VERSION 5.8 ;
BUSBITCHARS "[]" ;
DIVIDERCHAR "/" ;
UNITS
    DATABASE MICRONS 1000 ;
END UNITS

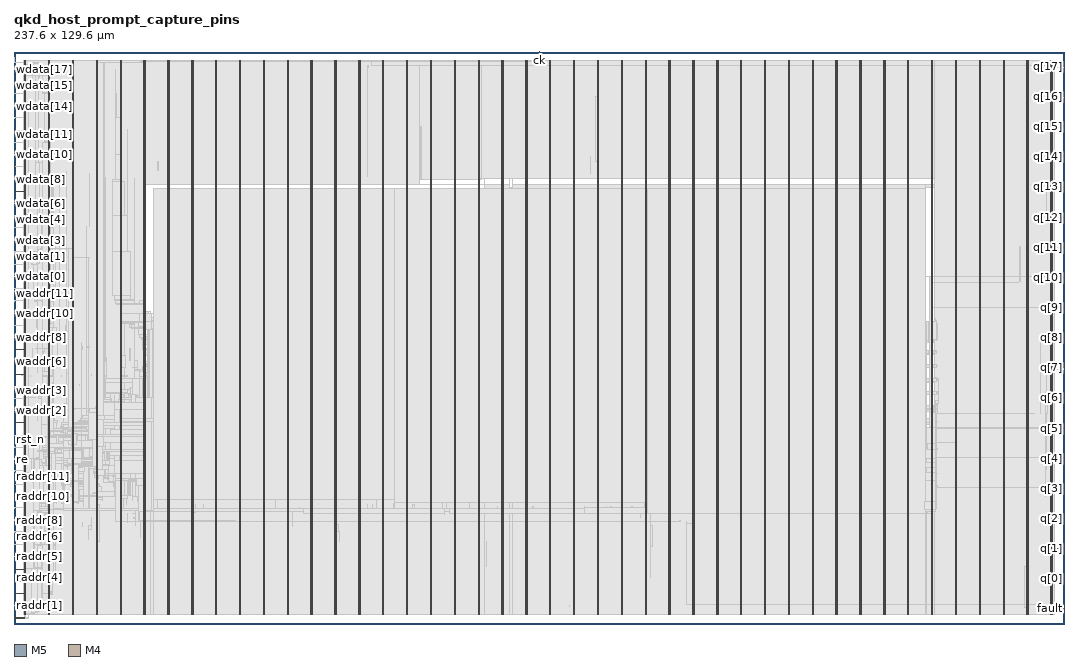
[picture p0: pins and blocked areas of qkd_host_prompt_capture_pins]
MACRO qkd_host_prompt_capture_pins
  FOREIGN qkd_host_prompt_capture_pins 0 0 ;
  CLASS BLOCK ;
  SIZE 237.6 BY 129.6 ;
  PIN ck
    DIRECTION INPUT ;
    USE SIGNAL ;
    PORT
      LAYER M5 ;
        RECT  118.8 129.516 118.824 129.6 ;
    END
    PORT
      LAYER M5 ;
        RECT  118.8 127.237 118.824 129.552 ;
    END
  END ck
  PIN fault
    DIRECTION OUTPUT ;
    USE SIGNAL ;
    PORT
      LAYER M4 ;
        RECT  237.516 3.408 237.6 3.432 ;
    END
    PORT
      LAYER M4 ;
        RECT  237.481 3.408 237.564 3.432 ;
    END
  END fault
  PIN q[0]
    DIRECTION OUTPUT ;
    USE SIGNAL ;
    PORT
      LAYER M4 ;
        RECT  237.516 10.224 237.6 10.248 ;
    END
    PORT
      LAYER M4 ;
        RECT  235.969 10.224 237.564 10.248 ;
    END
  END q[0]
  PIN q[10]
    DIRECTION OUTPUT ;
    USE SIGNAL ;
    PORT
      LAYER M4 ;
        RECT  237.516 78.432 237.6 78.456 ;
    END
    PORT
      LAYER M4 ;
        RECT  236.329 78.432 237.564 78.456 ;
    END
  END q[10]
  PIN q[11]
    DIRECTION OUTPUT ;
    USE SIGNAL ;
    PORT
      LAYER M4 ;
        RECT  237.516 85.248 237.6 85.272 ;
    END
    PORT
      LAYER M4 ;
        RECT  236.509 85.248 237.564 85.272 ;
    END
  END q[11]
  PIN q[12]
    DIRECTION OUTPUT ;
    USE SIGNAL ;
    PORT
      LAYER M4 ;
        RECT  237.516 92.064 237.6 92.088 ;
    END
    PORT
      LAYER M4 ;
        RECT  236.509 92.064 237.564 92.088 ;
    END
  END q[12]
  PIN q[13]
    DIRECTION OUTPUT ;
    USE SIGNAL ;
    PORT
      LAYER M4 ;
        RECT  237.516 98.88 237.6 98.904 ;
    END
    PORT
      LAYER M4 ;
        RECT  236.545 98.88 237.564 98.904 ;
    END
  END q[13]
  PIN q[14]
    DIRECTION OUTPUT ;
    USE SIGNAL ;
    PORT
      LAYER M4 ;
        RECT  237.516 105.696 237.6 105.72 ;
    END
    PORT
      LAYER M4 ;
        RECT  236.509 105.696 237.564 105.72 ;
    END
  END q[14]
  PIN q[15]
    DIRECTION OUTPUT ;
    USE SIGNAL ;
    PORT
      LAYER M4 ;
        RECT  237.516 112.512 237.6 112.536 ;
    END
    PORT
      LAYER M4 ;
        RECT  236.509 112.512 237.564 112.536 ;
    END
  END q[15]
  PIN q[16]
    DIRECTION OUTPUT ;
    USE SIGNAL ;
    PORT
      LAYER M4 ;
        RECT  237.516 119.376 237.6 119.4 ;
    END
    PORT
      LAYER M4 ;
        RECT  237.481 119.376 237.564 119.4 ;
    END
  END q[16]
  PIN q[17]
    DIRECTION OUTPUT ;
    USE SIGNAL ;
    PORT
      LAYER M4 ;
        RECT  237.516 126.192 237.6 126.216 ;
    END
    PORT
      LAYER M4 ;
        RECT  237.481 126.192 237.564 126.216 ;
    END
  END q[17]
  PIN q[1]
    DIRECTION OUTPUT ;
    USE SIGNAL ;
    PORT
      LAYER M4 ;
        RECT  237.516 17.04 237.6 17.064 ;
    END
    PORT
      LAYER M4 ;
        RECT  235.969 17.04 237.564 17.064 ;
    END
  END q[1]
  PIN q[2]
    DIRECTION OUTPUT ;
    USE SIGNAL ;
    PORT
      LAYER M4 ;
        RECT  237.516 23.856 237.6 23.88 ;
    END
    PORT
      LAYER M4 ;
        RECT  235.969 23.856 237.564 23.88 ;
    END
  END q[2]
  PIN q[3]
    DIRECTION OUTPUT ;
    USE SIGNAL ;
    PORT
      LAYER M4 ;
        RECT  237.516 30.672 237.6 30.696 ;
    END
    PORT
      LAYER M4 ;
        RECT  236.509 30.672 237.564 30.696 ;
    END
  END q[3]
  PIN q[4]
    DIRECTION OUTPUT ;
    USE SIGNAL ;
    PORT
      LAYER M4 ;
        RECT  237.516 37.488 237.6 37.512 ;
    END
    PORT
      LAYER M4 ;
        RECT  236.509 37.488 237.564 37.512 ;
    END
  END q[4]
  PIN q[5]
    DIRECTION OUTPUT ;
    USE SIGNAL ;
    PORT
      LAYER M4 ;
        RECT  237.516 44.304 237.6 44.328 ;
    END
    PORT
      LAYER M4 ;
        RECT  236.509 44.304 237.564 44.328 ;
    END
  END q[5]
  PIN q[6]
    DIRECTION OUTPUT ;
    USE SIGNAL ;
    PORT
      LAYER M4 ;
        RECT  237.516 51.168 237.6 51.192 ;
    END
    PORT
      LAYER M4 ;
        RECT  236.509 51.168 237.564 51.192 ;
    END
  END q[6]
  PIN q[7]
    DIRECTION OUTPUT ;
    USE SIGNAL ;
    PORT
      LAYER M4 ;
        RECT  237.516 57.984 237.6 58.008 ;
    END
    PORT
      LAYER M4 ;
        RECT  237.481 57.984 237.564 58.008 ;
    END
  END q[7]
  PIN q[8]
    DIRECTION OUTPUT ;
    USE SIGNAL ;
    PORT
      LAYER M4 ;
        RECT  237.516 64.8 237.6 64.824 ;
    END
    PORT
      LAYER M4 ;
        RECT  235.969 64.8 237.564 64.824 ;
    END
  END q[8]
  PIN q[9]
    DIRECTION OUTPUT ;
    USE SIGNAL ;
    PORT
      LAYER M4 ;
        RECT  237.516 71.616 237.6 71.64 ;
    END
    PORT
      LAYER M4 ;
        RECT  236.509 71.616 237.564 71.64 ;
    END
  END q[9]
  PIN raddr[0]
    DIRECTION INPUT ;
    USE SIGNAL ;
    PORT
      LAYER M4 ;
        RECT  0 1.344 0.084 1.368 ;
    END
    PORT
      LAYER M4 ;
        RECT  0.06 1.344 2.408 1.368 ;
    END
  END raddr[0]
  PIN raddr[10]
    DIRECTION INPUT ;
    USE SIGNAL ;
    PORT
      LAYER M4 ;
        RECT  0 28.944 0.084 28.968 ;
    END
    PORT
      LAYER M4 ;
        RECT  0.06 28.944 0.137 28.968 ;
    END
  END raddr[10]
  PIN raddr[11]
    DIRECTION INPUT ;
    USE SIGNAL ;
    PORT
      LAYER M4 ;
        RECT  0 31.68 0.084 31.704 ;
    END
    PORT
      LAYER M4 ;
        RECT  0.06 31.68 0.137 31.704 ;
    END
  END raddr[11]
  PIN raddr[12]
    DIRECTION INPUT ;
    USE SIGNAL ;
    PORT
      LAYER M4 ;
        RECT  0 34.464 0.084 34.488 ;
    END
    PORT
      LAYER M4 ;
        RECT  0.06 34.464 0.137 34.488 ;
    END
  END raddr[12]
  PIN raddr[1]
    DIRECTION INPUT ;
    USE SIGNAL ;
    PORT
      LAYER M4 ;
        RECT  0 4.128 0.084 4.152 ;
    END
    PORT
      LAYER M4 ;
        RECT  0.06 4.128 0.137 4.152 ;
    END
  END raddr[1]
  PIN raddr[2]
    DIRECTION INPUT ;
    USE SIGNAL ;
    PORT
      LAYER M4 ;
        RECT  0 6.864 0.084 6.888 ;
    END
    PORT
      LAYER M4 ;
        RECT  0.06 6.864 2.408 6.888 ;
    END
  END raddr[2]
  PIN raddr[3]
    DIRECTION INPUT ;
    USE SIGNAL ;
    PORT
      LAYER M4 ;
        RECT  0 9.648 0.084 9.672 ;
    END
    PORT
      LAYER M4 ;
        RECT  0.06 9.648 2.408 9.672 ;
    END
  END raddr[3]
  PIN raddr[4]
    DIRECTION INPUT ;
    USE SIGNAL ;
    PORT
      LAYER M4 ;
        RECT  0 12.384 0.084 12.408 ;
    END
    PORT
      LAYER M4 ;
        RECT  0.06 12.384 2.408 12.408 ;
    END
  END raddr[4]
  PIN raddr[5]
    DIRECTION INPUT ;
    USE SIGNAL ;
    PORT
      LAYER M4 ;
        RECT  0 15.168 0.084 15.192 ;
    END
    PORT
      LAYER M4 ;
        RECT  0.06 15.168 0.137 15.192 ;
    END
  END raddr[5]
  PIN raddr[6]
    DIRECTION INPUT ;
    USE SIGNAL ;
    PORT
      LAYER M4 ;
        RECT  0 17.904 0.084 17.928 ;
    END
    PORT
      LAYER M4 ;
        RECT  0.06 17.904 0.137 17.928 ;
    END
  END raddr[6]
  PIN raddr[7]
    DIRECTION INPUT ;
    USE SIGNAL ;
    PORT
      LAYER M4 ;
        RECT  0 20.688 0.084 20.712 ;
    END
    PORT
      LAYER M4 ;
        RECT  0.06 20.688 0.137 20.712 ;
    END
  END raddr[7]
  PIN raddr[8]
    DIRECTION INPUT ;
    USE SIGNAL ;
    PORT
      LAYER M4 ;
        RECT  0 23.424 0.084 23.448 ;
    END
    PORT
      LAYER M4 ;
        RECT  0.06 23.424 0.137 23.448 ;
    END
  END raddr[8]
  PIN raddr[9]
    DIRECTION INPUT ;
    USE SIGNAL ;
    PORT
      LAYER M4 ;
        RECT  0 26.208 0.084 26.232 ;
    END
    PORT
      LAYER M4 ;
        RECT  0.06 26.208 0.137 26.232 ;
    END
  END raddr[9]
  PIN re
    DIRECTION INPUT ;
    USE SIGNAL ;
    PORT
      LAYER M4 ;
        RECT  0 37.2 0.084 37.224 ;
    END
    PORT
      LAYER M4 ;
        RECT  0.06 37.2 0.137 37.224 ;
    END
  END re
  PIN rst_n
    DIRECTION INPUT ;
    USE SIGNAL ;
    PORT
      LAYER M4 ;
        RECT  0 39.984 0.084 40.008 ;
    END
    PORT
      LAYER M4 ;
        RECT  0.06 39.984 0.137 40.008 ;
    END
  END rst_n
  PIN waddr[0]
    DIRECTION INPUT ;
    USE SIGNAL ;
    PORT
      LAYER M4 ;
        RECT  0 42.72 0.084 42.744 ;
    END
    PORT
      LAYER M4 ;
        RECT  0.06 42.72 0.137 42.744 ;
    END
  END waddr[0]
  PIN waddr[10]
    DIRECTION INPUT ;
    USE SIGNAL ;
    PORT
      LAYER M4 ;
        RECT  0 70.32 0.084 70.344 ;
    END
    PORT
      LAYER M4 ;
        RECT  0.06 70.32 0.137 70.344 ;
    END
  END waddr[10]
  PIN waddr[11]
    DIRECTION INPUT ;
    USE SIGNAL ;
    PORT
      LAYER M4 ;
        RECT  0 73.056 0.084 73.08 ;
    END
    PORT
      LAYER M4 ;
        RECT  0.06 73.056 0.137 73.08 ;
    END
  END waddr[11]
  PIN waddr[12]
    DIRECTION INPUT ;
    USE SIGNAL ;
    PORT
      LAYER M4 ;
        RECT  0 75.84 0.084 75.864 ;
    END
    PORT
      LAYER M4 ;
        RECT  0.06 75.84 0.137 75.864 ;
    END
  END waddr[12]
  PIN waddr[1]
    DIRECTION INPUT ;
    USE SIGNAL ;
    PORT
      LAYER M4 ;
        RECT  0 45.504 0.084 45.528 ;
    END
    PORT
      LAYER M4 ;
        RECT  0.06 45.504 2.408 45.528 ;
    END
  END waddr[1]
  PIN waddr[2]
    DIRECTION INPUT ;
    USE SIGNAL ;
    PORT
      LAYER M4 ;
        RECT  0 48.24 0.084 48.264 ;
    END
    PORT
      LAYER M4 ;
        RECT  0.06 48.24 0.137 48.264 ;
    END
  END waddr[2]
  PIN waddr[3]
    DIRECTION INPUT ;
    USE SIGNAL ;
    PORT
      LAYER M4 ;
        RECT  0 51.024 0.084 51.048 ;
    END
    PORT
      LAYER M4 ;
        RECT  0.06 51.024 0.137 51.048 ;
    END
  END waddr[3]
  PIN waddr[4]
    DIRECTION INPUT ;
    USE SIGNAL ;
    PORT
      LAYER M4 ;
        RECT  0 53.76 0.084 53.784 ;
    END
    PORT
      LAYER M4 ;
        RECT  0.06 53.76 0.137 53.784 ;
    END
  END waddr[4]
  PIN waddr[5]
    DIRECTION INPUT ;
    USE SIGNAL ;
    PORT
      LAYER M4 ;
        RECT  0 56.496 0.084 56.52 ;
    END
    PORT
      LAYER M4 ;
        RECT  0.06 56.496 2.408 56.52 ;
    END
  END waddr[5]
  PIN waddr[6]
    DIRECTION INPUT ;
    USE SIGNAL ;
    PORT
      LAYER M4 ;
        RECT  0 59.28 0.084 59.304 ;
    END
    PORT
      LAYER M4 ;
        RECT  0.06 59.28 0.137 59.304 ;
    END
  END waddr[6]
  PIN waddr[7]
    DIRECTION INPUT ;
    USE SIGNAL ;
    PORT
      LAYER M4 ;
        RECT  0 62.016 0.084 62.04 ;
    END
    PORT
      LAYER M4 ;
        RECT  0.06 62.016 2.408 62.04 ;
    END
  END waddr[7]
  PIN waddr[8]
    DIRECTION INPUT ;
    USE SIGNAL ;
    PORT
      LAYER M4 ;
        RECT  0 64.8 0.084 64.824 ;
    END
    PORT
      LAYER M4 ;
        RECT  0.06 64.8 0.137 64.824 ;
    END
  END waddr[8]
  PIN waddr[9]
    DIRECTION INPUT ;
    USE SIGNAL ;
    PORT
      LAYER M4 ;
        RECT  0 67.536 0.084 67.56 ;
    END
    PORT
      LAYER M4 ;
        RECT  0.06 67.536 0.137 67.56 ;
    END
  END waddr[9]
  PIN wdata[0]
    DIRECTION INPUT ;
    USE SIGNAL ;
    PORT
      LAYER M4 ;
        RECT  0 78.576 0.084 78.6 ;
    END
    PORT
      LAYER M4 ;
        RECT  0.06 78.576 0.137 78.6 ;
    END
  END wdata[0]
  PIN wdata[10]
    DIRECTION INPUT ;
    USE SIGNAL ;
    PORT
      LAYER M4 ;
        RECT  0 106.128 0.084 106.152 ;
    END
    PORT
      LAYER M4 ;
        RECT  0.06 106.128 0.137 106.152 ;
    END
  END wdata[10]
  PIN wdata[11]
    DIRECTION INPUT ;
    USE SIGNAL ;
    PORT
      LAYER M4 ;
        RECT  0 108.912 0.084 108.936 ;
    END
    PORT
      LAYER M4 ;
        RECT  0.06 108.912 0.137 108.936 ;
    END
  END wdata[11]
  PIN wdata[12]
    DIRECTION INPUT ;
    USE SIGNAL ;
    PORT
      LAYER M4 ;
        RECT  0 111.648 0.084 111.672 ;
    END
    PORT
      LAYER M4 ;
        RECT  0.06 111.648 2.408 111.672 ;
    END
  END wdata[12]
  PIN wdata[13]
    DIRECTION INPUT ;
    USE SIGNAL ;
    PORT
      LAYER M4 ;
        RECT  0 114.432 0.084 114.456 ;
    END
    PORT
      LAYER M4 ;
        RECT  0.06 114.432 0.137 114.456 ;
    END
  END wdata[13]
  PIN wdata[14]
    DIRECTION INPUT ;
    USE SIGNAL ;
    PORT
      LAYER M4 ;
        RECT  0 117.168 0.084 117.192 ;
    END
    PORT
      LAYER M4 ;
        RECT  0.06 117.168 0.137 117.192 ;
    END
  END wdata[14]
  PIN wdata[15]
    DIRECTION INPUT ;
    USE SIGNAL ;
    PORT
      LAYER M4 ;
        RECT  0 119.952 0.084 119.976 ;
    END
    PORT
      LAYER M4 ;
        RECT  0.06 119.952 0.137 119.976 ;
    END
  END wdata[15]
  PIN wdata[16]
    DIRECTION INPUT ;
    USE SIGNAL ;
    PORT
      LAYER M4 ;
        RECT  0 122.688 0.084 122.712 ;
    END
    PORT
      LAYER M4 ;
        RECT  0.06 122.688 0.569 122.712 ;
    END
  END wdata[16]
  PIN wdata[17]
    DIRECTION INPUT ;
    USE SIGNAL ;
    PORT
      LAYER M4 ;
        RECT  0 125.472 0.084 125.496 ;
    END
    PORT
      LAYER M4 ;
        RECT  0.06 125.472 0.137 125.496 ;
    END
  END wdata[17]
  PIN wdata[1]
    DIRECTION INPUT ;
    USE SIGNAL ;
    PORT
      LAYER M4 ;
        RECT  0 81.312 0.084 81.336 ;
    END
    PORT
      LAYER M4 ;
        RECT  0.06 81.312 0.137 81.336 ;
    END
  END wdata[1]
  PIN wdata[2]
    DIRECTION INPUT ;
    USE SIGNAL ;
    PORT
      LAYER M4 ;
        RECT  0 84.096 0.084 84.12 ;
    END
    PORT
      LAYER M4 ;
        RECT  0.06 84.096 0.137 84.12 ;
    END
  END wdata[2]
  PIN wdata[3]
    DIRECTION INPUT ;
    USE SIGNAL ;
    PORT
      LAYER M4 ;
        RECT  0 86.832 0.084 86.856 ;
    END
    PORT
      LAYER M4 ;
        RECT  0.06 86.832 0.137 86.856 ;
    END
  END wdata[3]
  PIN wdata[4]
    DIRECTION INPUT ;
    USE SIGNAL ;
    PORT
      LAYER M4 ;
        RECT  0 89.616 0.084 89.64 ;
    END
    PORT
      LAYER M4 ;
        RECT  0.06 89.616 0.137 89.64 ;
    END
  END wdata[4]
  PIN wdata[5]
    DIRECTION INPUT ;
    USE SIGNAL ;
    PORT
      LAYER M4 ;
        RECT  0 92.352 0.084 92.376 ;
    END
    PORT
      LAYER M4 ;
        RECT  0.06 92.352 0.137 92.376 ;
    END
  END wdata[5]
  PIN wdata[6]
    DIRECTION INPUT ;
    USE SIGNAL ;
    PORT
      LAYER M4 ;
        RECT  0 95.136 0.084 95.16 ;
    END
    PORT
      LAYER M4 ;
        RECT  0.06 95.136 0.137 95.16 ;
    END
  END wdata[6]
  PIN wdata[7]
    DIRECTION INPUT ;
    USE SIGNAL ;
    PORT
      LAYER M4 ;
        RECT  0 97.872 0.084 97.896 ;
    END
    PORT
      LAYER M4 ;
        RECT  0.06 97.872 2.408 97.896 ;
    END
  END wdata[7]
  PIN wdata[8]
    DIRECTION INPUT ;
    USE SIGNAL ;
    PORT
      LAYER M4 ;
        RECT  0 100.656 0.084 100.68 ;
    END
    PORT
      LAYER M4 ;
        RECT  0.06 100.656 0.137 100.68 ;
    END
  END wdata[8]
  PIN wdata[9]
    DIRECTION INPUT ;
    USE SIGNAL ;
    PORT
      LAYER M4 ;
        RECT  0 103.392 0.084 103.416 ;
    END
    PORT
      LAYER M4 ;
        RECT  0.06 103.392 0.137 103.416 ;
    END
  END wdata[9]
  PIN we
    DIRECTION INPUT ;
    USE SIGNAL ;
    PORT
      LAYER M4 ;
        RECT  0 128.208 0.084 128.232 ;
    END
    PORT
      LAYER M4 ;
        RECT  0.06 128.208 0.137 128.232 ;
    END
  END we
  PIN VDD
    DIRECTION INOUT ;
    USE POWER ;
    PORT
      LAYER M5 ;
        RECT  234.792 2.151 234.912 127.449 ;
        RECT  229.392 2.151 229.512 127.449 ;
        RECT  223.992 2.151 224.112 127.449 ;
        RECT  218.592 2.151 218.712 127.449 ;
        RECT  213.192 2.151 213.312 127.449 ;
        RECT  207.792 2.151 207.912 127.449 ;
        RECT  202.392 2.151 202.512 127.449 ;
        RECT  196.992 2.151 197.112 127.449 ;
        RECT  191.592 2.151 191.712 127.449 ;
        RECT  186.192 2.151 186.312 127.449 ;
        RECT  180.792 2.151 180.912 127.449 ;
        RECT  175.392 2.151 175.512 127.449 ;
        RECT  169.992 2.151 170.112 127.449 ;
        RECT  164.592 2.151 164.712 127.449 ;
        RECT  159.192 2.151 159.312 127.449 ;
        RECT  153.792 2.151 153.912 127.449 ;
        RECT  148.392 2.151 148.512 127.449 ;
        RECT  142.992 2.151 143.112 127.449 ;
        RECT  137.592 2.151 137.712 127.449 ;
        RECT  132.192 2.151 132.312 127.449 ;
        RECT  126.792 2.151 126.912 127.449 ;
        RECT  121.392 2.151 121.512 127.449 ;
        RECT  115.992 2.151 116.112 127.449 ;
        RECT  110.592 2.151 110.712 127.449 ;
        RECT  105.192 2.151 105.312 127.449 ;
        RECT  99.792 2.151 99.912 127.449 ;
        RECT  94.392 2.151 94.512 127.449 ;
        RECT  88.992 2.151 89.112 127.449 ;
        RECT  83.592 2.151 83.712 127.449 ;
        RECT  78.192 2.151 78.312 127.449 ;
        RECT  72.792 2.151 72.912 127.449 ;
        RECT  67.392 2.151 67.512 127.449 ;
        RECT  61.992 2.151 62.112 127.449 ;
        RECT  56.592 2.151 56.712 127.449 ;
        RECT  51.192 2.151 51.312 127.449 ;
        RECT  45.792 2.151 45.912 127.449 ;
        RECT  40.392 2.151 40.512 127.449 ;
        RECT  34.992 2.151 35.112 127.449 ;
        RECT  29.592 2.151 29.712 127.449 ;
        RECT  24.192 2.151 24.312 127.449 ;
        RECT  18.792 2.151 18.912 127.449 ;
        RECT  13.392 2.151 13.512 127.449 ;
        RECT  7.992 2.151 8.112 127.449 ;
        RECT  2.592 2.151 2.712 127.449 ;
    END
  END VDD
  PIN VSS
    DIRECTION INOUT ;
    USE GROUND ;
    PORT
      LAYER M5 ;
        RECT  234.6 2.137 234.72 127.463 ;
        RECT  229.2 2.137 229.32 127.463 ;
        RECT  223.8 2.137 223.92 127.463 ;
        RECT  218.4 2.137 218.52 127.463 ;
        RECT  213 2.137 213.12 127.463 ;
        RECT  207.6 2.137 207.72 127.463 ;
        RECT  202.2 2.137 202.32 127.463 ;
        RECT  196.8 2.137 196.92 127.463 ;
        RECT  191.4 2.137 191.52 127.463 ;
        RECT  186 2.137 186.12 127.463 ;
        RECT  180.6 2.137 180.72 127.463 ;
        RECT  175.2 2.137 175.32 127.463 ;
        RECT  169.8 2.137 169.92 127.463 ;
        RECT  164.4 2.137 164.52 127.463 ;
        RECT  159 2.137 159.12 127.463 ;
        RECT  153.6 2.137 153.72 127.463 ;
        RECT  148.2 2.137 148.32 127.463 ;
        RECT  142.8 2.137 142.92 127.463 ;
        RECT  137.4 2.137 137.52 127.463 ;
        RECT  132 2.137 132.12 127.463 ;
        RECT  126.6 2.137 126.72 127.463 ;
        RECT  121.2 2.137 121.32 127.463 ;
        RECT  115.8 2.137 115.92 127.463 ;
        RECT  110.4 2.137 110.52 127.463 ;
        RECT  105 2.137 105.12 127.463 ;
        RECT  99.6 2.137 99.72 127.463 ;
        RECT  94.2 2.137 94.32 127.463 ;
        RECT  88.8 2.137 88.92 127.463 ;
        RECT  83.4 2.137 83.52 127.463 ;
        RECT  78 2.137 78.12 127.463 ;
        RECT  72.6 2.137 72.72 127.463 ;
        RECT  67.2 2.137 67.32 127.463 ;
        RECT  61.8 2.137 61.92 127.463 ;
        RECT  56.4 2.137 56.52 127.463 ;
        RECT  51 2.137 51.12 127.463 ;
        RECT  45.6 2.137 45.72 127.463 ;
        RECT  40.2 2.137 40.32 127.463 ;
        RECT  34.8 2.137 34.92 127.463 ;
        RECT  29.4 2.137 29.52 127.463 ;
        RECT  24 2.137 24.12 127.463 ;
        RECT  18.6 2.137 18.72 127.463 ;
        RECT  13.2 2.137 13.32 127.463 ;
        RECT  7.8 2.137 7.92 127.463 ;
        RECT  2.4 2.137 2.52 127.463 ;
    END
  END VSS
  # OT_OBS_CLOSED layer=M5 d_um=1.536 added=61
  OBS
    LAYER RVTN ;
     RECT  2.16 2.16 235.44 2.295 ;
     RECT  2.16 2.565 235.44 2.835 ;
     RECT  2.16 3.105 235.44 3.375 ;
     RECT  2.16 3.645 235.44 3.915 ;
     RECT  2.16 4.185 235.44 4.455 ;
     RECT  2.16 4.725 235.44 4.995 ;
     RECT  2.16 5.265 235.44 5.535 ;
     RECT  2.16 5.805 235.44 6.075 ;
     RECT  2.16 6.345 235.44 6.615 ;
     RECT  2.16 6.885 235.44 7.155 ;
     RECT  2.16 7.425 235.44 7.695 ;
     RECT  2.16 7.965 235.44 8.235 ;
     RECT  2.16 8.505 235.44 8.775 ;
     RECT  2.16 9.045 235.44 9.315 ;
     RECT  2.16 9.585 235.44 9.855 ;
     RECT  2.16 10.125 235.44 10.395 ;
     RECT  2.16 10.665 235.44 10.935 ;
     RECT  2.16 11.205 235.44 11.475 ;
     RECT  2.16 11.745 235.44 12.015 ;
     RECT  2.16 12.285 235.44 12.555 ;
     RECT  2.16 12.825 235.44 13.095 ;
     RECT  2.16 13.365 235.44 13.635 ;
     RECT  2.16 13.905 235.44 14.175 ;
     RECT  2.16 14.445 235.44 14.715 ;
     RECT  2.16 14.985 235.44 15.255 ;
     RECT  2.16 15.525 235.44 15.795 ;
     RECT  2.16 16.065 235.44 16.335 ;
     RECT  2.16 16.605 235.44 16.875 ;
     RECT  2.16 17.145 235.44 17.415 ;
     RECT  2.16 17.685 235.44 17.955 ;
     RECT  2.16 18.225 235.44 18.495 ;
     RECT  2.16 18.765 235.44 19.035 ;
     RECT  2.16 19.305 235.44 19.575 ;
     RECT  2.16 19.845 235.44 20.115 ;
     RECT  2.16 20.385 235.44 20.655 ;
     RECT  2.16 20.925 235.44 21.195 ;
     RECT  2.16 21.465 235.44 21.735 ;
     RECT  2.16 22.005 235.44 22.275 ;
     RECT  2.16 22.545 235.44 22.815 ;
     RECT  2.16 23.085 235.44 23.355 ;
     RECT  2.16 23.625 235.44 23.895 ;
     RECT  2.16 24.165 235.44 24.435 ;
     RECT  2.16 24.705 235.44 24.975 ;
     RECT  2.16 25.245 235.44 25.515 ;
     RECT  2.16 25.785 235.44 25.92 ;
     RECT  2.16 25.92 29.484 26.055 ;
     RECT  208.332 25.92 235.44 26.055 ;
     RECT  2.16 26.325 29.484 26.595 ;
     RECT  208.332 26.325 235.44 26.595 ;
     RECT  2.16 26.865 29.484 27.135 ;
     RECT  208.332 26.865 235.44 27.135 ;
     RECT  2.16 27.405 29.484 27.675 ;
     RECT  208.332 27.405 235.44 27.675 ;
     RECT  2.16 27.945 29.484 28.215 ;
     RECT  208.332 27.945 235.44 28.215 ;
     RECT  2.16 28.485 29.484 28.755 ;
     RECT  208.332 28.485 235.44 28.755 ;
     RECT  2.16 29.025 29.484 29.295 ;
     RECT  208.332 29.025 235.44 29.295 ;
     RECT  2.16 29.565 29.484 29.835 ;
     RECT  208.332 29.565 235.44 29.835 ;
     RECT  2.16 30.105 29.484 30.375 ;
     RECT  208.332 30.105 235.44 30.375 ;
     RECT  2.16 30.645 29.484 30.915 ;
     RECT  208.332 30.645 235.44 30.915 ;
     RECT  2.16 31.185 29.484 31.455 ;
     RECT  208.332 31.185 235.44 31.455 ;
     RECT  2.16 31.725 29.484 31.995 ;
     RECT  208.332 31.725 235.44 31.995 ;
     RECT  2.16 32.265 29.484 32.535 ;
     RECT  208.332 32.265 235.44 32.535 ;
     RECT  2.16 32.805 29.484 33.075 ;
     RECT  208.332 32.805 235.44 33.075 ;
     RECT  2.16 33.345 29.484 33.615 ;
     RECT  208.332 33.345 235.44 33.615 ;
     RECT  2.16 33.885 29.484 34.155 ;
     RECT  208.332 33.885 235.44 34.155 ;
     RECT  2.16 34.425 29.484 34.695 ;
     RECT  208.332 34.425 235.44 34.695 ;
     RECT  2.16 34.965 29.484 35.235 ;
     RECT  208.332 34.965 235.44 35.235 ;
     RECT  2.16 35.505 29.484 35.775 ;
     RECT  208.332 35.505 235.44 35.775 ;
     RECT  2.16 36.045 29.484 36.315 ;
     RECT  208.332 36.045 235.44 36.315 ;
     RECT  2.16 36.585 29.484 36.855 ;
     RECT  208.332 36.585 235.44 36.855 ;
     RECT  2.16 37.125 29.484 37.395 ;
     RECT  208.332 37.125 235.44 37.395 ;
     RECT  2.16 37.665 29.484 37.935 ;
     RECT  208.332 37.665 235.44 37.935 ;
     RECT  2.16 38.205 29.484 38.475 ;
     RECT  208.332 38.205 235.44 38.475 ;
     RECT  2.16 38.745 29.484 39.015 ;
     RECT  208.332 38.745 235.44 39.015 ;
     RECT  2.16 39.285 29.484 39.555 ;
     RECT  208.332 39.285 235.44 39.555 ;
     RECT  2.16 39.825 29.484 40.095 ;
     RECT  208.332 39.825 235.44 40.095 ;
     RECT  2.16 40.365 29.484 40.635 ;
     RECT  208.332 40.365 235.44 40.635 ;
     RECT  2.16 40.905 29.484 41.175 ;
     RECT  208.332 40.905 235.44 41.175 ;
     RECT  2.16 41.445 29.484 41.715 ;
     RECT  208.332 41.445 235.44 41.715 ;
     RECT  2.16 41.985 29.484 42.255 ;
     RECT  208.332 41.985 235.44 42.255 ;
     RECT  2.16 42.525 29.484 42.795 ;
     RECT  208.332 42.525 235.44 42.795 ;
     RECT  2.16 43.065 29.484 43.335 ;
     RECT  208.332 43.065 235.44 43.335 ;
     RECT  2.16 43.605 29.484 43.875 ;
     RECT  208.332 43.605 235.44 43.875 ;
     RECT  2.16 44.145 29.484 44.415 ;
     RECT  208.332 44.145 235.44 44.415 ;
     RECT  2.16 44.685 29.484 44.955 ;
     RECT  208.332 44.685 235.44 44.955 ;
     RECT  2.16 45.225 29.484 45.495 ;
     RECT  208.332 45.225 235.44 45.495 ;
     RECT  2.16 45.765 29.484 46.035 ;
     RECT  208.332 45.765 235.44 46.035 ;
     RECT  2.16 46.305 29.484 46.575 ;
     RECT  208.332 46.305 235.44 46.575 ;
     RECT  2.16 46.845 29.484 47.115 ;
     RECT  208.332 46.845 235.44 47.115 ;
     RECT  2.16 47.385 29.484 47.655 ;
     RECT  208.332 47.385 235.44 47.655 ;
     RECT  2.16 47.925 29.484 48.195 ;
     RECT  208.332 47.925 235.44 48.195 ;
     RECT  2.16 48.465 29.484 48.735 ;
     RECT  208.332 48.465 235.44 48.735 ;
     RECT  2.16 49.005 29.484 49.275 ;
     RECT  208.332 49.005 235.44 49.275 ;
     RECT  2.16 49.545 29.484 49.815 ;
     RECT  208.332 49.545 235.44 49.815 ;
     RECT  2.16 50.085 29.484 50.355 ;
     RECT  208.332 50.085 235.44 50.355 ;
     RECT  2.16 50.625 29.484 50.895 ;
     RECT  208.332 50.625 235.44 50.895 ;
     RECT  2.16 51.165 29.484 51.435 ;
     RECT  208.332 51.165 235.44 51.435 ;
     RECT  2.16 51.705 29.484 51.975 ;
     RECT  208.332 51.705 235.44 51.975 ;
     RECT  2.16 52.245 29.484 52.515 ;
     RECT  208.332 52.245 235.44 52.515 ;
     RECT  2.16 52.785 29.484 53.055 ;
     RECT  208.332 52.785 235.44 53.055 ;
     RECT  2.16 53.325 29.484 53.595 ;
     RECT  208.332 53.325 235.44 53.595 ;
     RECT  2.16 53.865 29.484 54.135 ;
     RECT  208.332 53.865 235.44 54.135 ;
     RECT  2.16 54.405 29.484 54.675 ;
     RECT  208.332 54.405 235.44 54.675 ;
     RECT  2.16 54.945 29.484 55.215 ;
     RECT  208.332 54.945 235.44 55.215 ;
     RECT  2.16 55.485 29.484 55.755 ;
     RECT  208.332 55.485 235.44 55.755 ;
     RECT  2.16 56.025 29.484 56.295 ;
     RECT  208.332 56.025 235.44 56.295 ;
     RECT  2.16 56.565 29.484 56.835 ;
     RECT  208.332 56.565 235.44 56.835 ;
     RECT  2.16 57.105 29.484 57.375 ;
     RECT  208.332 57.105 235.44 57.375 ;
     RECT  2.16 57.645 29.484 57.915 ;
     RECT  208.332 57.645 235.44 57.915 ;
     RECT  2.16 58.185 29.484 58.455 ;
     RECT  208.332 58.185 235.44 58.455 ;
     RECT  2.16 58.725 29.484 58.995 ;
     RECT  208.332 58.725 235.44 58.995 ;
     RECT  2.16 59.265 29.484 59.535 ;
     RECT  208.332 59.265 235.44 59.535 ;
     RECT  2.16 59.805 29.484 60.075 ;
     RECT  208.332 59.805 235.44 60.075 ;
     RECT  2.16 60.345 29.484 60.615 ;
     RECT  208.332 60.345 235.44 60.615 ;
     RECT  2.16 60.885 29.484 61.155 ;
     RECT  208.332 60.885 235.44 61.155 ;
     RECT  2.16 61.425 29.484 61.695 ;
     RECT  208.332 61.425 235.44 61.695 ;
     RECT  2.16 61.965 29.484 62.235 ;
     RECT  208.332 61.965 235.44 62.235 ;
     RECT  2.16 62.505 29.484 62.775 ;
     RECT  208.332 62.505 235.44 62.775 ;
     RECT  2.16 63.045 29.484 63.315 ;
     RECT  208.332 63.045 235.44 63.315 ;
     RECT  2.16 63.585 29.484 63.855 ;
     RECT  208.332 63.585 235.44 63.855 ;
     RECT  2.16 64.125 29.484 64.395 ;
     RECT  208.332 64.125 235.44 64.395 ;
     RECT  2.16 64.665 29.484 64.935 ;
     RECT  208.332 64.665 235.44 64.935 ;
     RECT  2.16 65.205 29.484 65.475 ;
     RECT  208.332 65.205 235.44 65.475 ;
     RECT  2.16 65.745 29.484 66.015 ;
     RECT  208.332 65.745 235.44 66.015 ;
     RECT  2.16 66.285 29.484 66.555 ;
     RECT  208.332 66.285 235.44 66.555 ;
     RECT  2.16 66.825 29.484 67.095 ;
     RECT  208.332 66.825 235.44 67.095 ;
     RECT  2.16 67.365 29.484 67.635 ;
     RECT  208.332 67.365 235.44 67.635 ;
     RECT  2.16 67.905 29.484 68.175 ;
     RECT  208.332 67.905 235.44 68.175 ;
     RECT  2.16 68.445 29.484 68.715 ;
     RECT  208.332 68.445 235.44 68.715 ;
     RECT  2.16 68.985 29.484 69.255 ;
     RECT  208.332 68.985 235.44 69.255 ;
     RECT  2.16 69.525 29.484 69.795 ;
     RECT  208.332 69.525 235.44 69.795 ;
     RECT  2.16 70.065 29.484 70.335 ;
     RECT  208.332 70.065 235.44 70.335 ;
     RECT  2.16 70.605 29.484 70.875 ;
     RECT  208.332 70.605 235.44 70.875 ;
     RECT  2.16 71.145 29.484 71.415 ;
     RECT  208.332 71.145 235.44 71.415 ;
     RECT  2.16 71.685 29.484 71.955 ;
     RECT  208.332 71.685 235.44 71.955 ;
     RECT  2.16 72.225 29.484 72.495 ;
     RECT  208.332 72.225 235.44 72.495 ;
     RECT  2.16 72.765 29.484 73.035 ;
     RECT  208.332 72.765 235.44 73.035 ;
     RECT  2.16 73.305 29.484 73.575 ;
     RECT  208.332 73.305 235.44 73.575 ;
     RECT  2.16 73.845 29.484 74.115 ;
     RECT  208.332 73.845 235.44 74.115 ;
     RECT  2.16 74.385 29.484 74.655 ;
     RECT  208.332 74.385 235.44 74.655 ;
     RECT  2.16 74.925 29.484 75.195 ;
     RECT  208.332 74.925 235.44 75.195 ;
     RECT  2.16 75.465 29.484 75.735 ;
     RECT  208.332 75.465 235.44 75.735 ;
     RECT  2.16 76.005 29.484 76.275 ;
     RECT  208.332 76.005 235.44 76.275 ;
     RECT  2.16 76.545 29.484 76.815 ;
     RECT  208.332 76.545 235.44 76.815 ;
     RECT  2.16 77.085 29.484 77.355 ;
     RECT  208.332 77.085 235.44 77.355 ;
     RECT  2.16 77.625 29.484 77.895 ;
     RECT  208.332 77.625 235.44 77.895 ;
     RECT  2.16 78.165 29.484 78.435 ;
     RECT  208.332 78.165 235.44 78.435 ;
     RECT  2.16 78.705 29.484 78.975 ;
     RECT  208.332 78.705 235.44 78.975 ;
     RECT  2.16 79.245 29.484 79.515 ;
     RECT  208.332 79.245 235.44 79.515 ;
     RECT  2.16 79.785 29.484 80.055 ;
     RECT  208.332 79.785 235.44 80.055 ;
     RECT  2.16 80.325 29.484 80.595 ;
     RECT  208.332 80.325 235.44 80.595 ;
     RECT  2.16 80.865 29.484 81.135 ;
     RECT  208.332 80.865 235.44 81.135 ;
     RECT  2.16 81.405 29.484 81.675 ;
     RECT  208.332 81.405 235.44 81.675 ;
     RECT  2.16 81.945 29.484 82.215 ;
     RECT  208.332 81.945 235.44 82.215 ;
     RECT  2.16 82.485 29.484 82.755 ;
     RECT  208.332 82.485 235.44 82.755 ;
     RECT  2.16 83.025 29.484 83.295 ;
     RECT  208.332 83.025 235.44 83.295 ;
     RECT  2.16 83.565 29.484 83.835 ;
     RECT  208.332 83.565 235.44 83.835 ;
     RECT  2.16 84.105 29.484 84.375 ;
     RECT  208.332 84.105 235.44 84.375 ;
     RECT  2.16 84.645 29.484 84.915 ;
     RECT  208.332 84.645 235.44 84.915 ;
     RECT  2.16 85.185 29.484 85.455 ;
     RECT  208.332 85.185 235.44 85.455 ;
     RECT  2.16 85.725 29.484 85.995 ;
     RECT  208.332 85.725 235.44 85.995 ;
     RECT  2.16 86.265 29.484 86.535 ;
     RECT  208.332 86.265 235.44 86.535 ;
     RECT  2.16 86.805 29.484 87.075 ;
     RECT  208.332 86.805 235.44 87.075 ;
     RECT  2.16 87.345 29.484 87.615 ;
     RECT  208.332 87.345 235.44 87.615 ;
     RECT  2.16 87.885 29.484 88.155 ;
     RECT  208.332 87.885 235.44 88.155 ;
     RECT  2.16 88.425 29.484 88.695 ;
     RECT  208.332 88.425 235.44 88.695 ;
     RECT  2.16 88.965 29.484 89.235 ;
     RECT  208.332 88.965 235.44 89.235 ;
     RECT  2.16 89.505 29.484 89.775 ;
     RECT  208.332 89.505 235.44 89.775 ;
     RECT  2.16 90.045 29.484 90.315 ;
     RECT  208.332 90.045 235.44 90.315 ;
     RECT  2.16 90.585 29.484 90.855 ;
     RECT  208.332 90.585 235.44 90.855 ;
     RECT  2.16 91.125 29.484 91.395 ;
     RECT  208.332 91.125 235.44 91.395 ;
     RECT  2.16 91.665 29.484 91.935 ;
     RECT  208.332 91.665 235.44 91.935 ;
     RECT  2.16 92.205 29.484 92.475 ;
     RECT  208.332 92.205 235.44 92.475 ;
     RECT  2.16 92.745 29.484 93.015 ;
     RECT  208.332 92.745 235.44 93.015 ;
     RECT  2.16 93.285 29.484 93.555 ;
     RECT  208.332 93.285 235.44 93.555 ;
     RECT  2.16 93.825 29.484 94.095 ;
     RECT  208.332 93.825 235.44 94.095 ;
     RECT  2.16 94.365 29.484 94.635 ;
     RECT  208.332 94.365 235.44 94.635 ;
     RECT  2.16 94.905 29.484 95.175 ;
     RECT  208.332 94.905 235.44 95.175 ;
     RECT  2.16 95.445 29.484 95.715 ;
     RECT  208.332 95.445 235.44 95.715 ;
     RECT  2.16 95.985 29.484 96.255 ;
     RECT  208.332 95.985 235.44 96.255 ;
     RECT  2.16 96.525 29.484 96.795 ;
     RECT  208.332 96.525 235.44 96.795 ;
     RECT  2.16 97.065 29.484 97.335 ;
     RECT  208.332 97.065 235.44 97.335 ;
     RECT  2.16 97.605 29.484 97.875 ;
     RECT  208.332 97.605 235.44 97.875 ;
     RECT  2.16 98.145 29.484 98.415 ;
     RECT  208.332 98.145 235.44 98.415 ;
     RECT  2.16 98.685 29.484 98.955 ;
     RECT  208.332 98.685 235.44 98.955 ;
     RECT  2.16 99.225 29.484 99.495 ;
     RECT  208.332 99.225 235.44 99.495 ;
     RECT  2.16 99.765 29.484 100.035 ;
     RECT  208.332 99.765 235.44 100.035 ;
     RECT  2.16 100.305 29.484 100.575 ;
     RECT  208.332 100.305 235.44 100.575 ;
     RECT  2.16 100.845 235.44 101.115 ;
     RECT  2.16 101.385 235.44 101.655 ;
     RECT  2.16 101.925 235.44 102.195 ;
     RECT  2.16 102.465 235.44 102.735 ;
     RECT  2.16 103.005 235.44 103.275 ;
     RECT  2.16 103.545 235.44 103.815 ;
     RECT  2.16 104.085 235.44 104.355 ;
     RECT  2.16 104.625 235.44 104.895 ;
     RECT  2.16 105.165 235.44 105.435 ;
     RECT  2.16 105.705 235.44 105.975 ;
     RECT  2.16 106.245 235.44 106.515 ;
     RECT  2.16 106.785 235.44 107.055 ;
     RECT  2.16 107.325 235.44 107.595 ;
     RECT  2.16 107.865 235.44 108.135 ;
     RECT  2.16 108.405 235.44 108.675 ;
     RECT  2.16 108.945 235.44 109.215 ;
     RECT  2.16 109.485 235.44 109.755 ;
     RECT  2.16 110.025 235.44 110.295 ;
     RECT  2.16 110.565 235.44 110.835 ;
     RECT  2.16 111.105 235.44 111.375 ;
     RECT  2.16 111.645 235.44 111.915 ;
     RECT  2.16 112.185 235.44 112.455 ;
     RECT  2.16 112.725 235.44 112.995 ;
     RECT  2.16 113.265 235.44 113.535 ;
     RECT  2.16 113.805 235.44 114.075 ;
     RECT  2.16 114.345 235.44 114.615 ;
     RECT  2.16 114.885 235.44 115.155 ;
     RECT  2.16 115.425 235.44 115.695 ;
     RECT  2.16 115.965 235.44 116.235 ;
     RECT  2.16 116.505 235.44 116.775 ;
     RECT  2.16 117.045 235.44 117.315 ;
     RECT  2.16 117.585 235.44 117.855 ;
     RECT  2.16 118.125 235.44 118.395 ;
     RECT  2.16 118.665 235.44 118.935 ;
     RECT  2.16 119.205 235.44 119.475 ;
     RECT  2.16 119.745 235.44 120.015 ;
     RECT  2.16 120.285 235.44 120.555 ;
     RECT  2.16 120.825 235.44 121.095 ;
     RECT  2.16 121.365 235.44 121.635 ;
     RECT  2.16 121.905 235.44 122.175 ;
     RECT  2.16 122.445 235.44 122.715 ;
     RECT  2.16 122.985 235.44 123.255 ;
     RECT  2.16 123.525 235.44 123.795 ;
     RECT  2.16 124.065 235.44 124.335 ;
     RECT  2.16 124.605 235.44 124.875 ;
     RECT  2.16 125.145 235.44 125.415 ;
     RECT  2.16 125.685 235.44 125.955 ;
     RECT  2.16 126.225 235.44 126.495 ;
     RECT  2.16 126.765 235.44 127.035 ;
     RECT  2.16 127.305 235.44 127.44 ;
    LAYER RVTP ;
     RECT  2.16 2.295 235.44 2.565 ;
     RECT  2.16 2.835 235.44 3.105 ;
     RECT  2.16 3.375 235.44 3.645 ;
     RECT  2.16 3.915 235.44 4.185 ;
     RECT  2.16 4.455 235.44 4.725 ;
     RECT  2.16 4.995 235.44 5.265 ;
     RECT  2.16 5.535 235.44 5.805 ;
     RECT  2.16 6.075 235.44 6.345 ;
     RECT  2.16 6.615 235.44 6.885 ;
     RECT  2.16 7.155 235.44 7.425 ;
     RECT  2.16 7.695 235.44 7.965 ;
     RECT  2.16 8.235 235.44 8.505 ;
     RECT  2.16 8.775 235.44 9.045 ;
     RECT  2.16 9.315 235.44 9.585 ;
     RECT  2.16 9.855 235.44 10.125 ;
     RECT  2.16 10.395 235.44 10.665 ;
     RECT  2.16 10.935 235.44 11.205 ;
     RECT  2.16 11.475 235.44 11.745 ;
     RECT  2.16 12.015 235.44 12.285 ;
     RECT  2.16 12.555 235.44 12.825 ;
     RECT  2.16 13.095 235.44 13.365 ;
     RECT  2.16 13.635 235.44 13.905 ;
     RECT  2.16 14.175 235.44 14.445 ;
     RECT  2.16 14.715 235.44 14.985 ;
     RECT  2.16 15.255 235.44 15.525 ;
     RECT  2.16 15.795 235.44 16.065 ;
     RECT  2.16 16.335 235.44 16.605 ;
     RECT  2.16 16.875 235.44 17.145 ;
     RECT  2.16 17.415 235.44 17.685 ;
     RECT  2.16 17.955 235.44 18.225 ;
     RECT  2.16 18.495 235.44 18.765 ;
     RECT  2.16 19.035 235.44 19.305 ;
     RECT  2.16 19.575 235.44 19.845 ;
     RECT  2.16 20.115 235.44 20.385 ;
     RECT  2.16 20.655 235.44 20.925 ;
     RECT  2.16 21.195 235.44 21.465 ;
     RECT  2.16 21.735 235.44 22.005 ;
     RECT  2.16 22.275 235.44 22.545 ;
     RECT  2.16 22.815 235.44 23.085 ;
     RECT  2.16 23.355 235.44 23.625 ;
     RECT  2.16 23.895 235.44 24.165 ;
     RECT  2.16 24.435 235.44 24.705 ;
     RECT  2.16 24.975 235.44 25.245 ;
     RECT  2.16 25.515 235.44 25.785 ;
     RECT  2.16 26.055 29.484 26.325 ;
     RECT  208.332 26.055 235.44 26.325 ;
     RECT  2.16 26.595 29.484 26.865 ;
     RECT  208.332 26.595 235.44 26.865 ;
     RECT  2.16 27.135 29.484 27.405 ;
     RECT  208.332 27.135 235.44 27.405 ;
     RECT  2.16 27.675 29.484 27.945 ;
     RECT  208.332 27.675 235.44 27.945 ;
     RECT  2.16 28.215 29.484 28.485 ;
     RECT  208.332 28.215 235.44 28.485 ;
     RECT  2.16 28.755 29.484 29.025 ;
     RECT  208.332 28.755 235.44 29.025 ;
     RECT  2.16 29.295 29.484 29.565 ;
     RECT  208.332 29.295 235.44 29.565 ;
     RECT  2.16 29.835 29.484 30.105 ;
     RECT  208.332 29.835 235.44 30.105 ;
     RECT  2.16 30.375 29.484 30.645 ;
     RECT  208.332 30.375 235.44 30.645 ;
     RECT  2.16 30.915 29.484 31.185 ;
     RECT  208.332 30.915 235.44 31.185 ;
     RECT  2.16 31.455 29.484 31.725 ;
     RECT  208.332 31.455 235.44 31.725 ;
     RECT  2.16 31.995 29.484 32.265 ;
     RECT  208.332 31.995 235.44 32.265 ;
     RECT  2.16 32.535 29.484 32.805 ;
     RECT  208.332 32.535 235.44 32.805 ;
     RECT  2.16 33.075 29.484 33.345 ;
     RECT  208.332 33.075 235.44 33.345 ;
     RECT  2.16 33.615 29.484 33.885 ;
     RECT  208.332 33.615 235.44 33.885 ;
     RECT  2.16 34.155 29.484 34.425 ;
     RECT  208.332 34.155 235.44 34.425 ;
     RECT  2.16 34.695 29.484 34.965 ;
     RECT  208.332 34.695 235.44 34.965 ;
     RECT  2.16 35.235 29.484 35.505 ;
     RECT  208.332 35.235 235.44 35.505 ;
     RECT  2.16 35.775 29.484 36.045 ;
     RECT  208.332 35.775 235.44 36.045 ;
     RECT  2.16 36.315 29.484 36.585 ;
     RECT  208.332 36.315 235.44 36.585 ;
     RECT  2.16 36.855 29.484 37.125 ;
     RECT  208.332 36.855 235.44 37.125 ;
     RECT  2.16 37.395 29.484 37.665 ;
     RECT  208.332 37.395 235.44 37.665 ;
     RECT  2.16 37.935 29.484 38.205 ;
     RECT  208.332 37.935 235.44 38.205 ;
     RECT  2.16 38.475 29.484 38.745 ;
     RECT  208.332 38.475 235.44 38.745 ;
     RECT  2.16 39.015 29.484 39.285 ;
     RECT  208.332 39.015 235.44 39.285 ;
     RECT  2.16 39.555 29.484 39.825 ;
     RECT  208.332 39.555 235.44 39.825 ;
     RECT  2.16 40.095 29.484 40.365 ;
     RECT  208.332 40.095 235.44 40.365 ;
     RECT  2.16 40.635 29.484 40.905 ;
     RECT  208.332 40.635 235.44 40.905 ;
     RECT  2.16 41.175 29.484 41.445 ;
     RECT  208.332 41.175 235.44 41.445 ;
     RECT  2.16 41.715 29.484 41.985 ;
     RECT  208.332 41.715 235.44 41.985 ;
     RECT  2.16 42.255 29.484 42.525 ;
     RECT  208.332 42.255 235.44 42.525 ;
     RECT  2.16 42.795 29.484 43.065 ;
     RECT  208.332 42.795 235.44 43.065 ;
     RECT  2.16 43.335 29.484 43.605 ;
     RECT  208.332 43.335 235.44 43.605 ;
     RECT  2.16 43.875 29.484 44.145 ;
     RECT  208.332 43.875 235.44 44.145 ;
     RECT  2.16 44.415 29.484 44.685 ;
     RECT  208.332 44.415 235.44 44.685 ;
     RECT  2.16 44.955 29.484 45.225 ;
     RECT  208.332 44.955 235.44 45.225 ;
     RECT  2.16 45.495 29.484 45.765 ;
     RECT  208.332 45.495 235.44 45.765 ;
     RECT  2.16 46.035 29.484 46.305 ;
     RECT  208.332 46.035 235.44 46.305 ;
     RECT  2.16 46.575 29.484 46.845 ;
     RECT  208.332 46.575 235.44 46.845 ;
     RECT  2.16 47.115 29.484 47.385 ;
     RECT  208.332 47.115 235.44 47.385 ;
     RECT  2.16 47.655 29.484 47.925 ;
     RECT  208.332 47.655 235.44 47.925 ;
     RECT  2.16 48.195 29.484 48.465 ;
     RECT  208.332 48.195 235.44 48.465 ;
     RECT  2.16 48.735 29.484 49.005 ;
     RECT  208.332 48.735 235.44 49.005 ;
     RECT  2.16 49.275 29.484 49.545 ;
     RECT  208.332 49.275 235.44 49.545 ;
     RECT  2.16 49.815 29.484 50.085 ;
     RECT  208.332 49.815 235.44 50.085 ;
     RECT  2.16 50.355 29.484 50.625 ;
     RECT  208.332 50.355 235.44 50.625 ;
     RECT  2.16 50.895 29.484 51.165 ;
     RECT  208.332 50.895 235.44 51.165 ;
     RECT  2.16 51.435 29.484 51.705 ;
     RECT  208.332 51.435 235.44 51.705 ;
     RECT  2.16 51.975 29.484 52.245 ;
     RECT  208.332 51.975 235.44 52.245 ;
     RECT  2.16 52.515 29.484 52.785 ;
     RECT  208.332 52.515 235.44 52.785 ;
     RECT  2.16 53.055 29.484 53.325 ;
     RECT  208.332 53.055 235.44 53.325 ;
     RECT  2.16 53.595 29.484 53.865 ;
     RECT  208.332 53.595 235.44 53.865 ;
     RECT  2.16 54.135 29.484 54.405 ;
     RECT  208.332 54.135 235.44 54.405 ;
     RECT  2.16 54.675 29.484 54.945 ;
     RECT  208.332 54.675 235.44 54.945 ;
     RECT  2.16 55.215 29.484 55.485 ;
     RECT  208.332 55.215 235.44 55.485 ;
     RECT  2.16 55.755 29.484 56.025 ;
     RECT  208.332 55.755 235.44 56.025 ;
     RECT  2.16 56.295 29.484 56.565 ;
     RECT  208.332 56.295 235.44 56.565 ;
     RECT  2.16 56.835 29.484 57.105 ;
     RECT  208.332 56.835 235.44 57.105 ;
     RECT  2.16 57.375 29.484 57.645 ;
     RECT  208.332 57.375 235.44 57.645 ;
     RECT  2.16 57.915 29.484 58.185 ;
     RECT  208.332 57.915 235.44 58.185 ;
     RECT  2.16 58.455 29.484 58.725 ;
     RECT  208.332 58.455 235.44 58.725 ;
     RECT  2.16 58.995 29.484 59.265 ;
     RECT  208.332 58.995 235.44 59.265 ;
     RECT  2.16 59.535 29.484 59.805 ;
     RECT  208.332 59.535 235.44 59.805 ;
     RECT  2.16 60.075 29.484 60.345 ;
     RECT  208.332 60.075 235.44 60.345 ;
     RECT  2.16 60.615 29.484 60.885 ;
     RECT  208.332 60.615 235.44 60.885 ;
     RECT  2.16 61.155 29.484 61.425 ;
     RECT  208.332 61.155 235.44 61.425 ;
     RECT  2.16 61.695 29.484 61.965 ;
     RECT  208.332 61.695 235.44 61.965 ;
     RECT  2.16 62.235 29.484 62.505 ;
     RECT  208.332 62.235 235.44 62.505 ;
     RECT  2.16 62.775 29.484 63.045 ;
     RECT  208.332 62.775 235.44 63.045 ;
     RECT  2.16 63.315 29.484 63.585 ;
     RECT  208.332 63.315 235.44 63.585 ;
     RECT  2.16 63.855 29.484 64.125 ;
     RECT  208.332 63.855 235.44 64.125 ;
     RECT  2.16 64.395 29.484 64.665 ;
     RECT  208.332 64.395 235.44 64.665 ;
     RECT  2.16 64.935 29.484 65.205 ;
     RECT  208.332 64.935 235.44 65.205 ;
     RECT  2.16 65.475 29.484 65.745 ;
     RECT  208.332 65.475 235.44 65.745 ;
     RECT  2.16 66.015 29.484 66.285 ;
     RECT  208.332 66.015 235.44 66.285 ;
     RECT  2.16 66.555 29.484 66.825 ;
     RECT  208.332 66.555 235.44 66.825 ;
     RECT  2.16 67.095 29.484 67.365 ;
     RECT  208.332 67.095 235.44 67.365 ;
     RECT  2.16 67.635 29.484 67.905 ;
     RECT  208.332 67.635 235.44 67.905 ;
     RECT  2.16 68.175 29.484 68.445 ;
     RECT  208.332 68.175 235.44 68.445 ;
     RECT  2.16 68.715 29.484 68.985 ;
     RECT  208.332 68.715 235.44 68.985 ;
     RECT  2.16 69.255 29.484 69.525 ;
     RECT  208.332 69.255 235.44 69.525 ;
     RECT  2.16 69.795 29.484 70.065 ;
     RECT  208.332 69.795 235.44 70.065 ;
     RECT  2.16 70.335 29.484 70.605 ;
     RECT  208.332 70.335 235.44 70.605 ;
     RECT  2.16 70.875 29.484 71.145 ;
     RECT  208.332 70.875 235.44 71.145 ;
     RECT  2.16 71.415 29.484 71.685 ;
     RECT  208.332 71.415 235.44 71.685 ;
     RECT  2.16 71.955 29.484 72.225 ;
     RECT  208.332 71.955 235.44 72.225 ;
     RECT  2.16 72.495 29.484 72.765 ;
     RECT  208.332 72.495 235.44 72.765 ;
     RECT  2.16 73.035 29.484 73.305 ;
     RECT  208.332 73.035 235.44 73.305 ;
     RECT  2.16 73.575 29.484 73.845 ;
     RECT  208.332 73.575 235.44 73.845 ;
     RECT  2.16 74.115 29.484 74.385 ;
     RECT  208.332 74.115 235.44 74.385 ;
     RECT  2.16 74.655 29.484 74.925 ;
     RECT  208.332 74.655 235.44 74.925 ;
     RECT  2.16 75.195 29.484 75.465 ;
     RECT  208.332 75.195 235.44 75.465 ;
     RECT  2.16 75.735 29.484 76.005 ;
     RECT  208.332 75.735 235.44 76.005 ;
     RECT  2.16 76.275 29.484 76.545 ;
     RECT  208.332 76.275 235.44 76.545 ;
     RECT  2.16 76.815 29.484 77.085 ;
     RECT  208.332 76.815 235.44 77.085 ;
     RECT  2.16 77.355 29.484 77.625 ;
     RECT  208.332 77.355 235.44 77.625 ;
     RECT  2.16 77.895 29.484 78.165 ;
     RECT  208.332 77.895 235.44 78.165 ;
     RECT  2.16 78.435 29.484 78.705 ;
     RECT  208.332 78.435 235.44 78.705 ;
     RECT  2.16 78.975 29.484 79.245 ;
     RECT  208.332 78.975 235.44 79.245 ;
     RECT  2.16 79.515 29.484 79.785 ;
     RECT  208.332 79.515 235.44 79.785 ;
     RECT  2.16 80.055 29.484 80.325 ;
     RECT  208.332 80.055 235.44 80.325 ;
     RECT  2.16 80.595 29.484 80.865 ;
     RECT  208.332 80.595 235.44 80.865 ;
     RECT  2.16 81.135 29.484 81.405 ;
     RECT  208.332 81.135 235.44 81.405 ;
     RECT  2.16 81.675 29.484 81.945 ;
     RECT  208.332 81.675 235.44 81.945 ;
     RECT  2.16 82.215 29.484 82.485 ;
     RECT  208.332 82.215 235.44 82.485 ;
     RECT  2.16 82.755 29.484 83.025 ;
     RECT  208.332 82.755 235.44 83.025 ;
     RECT  2.16 83.295 29.484 83.565 ;
     RECT  208.332 83.295 235.44 83.565 ;
     RECT  2.16 83.835 29.484 84.105 ;
     RECT  208.332 83.835 235.44 84.105 ;
     RECT  2.16 84.375 29.484 84.645 ;
     RECT  208.332 84.375 235.44 84.645 ;
     RECT  2.16 84.915 29.484 85.185 ;
     RECT  208.332 84.915 235.44 85.185 ;
     RECT  2.16 85.455 29.484 85.725 ;
     RECT  208.332 85.455 235.44 85.725 ;
     RECT  2.16 85.995 29.484 86.265 ;
     RECT  208.332 85.995 235.44 86.265 ;
     RECT  2.16 86.535 29.484 86.805 ;
     RECT  208.332 86.535 235.44 86.805 ;
     RECT  2.16 87.075 29.484 87.345 ;
     RECT  208.332 87.075 235.44 87.345 ;
     RECT  2.16 87.615 29.484 87.885 ;
     RECT  208.332 87.615 235.44 87.885 ;
     RECT  2.16 88.155 29.484 88.425 ;
     RECT  208.332 88.155 235.44 88.425 ;
     RECT  2.16 88.695 29.484 88.965 ;
     RECT  208.332 88.695 235.44 88.965 ;
     RECT  2.16 89.235 29.484 89.505 ;
     RECT  208.332 89.235 235.44 89.505 ;
     RECT  2.16 89.775 29.484 90.045 ;
     RECT  208.332 89.775 235.44 90.045 ;
     RECT  2.16 90.315 29.484 90.585 ;
     RECT  208.332 90.315 235.44 90.585 ;
     RECT  2.16 90.855 29.484 91.125 ;
     RECT  208.332 90.855 235.44 91.125 ;
     RECT  2.16 91.395 29.484 91.665 ;
     RECT  208.332 91.395 235.44 91.665 ;
     RECT  2.16 91.935 29.484 92.205 ;
     RECT  208.332 91.935 235.44 92.205 ;
     RECT  2.16 92.475 29.484 92.745 ;
     RECT  208.332 92.475 235.44 92.745 ;
     RECT  2.16 93.015 29.484 93.285 ;
     RECT  208.332 93.015 235.44 93.285 ;
     RECT  2.16 93.555 29.484 93.825 ;
     RECT  208.332 93.555 235.44 93.825 ;
     RECT  2.16 94.095 29.484 94.365 ;
     RECT  208.332 94.095 235.44 94.365 ;
     RECT  2.16 94.635 29.484 94.905 ;
     RECT  208.332 94.635 235.44 94.905 ;
     RECT  2.16 95.175 29.484 95.445 ;
     RECT  208.332 95.175 235.44 95.445 ;
     RECT  2.16 95.715 29.484 95.985 ;
     RECT  208.332 95.715 235.44 95.985 ;
     RECT  2.16 96.255 29.484 96.525 ;
     RECT  208.332 96.255 235.44 96.525 ;
     RECT  2.16 96.795 29.484 97.065 ;
     RECT  208.332 96.795 235.44 97.065 ;
     RECT  2.16 97.335 29.484 97.605 ;
     RECT  208.332 97.335 235.44 97.605 ;
     RECT  2.16 97.875 29.484 98.145 ;
     RECT  208.332 97.875 235.44 98.145 ;
     RECT  2.16 98.415 29.484 98.685 ;
     RECT  208.332 98.415 235.44 98.685 ;
     RECT  2.16 98.955 29.484 99.225 ;
     RECT  208.332 98.955 235.44 99.225 ;
     RECT  2.16 99.495 29.484 99.765 ;
     RECT  208.332 99.495 235.44 99.765 ;
     RECT  2.16 100.035 29.484 100.305 ;
     RECT  208.332 100.035 235.44 100.305 ;
     RECT  2.16 100.575 29.484 100.71 ;
     RECT  208.332 100.575 235.44 100.71 ;
     RECT  2.16 100.71 235.44 100.845 ;
     RECT  2.16 101.115 235.44 101.385 ;
     RECT  2.16 101.655 235.44 101.925 ;
     RECT  2.16 102.195 235.44 102.465 ;
     RECT  2.16 102.735 235.44 103.005 ;
     RECT  2.16 103.275 235.44 103.545 ;
     RECT  2.16 103.815 235.44 104.085 ;
     RECT  2.16 104.355 235.44 104.625 ;
     RECT  2.16 104.895 235.44 105.165 ;
     RECT  2.16 105.435 235.44 105.705 ;
     RECT  2.16 105.975 235.44 106.245 ;
     RECT  2.16 106.515 235.44 106.785 ;
     RECT  2.16 107.055 235.44 107.325 ;
     RECT  2.16 107.595 235.44 107.865 ;
     RECT  2.16 108.135 235.44 108.405 ;
     RECT  2.16 108.675 235.44 108.945 ;
     RECT  2.16 109.215 235.44 109.485 ;
     RECT  2.16 109.755 235.44 110.025 ;
     RECT  2.16 110.295 235.44 110.565 ;
     RECT  2.16 110.835 235.44 111.105 ;
     RECT  2.16 111.375 235.44 111.645 ;
     RECT  2.16 111.915 235.44 112.185 ;
     RECT  2.16 112.455 235.44 112.725 ;
     RECT  2.16 112.995 235.44 113.265 ;
     RECT  2.16 113.535 235.44 113.805 ;
     RECT  2.16 114.075 235.44 114.345 ;
     RECT  2.16 114.615 235.44 114.885 ;
     RECT  2.16 115.155 235.44 115.425 ;
     RECT  2.16 115.695 235.44 115.965 ;
     RECT  2.16 116.235 235.44 116.505 ;
     RECT  2.16 116.775 235.44 117.045 ;
     RECT  2.16 117.315 235.44 117.585 ;
     RECT  2.16 117.855 235.44 118.125 ;
     RECT  2.16 118.395 235.44 118.665 ;
     RECT  2.16 118.935 235.44 119.205 ;
     RECT  2.16 119.475 235.44 119.745 ;
     RECT  2.16 120.015 235.44 120.285 ;
     RECT  2.16 120.555 235.44 120.825 ;
     RECT  2.16 121.095 235.44 121.365 ;
     RECT  2.16 121.635 235.44 121.905 ;
     RECT  2.16 122.175 235.44 122.445 ;
     RECT  2.16 122.715 235.44 122.985 ;
     RECT  2.16 123.255 235.44 123.525 ;
     RECT  2.16 123.795 235.44 124.065 ;
     RECT  2.16 124.335 235.44 124.605 ;
     RECT  2.16 124.875 235.44 125.145 ;
     RECT  2.16 125.415 235.44 125.685 ;
     RECT  2.16 125.955 235.44 126.225 ;
     RECT  2.16 126.495 235.44 126.765 ;
     RECT  2.16 127.035 235.44 127.305 ;
    LAYER M1 ;
     RECT  2.16 2.151 235.44 25.929 ;
     RECT  31.536 28.08 206.28 98.55 ;
     RECT  2.16 25.929 29.484 100.701 ;
     RECT  208.332 25.929 235.44 100.701 ;
     RECT  2.16 100.701 235.44 127.449 ;
    LAYER M2 ;
     RECT  0.103 4.122 2.16 4.14 ;
     RECT  1.723 6.822 2.16 6.84 ;
     RECT  0.103 15.192 2.16 15.21 ;
     RECT  0.103 17.892 2.16 17.91 ;
     RECT  0.103 20.862 2.16 20.88 ;
     RECT  0.103 23.562 2.16 23.58 ;
     RECT  0.103 26.262 2.16 26.28 ;
     RECT  0.103 28.962 2.16 28.98 ;
     RECT  0.103 31.662 2.16 31.68 ;
     RECT  0.103 34.632 2.16 34.65 ;
     RECT  0.103 37.332 2.16 37.35 ;
     RECT  0.103 40.032 2.16 40.05 ;
     RECT  0.103 42.732 2.16 42.75 ;
     RECT  0.103 48.24 2.16 48.258 ;
     RECT  0.103 51.102 2.16 51.12 ;
     RECT  0.103 53.802 2.16 53.82 ;
     RECT  1.723 56.34 2.16 56.358 ;
     RECT  0.103 59.472 2.16 59.49 ;
     RECT  0.103 64.872 2.16 64.89 ;
     RECT  0.103 67.572 2.16 67.59 ;
     RECT  0.103 70.308 2.16 70.326 ;
     RECT  0.103 73.242 2.16 73.26 ;
     RECT  0.103 75.942 2.16 75.96 ;
     RECT  0.103 78.642 2.16 78.66 ;
     RECT  0.103 81.342 2.16 81.36 ;
     RECT  0.103 84.312 2.16 84.33 ;
     RECT  0.103 87.012 2.16 87.03 ;
     RECT  0.103 89.712 2.16 89.73 ;
     RECT  0.103 92.412 2.16 92.43 ;
     RECT  0.103 95.148 2.16 95.166 ;
     RECT  0.103 100.782 2.16 100.8 ;
     RECT  0.103 103.482 2.16 103.5 ;
     RECT  0.103 106.182 2.16 106.2 ;
     RECT  0.103 108.918 2.16 108.936 ;
     RECT  0.103 114.552 2.16 114.57 ;
     RECT  0.103 117.252 2.16 117.27 ;
     RECT  0.103 119.952 2.16 119.97 ;
     RECT  0.535 122.652 2.16 122.67 ;
     RECT  0.103 125.622 2.16 125.64 ;
     RECT  0.103 127.08 2.16 127.098 ;
     RECT  2.16 2.151 29.484 127.449 ;
     RECT  29.484 2.151 29.52 28.629 ;
     RECT  29.484 63.171 29.52 63.189 ;
     RECT  29.484 67.068 29.52 127.449 ;
     RECT  29.484 42.732 29.687 52.344 ;
     RECT  29.484 31.806 29.723 41.976 ;
     RECT  29.484 53.496 29.975 58.914 ;
     RECT  29.687 42.732 30.011 52.272 ;
     RECT  29.723 34.776 30.191 41.976 ;
     RECT  29.484 60.66 30.191 62.334 ;
     RECT  30.191 34.776 30.227 38.304 ;
     RECT  30.191 39.294 30.227 41.976 ;
     RECT  30.011 43.002 30.227 52.272 ;
     RECT  30.191 60.66 30.227 61.686 ;
     RECT  29.484 64.062 30.227 65.16 ;
     RECT  29.52 67.068 30.343 69.444 ;
     RECT  30.343 66.636 30.415 69.444 ;
     RECT  29.723 31.806 30.443 33.948 ;
     RECT  29.52 70.308 30.479 70.704 ;
     RECT  30.343 62.712 30.487 62.874 ;
     RECT  30.227 34.776 30.515 38.268 ;
     RECT  29.975 53.568 30.515 58.914 ;
     RECT  30.415 66.456 30.515 69.444 ;
     RECT  30.515 66.456 30.551 69.354 ;
     RECT  30.487 62.712 30.623 63.072 ;
     RECT  30.551 66.564 30.623 69.354 ;
     RECT  30.227 64.17 30.731 65.16 ;
     RECT  29.484 29.736 30.767 29.754 ;
     RECT  29.484 30.546 30.767 30.564 ;
     RECT  30.515 34.866 30.767 38.268 ;
     RECT  30.227 44.046 30.767 52.272 ;
     RECT  30.515 54.108 30.767 58.914 ;
     RECT  30.227 60.966 30.767 61.686 ;
     RECT  30.731 64.17 30.767 64.998 ;
     RECT  29.52 2.151 30.803 28.314 ;
     RECT  30.227 39.33 30.803 41.976 ;
     RECT  30.767 44.046 30.803 47.988 ;
     RECT  30.623 66.564 30.803 68.544 ;
     RECT  30.479 70.686 30.803 70.704 ;
     RECT  30.767 60.966 31.099 60.984 ;
     RECT  30.803 2.151 31.536 28.242 ;
     RECT  30.443 31.806 31.536 31.824 ;
     RECT  30.443 32.706 31.536 33.948 ;
     RECT  30.767 35.01 31.536 38.268 ;
     RECT  30.803 39.33 31.536 39.348 ;
     RECT  30.803 40.176 31.536 40.194 ;
     RECT  30.803 41.112 31.536 41.976 ;
     RECT  30.227 43.002 31.536 43.02 ;
     RECT  30.803 44.226 31.536 47.988 ;
     RECT  30.767 48.978 31.536 52.272 ;
     RECT  30.767 54.108 31.536 58.644 ;
     RECT  31.099 60.894 31.536 60.984 ;
     RECT  30.623 62.712 31.536 62.874 ;
     RECT  30.767 64.98 31.536 64.998 ;
     RECT  30.803 66.564 31.536 66.654 ;
     RECT  30.803 67.716 31.536 68.544 ;
     RECT  30.623 69.336 31.536 69.354 ;
     RECT  29.52 99.468 91.787 127.449 ;
     RECT  91.787 100.62 105.827 127.449 ;
     RECT  31.536 2.151 106.555 98.55 ;
     RECT  91.787 99.468 106.555 99.486 ;
     RECT  106.555 2.151 112.091 99.486 ;
     RECT  112.091 2.151 112.819 98.874 ;
     RECT  112.819 2.151 206.28 99.486 ;
     RECT  206.28 2.151 206.375 28.044 ;
     RECT  206.28 29.034 206.411 29.124 ;
     RECT  206.28 33.048 206.483 33.219 ;
     RECT  206.375 2.151 206.519 27.864 ;
     RECT  206.519 27.072 206.555 27.864 ;
     RECT  206.28 31.356 206.663 32.22 ;
     RECT  206.483 33.12 206.663 33.219 ;
     RECT  206.28 35.406 206.663 36 ;
     RECT  206.663 35.406 206.735 35.694 ;
     RECT  206.555 27.072 206.771 27.819 ;
     RECT  206.771 27.072 206.807 27.702 ;
     RECT  206.663 32.202 206.807 32.22 ;
     RECT  206.28 30.114 206.843 30.204 ;
     RECT  206.807 27.072 206.879 27.234 ;
     RECT  206.843 30.186 206.879 30.204 ;
     RECT  206.411 29.034 206.987 29.052 ;
     RECT  206.28 34.092 206.987 34.614 ;
     RECT  206.28 37.134 207.023 37.152 ;
     RECT  206.28 45.162 207.175 45.18 ;
     RECT  206.28 38.646 207.211 39.24 ;
     RECT  206.879 27.072 207.239 27.09 ;
     RECT  206.987 34.596 207.247 34.614 ;
     RECT  207.211 38.142 207.247 39.24 ;
     RECT  206.28 42.156 207.427 42.624 ;
     RECT  206.28 48.708 207.427 48.96 ;
     RECT  207.247 38.142 207.463 39.546 ;
     RECT  207.427 42.156 207.463 42.714 ;
     RECT  207.427 48.402 207.463 48.96 ;
     RECT  206.28 58.122 207.463 58.14 ;
     RECT  206.28 60.966 207.463 60.984 ;
     RECT  206.28 63.756 207.463 64.224 ;
     RECT  207.463 38.106 207.499 39.888 ;
     RECT  207.175 45.162 207.499 45.558 ;
     RECT  207.463 48.24 207.499 48.96 ;
     RECT  207.463 52.326 207.499 52.344 ;
     RECT  206.28 54.576 207.499 55.278 ;
     RECT  207.463 60.966 207.499 61.524 ;
     RECT  207.463 63.756 207.499 65.466 ;
     RECT  206.28 68.382 207.499 68.4 ;
     RECT  207.499 63.756 208.003 66.24 ;
     RECT  207.499 66.996 208.003 67.32 ;
     RECT  207.499 68.076 208.003 68.4 ;
     RECT  207.499 48.24 208.039 49.5 ;
     RECT  207.499 54.576 208.327 55.44 ;
     RECT  206.519 2.151 208.332 26.244 ;
     RECT  207.067 28.764 208.332 28.782 ;
     RECT  208.039 29.88 208.332 29.898 ;
     RECT  206.663 31.356 208.332 31.374 ;
     RECT  207.247 34.596 208.332 35.064 ;
     RECT  207.499 36.522 208.332 36.54 ;
     RECT  207.499 37.296 208.332 37.314 ;
     RECT  207.499 38.106 208.332 40.32 ;
     RECT  207.427 41.076 208.332 41.094 ;
     RECT  207.463 42.066 208.332 43.326 ;
     RECT  207.499 45.162 208.332 45.72 ;
     RECT  208.039 47.736 208.332 49.5 ;
     RECT  208.291 50.526 208.332 50.544 ;
     RECT  207.499 52.02 208.332 52.434 ;
     RECT  208.327 54.576 208.332 55.584 ;
     RECT  207.463 57.996 208.332 58.716 ;
     RECT  207.499 60.966 208.332 61.92 ;
     RECT  208.003 63.756 208.332 68.4 ;
     RECT  206.28 98.856 208.332 99.486 ;
     RECT  105.827 100.701 208.332 127.449 ;
     RECT  208.332 2.151 235.44 127.449 ;
     RECT  235.44 10.206 236.003 10.224 ;
     RECT  235.44 16.956 236.003 16.974 ;
     RECT  235.44 23.706 236.003 23.724 ;
     RECT  235.44 64.746 236.003 64.764 ;
     RECT  235.44 78.516 236.363 78.534 ;
     RECT  235.44 30.69 236.543 30.708 ;
     RECT  235.44 37.476 236.543 37.494 ;
     RECT  235.44 44.226 236.543 44.244 ;
     RECT  235.44 51.174 236.543 51.192 ;
     RECT  235.44 71.496 236.543 71.514 ;
     RECT  235.44 85.266 236.543 85.284 ;
     RECT  235.44 92.016 236.543 92.034 ;
     RECT  235.44 105.714 236.543 105.732 ;
     RECT  235.44 112.5 236.543 112.518 ;
     RECT  235.44 98.586 236.579 98.604 ;
     RECT  235.44 3.384 237.515 3.402 ;
     RECT  235.44 57.546 237.515 57.564 ;
     RECT  235.44 119.106 237.515 119.124 ;
     RECT  235.44 125.928 237.515 125.946 ;
    LAYER M3 ;
     RECT  3.276 1.339 3.294 2.255 ;
     RECT  4.68 2.263 4.698 2.371 ;
     RECT  2.415 2.143 2.505 2.413 ;
     RECT  7.815 2.143 7.905 2.413 ;
     RECT  13.215 2.143 13.305 2.413 ;
     RECT  18.615 2.143 18.705 2.413 ;
     RECT  24.015 2.143 24.105 2.413 ;
     RECT  29.415 2.143 29.505 2.413 ;
     RECT  34.815 2.143 34.905 2.413 ;
     RECT  40.215 2.143 40.305 2.413 ;
     RECT  45.615 2.143 45.705 2.413 ;
     RECT  51.015 2.143 51.105 2.413 ;
     RECT  56.415 2.143 56.505 2.413 ;
     RECT  61.815 2.143 61.905 2.413 ;
     RECT  67.215 2.143 67.305 2.413 ;
     RECT  72.615 2.143 72.705 2.413 ;
     RECT  78.015 2.143 78.105 2.413 ;
     RECT  83.415 2.143 83.505 2.413 ;
     RECT  88.815 2.143 88.905 2.413 ;
     RECT  94.215 2.143 94.305 2.413 ;
     RECT  99.615 2.143 99.705 2.413 ;
     RECT  105.015 2.143 105.105 2.413 ;
     RECT  110.415 2.143 110.505 2.413 ;
     RECT  115.815 2.143 115.905 2.413 ;
     RECT  121.215 2.143 121.305 2.413 ;
     RECT  126.615 2.143 126.705 2.413 ;
     RECT  132.015 2.143 132.105 2.413 ;
     RECT  137.415 2.143 137.505 2.413 ;
     RECT  142.815 2.143 142.905 2.413 ;
     RECT  148.215 2.143 148.305 2.413 ;
     RECT  153.615 2.143 153.705 2.413 ;
     RECT  159.015 2.143 159.105 2.413 ;
     RECT  164.415 2.143 164.505 2.413 ;
     RECT  169.815 2.143 169.905 2.413 ;
     RECT  175.215 2.143 175.305 2.413 ;
     RECT  180.615 2.143 180.705 2.413 ;
     RECT  186.015 2.143 186.105 2.413 ;
     RECT  191.415 2.143 191.505 2.413 ;
     RECT  196.815 2.143 196.905 2.413 ;
     RECT  202.215 2.143 202.305 2.413 ;
     RECT  207.615 2.143 207.705 2.413 ;
     RECT  213.015 2.143 213.105 2.413 ;
     RECT  218.415 2.143 218.505 2.413 ;
     RECT  223.815 2.143 223.905 2.413 ;
     RECT  229.215 2.143 229.305 2.413 ;
     RECT  234.615 2.143 234.705 2.413 ;
     RECT  4.14 2.371 4.698 2.461 ;
     RECT  3.996 2.461 4.698 2.525 ;
     RECT  4.932 2.533 4.95 2.641 ;
     RECT  4.932 2.641 5.274 2.731 ;
     RECT  4.932 2.731 5.814 2.759 ;
     RECT  234.615 2.413 234.897 3.271 ;
     RECT  234.615 3.271 235.098 3.371 ;
     RECT  234.615 3.371 234.897 3.415 ;
     RECT  237.492 3.379 237.51 3.437 ;
     RECT  234.288 3.415 234.897 3.569 ;
     RECT  232.38 3.685 232.398 3.721 ;
     RECT  233.28 3.685 233.298 3.721 ;
     RECT  229.215 2.413 229.497 3.811 ;
     RECT  233.28 3.721 233.694 3.839 ;
     RECT  232.38 3.721 232.506 3.955 ;
     RECT  233.28 3.839 233.298 3.955 ;
     RECT  232.38 3.955 233.298 3.983 ;
     RECT  125.604 3.919 125.622 4.109 ;
     RECT  7.815 2.413 8.097 4.117 ;
     RECT  0.108 4.117 0.126 4.157 ;
     RECT  5.256 2.759 5.814 4.189 ;
     RECT  4.824 4.189 5.814 4.261 ;
     RECT  7.38 4.117 8.097 4.351 ;
     RECT  232.38 3.983 232.578 4.411 ;
     RECT  4.824 4.261 6.138 4.415 ;
     RECT  231.984 4.411 232.578 4.451 ;
     RECT  4.824 4.415 5.274 4.541 ;
     RECT  232.38 4.451 232.578 4.649 ;
     RECT  232.38 4.649 232.398 4.685 ;
     RECT  7.344 4.351 8.097 6.781 ;
     RECT  6.12 4.415 6.138 6.808 ;
     RECT  2.415 2.413 2.697 6.817 ;
     RECT  7.344 6.781 8.622 6.817 ;
     RECT  6.12 6.808 6.426 6.845 ;
     RECT  1.728 6.817 2.697 6.893 ;
     RECT  7.272 6.817 8.622 7.115 ;
     RECT  7.344 7.115 8.622 7.421 ;
     RECT  2.415 6.893 2.697 9.643 ;
     RECT  2.304 9.643 2.697 9.815 ;
     RECT  5.256 4.541 5.274 9.859 ;
     RECT  6.12 6.845 6.138 9.859 ;
     RECT  7.416 7.421 8.622 9.895 ;
     RECT  7.416 9.895 8.874 9.931 ;
     RECT  235.98 10.201 235.998 10.253 ;
     RECT  233.856 10.165 233.874 10.589 ;
     RECT  2.415 9.815 2.697 12.379 ;
     RECT  5.256 9.859 6.138 12.451 ;
     RECT  4.536 12.451 6.138 12.517 ;
     RECT  4.5 12.517 6.138 12.557 ;
     RECT  4.536 12.557 6.138 12.749 ;
     RECT  2.304 12.379 2.697 12.785 ;
     RECT  228.6 3.811 229.497 13.019 ;
     RECT  5.256 12.749 6.138 15.211 ;
     RECT  0.108 15.163 0.126 15.215 ;
     RECT  4.824 15.211 6.138 15.251 ;
     RECT  5.256 15.251 6.138 15.331 ;
     RECT  7.416 9.931 9.306 15.719 ;
     RECT  5.256 15.331 6.174 15.871 ;
     RECT  234.615 3.569 234.897 16.681 ;
     RECT  234.432 16.681 234.954 16.835 ;
     RECT  234.432 16.835 234.897 16.915 ;
     RECT  235.98 16.951 235.998 17.069 ;
     RECT  143.928 10.561 143.946 17.581 ;
     RECT  234.288 16.915 234.897 17.609 ;
     RECT  5.256 15.871 6.894 17.761 ;
     RECT  7.815 15.719 9.306 17.761 ;
     RECT  0.108 17.887 0.126 17.933 ;
     RECT  5.256 17.761 9.306 18.059 ;
     RECT  106.884 12.991 106.902 18.689 ;
     RECT  6.948 18.059 9.306 18.725 ;
     RECT  18.615 2.413 18.897 18.769 ;
     RECT  5.256 18.059 6.174 18.995 ;
     RECT  5.256 18.995 6.138 19.535 ;
     RECT  6.948 18.725 8.622 20.731 ;
     RECT  73.62 18.697 73.638 20.849 ;
     RECT  0.108 20.683 0.126 20.885 ;
     RECT  6.948 20.731 8.766 20.885 ;
     RECT  72.615 2.413 72.897 20.965 ;
     RECT  6.948 20.885 8.622 21.155 ;
     RECT  16.92 19.111 16.938 21.271 ;
     RECT  16.92 21.271 17.586 22.199 ;
     RECT  143.928 17.581 144.486 22.199 ;
     RECT  10.836 21.001 10.854 22.235 ;
     RECT  7.815 21.155 8.622 22.513 ;
     RECT  72.615 20.965 73.386 22.541 ;
     RECT  15.408 22.171 15.426 23.045 ;
     RECT  152.244 22.795 152.262 23.279 ;
     RECT  49.716 23.251 50.022 23.309 ;
     RECT  150.696 23.251 150.714 23.309 ;
     RECT  49.716 23.309 49.734 23.357 ;
     RECT  0.108 23.419 0.126 23.585 ;
     RECT  5.256 19.535 5.274 23.665 ;
     RECT  234.615 17.609 234.897 23.665 ;
     RECT  2.415 12.785 2.697 23.701 ;
     RECT  2.415 23.701 3.006 23.819 ;
     RECT  234.615 23.665 235.062 23.819 ;
     RECT  235.98 23.701 235.998 23.885 ;
     RECT  4.644 23.665 5.274 23.899 ;
     RECT  6.12 19.535 6.138 23.899 ;
     RECT  4.644 23.899 6.138 23.935 ;
     RECT  234.615 23.819 234.897 23.935 ;
     RECT  3.924 23.935 6.138 23.963 ;
     RECT  27.396 22.207 27.414 23.971 ;
     RECT  3.924 23.963 3.942 23.981 ;
     RECT  17.568 22.199 17.586 23.999 ;
     RECT  27.036 23.971 27.414 24.089 ;
     RECT  234.216 23.935 234.897 24.089 ;
     RECT  28.584 19.471 28.602 24.241 ;
     RECT  29.415 2.413 29.697 24.241 ;
     RECT  5.184 23.963 6.138 24.665 ;
     RECT  5.256 24.665 6.138 24.781 ;
     RECT  6.948 21.155 6.966 24.781 ;
     RECT  7.815 22.513 8.658 24.781 ;
     RECT  25.668 22.981 25.686 24.899 ;
     RECT  143.928 22.199 143.946 24.899 ;
     RECT  27.396 24.089 27.414 24.907 ;
     RECT  94.215 2.413 94.497 24.907 ;
     RECT  97.344 24.871 97.362 24.941 ;
     RECT  26.856 24.907 27.414 24.943 ;
     RECT  98.46 24.907 98.55 24.944 ;
     RECT  22.824 24.907 22.842 25.007 ;
     RECT  94.215 24.907 94.662 25.007 ;
     RECT  6.948 24.781 8.658 25.051 ;
     RECT  98.532 24.944 98.55 25.051 ;
     RECT  207.615 2.413 207.897 25.051 ;
     RECT  26.784 24.943 27.414 25.079 ;
     RECT  126.615 2.413 126.897 25.141 ;
     RECT  110.415 2.413 110.697 25.147 ;
     RECT  126.18 25.141 127.314 25.181 ;
     RECT  5.256 24.781 6.21 25.321 ;
     RECT  6.948 25.051 8.874 25.321 ;
     RECT  40.215 2.413 40.497 25.321 ;
     RECT  105.015 2.413 105.297 25.321 ;
     RECT  95.508 25.321 95.526 25.411 ;
     RECT  102.6 25.321 102.618 25.411 ;
     RECT  105.015 25.321 105.642 25.411 ;
     RECT  95.364 25.411 95.526 25.439 ;
     RECT  92.772 25.411 92.79 25.447 ;
     RECT  87.876 25.435 87.894 25.475 ;
     RECT  95.364 25.439 95.382 25.517 ;
     RECT  83.415 2.413 83.697 25.519 ;
     RECT  31.068 25.483 31.086 25.531 ;
     RECT  102.6 25.411 102.762 25.547 ;
     RECT  28.584 24.241 29.697 25.555 ;
     RECT  132.015 2.413 132.297 25.555 ;
     RECT  92.52 25.447 92.79 25.565 ;
     RECT  105.015 25.411 105.678 25.579 ;
     RECT  104.328 25.579 105.678 25.583 ;
     RECT  5.256 25.321 8.874 25.591 ;
     RECT  61.815 2.413 62.097 25.591 ;
     RECT  102.672 25.547 102.762 25.619 ;
     RECT  104.328 25.583 105.57 25.619 ;
     RECT  34.815 2.413 35.097 25.667 ;
     RECT  40.215 25.321 41.058 25.667 ;
     RECT  45.615 2.413 45.897 25.667 ;
     RECT  51.015 2.413 51.297 25.667 ;
     RECT  67.215 2.413 67.497 25.667 ;
     RECT  72.615 22.541 72.897 25.667 ;
     RECT  83.232 25.519 83.697 25.667 ;
     RECT  88.815 2.413 89.097 25.667 ;
     RECT  99.615 2.413 99.897 25.667 ;
     RECT  115.815 2.413 116.097 25.667 ;
     RECT  121.215 2.413 121.497 25.667 ;
     RECT  126.54 25.181 126.897 25.667 ;
     RECT  137.415 2.413 137.697 25.667 ;
     RECT  153.615 2.413 153.897 25.667 ;
     RECT  159.015 2.413 159.297 25.667 ;
     RECT  164.415 2.413 164.697 25.667 ;
     RECT  169.815 2.413 170.097 25.667 ;
     RECT  175.215 2.413 175.497 25.667 ;
     RECT  180.615 2.413 180.897 25.667 ;
     RECT  186.015 2.413 186.297 25.667 ;
     RECT  191.415 2.413 191.697 25.667 ;
     RECT  196.815 2.413 197.097 25.667 ;
     RECT  202.215 2.413 202.497 25.667 ;
     RECT  207.18 25.051 207.897 25.667 ;
     RECT  78.015 2.413 78.297 25.681 ;
     RECT  79.02 25.015 79.038 25.681 ;
     RECT  88.815 25.667 89.082 25.681 ;
     RECT  173.196 25.591 173.214 25.681 ;
     RECT  178.704 25.015 178.722 25.681 ;
     RECT  186.015 25.667 186.105 25.681 ;
     RECT  61.668 25.591 62.097 25.709 ;
     RECT  62.928 22.171 62.946 25.709 ;
     RECT  65.52 25.672 65.538 25.709 ;
     RECT  78.015 25.681 79.038 25.709 ;
     RECT  83.232 25.667 83.505 25.709 ;
     RECT  110.415 25.147 110.79 25.709 ;
     RECT  141.66 24.061 141.678 25.709 ;
     RECT  60.048 25.681 60.066 25.717 ;
     RECT  61.815 25.709 62.097 25.717 ;
     RECT  79.956 25.681 79.974 25.717 ;
     RECT  90.504 25.681 90.522 25.717 ;
     RECT  94.215 25.007 94.626 25.717 ;
     RECT  98.532 25.051 98.586 25.717 ;
     RECT  132.015 25.555 132.354 25.717 ;
     RECT  145.368 25.447 145.386 25.717 ;
     RECT  27.396 25.079 27.414 25.745 ;
     RECT  173.196 25.681 173.466 25.745 ;
     RECT  178.704 25.681 178.974 25.745 ;
     RECT  74.664 25.681 74.682 25.753 ;
     RECT  97.884 25.717 98.586 25.753 ;
     RECT  129.312 25.681 129.33 25.753 ;
     RECT  182.412 25.681 182.43 25.753 ;
     RECT  185.832 25.681 186.105 25.753 ;
     RECT  87.12 25.717 87.138 25.757 ;
     RECT  88.236 25.681 89.082 25.757 ;
     RECT  148.215 2.413 148.497 25.771 ;
     RECT  156.204 25.519 156.222 25.771 ;
     RECT  157.104 25.681 157.122 25.771 ;
     RECT  129.24 25.753 129.33 25.781 ;
     RECT  31.068 25.531 31.446 25.789 ;
     RECT  58.68 25.681 58.698 25.789 ;
     RECT  82.404 25.717 82.422 25.816 ;
     RECT  60.048 25.717 60.57 25.817 ;
     RECT  79.956 25.717 80.046 25.817 ;
     RECT  82.404 25.816 82.458 25.825 ;
     RECT  93.816 25.717 94.626 25.825 ;
     RECT  97.092 25.717 97.11 25.825 ;
     RECT  97.884 25.753 98.694 25.825 ;
     RECT  129.24 25.781 129.294 25.825 ;
     RECT  135 25.717 135.018 25.825 ;
     RECT  142.815 2.413 143.097 25.825 ;
     RECT  148.215 25.771 148.986 25.825 ;
     RECT  185.796 25.753 186.105 25.825 ;
     RECT  207.18 25.667 207.705 25.825 ;
     RECT  150.372 25.717 150.39 25.852 ;
     RECT  156.204 25.771 157.122 25.852 ;
     RECT  43.848 25.681 43.866 25.853 ;
     RECT  74.664 25.753 74.754 25.853 ;
     RECT  92.088 25.717 92.106 25.853 ;
     RECT  92.88 25.681 92.898 25.853 ;
     RECT  145.368 25.717 146.574 25.853 ;
     RECT  148.215 25.825 149.31 25.853 ;
     RECT  154.476 25.681 154.566 25.853 ;
     RECT  182.412 25.753 182.466 25.853 ;
     RECT  28.584 25.555 29.934 25.861 ;
     RECT  101.124 25.717 101.142 25.861 ;
     RECT  130.608 25.825 130.626 25.861 ;
     RECT  132.015 25.717 132.426 25.861 ;
     RECT  133.992 25.825 134.01 25.861 ;
     RECT  134.928 25.825 135.27 25.861 ;
     RECT  138.564 25.825 138.582 25.861 ;
     RECT  139.716 25.825 139.734 25.861 ;
     RECT  150.372 25.852 150.426 25.861 ;
     RECT  97.02 25.825 98.694 25.889 ;
     RECT  156.204 25.852 157.158 25.889 ;
     RECT  182.412 25.853 182.43 25.889 ;
     RECT  40.215 25.667 40.305 25.937 ;
     RECT  51.015 25.667 51.105 25.937 ;
     RECT  61.815 25.717 62.73 25.937 ;
     RECT  72.615 25.667 72.705 25.937 ;
     RECT  83.415 25.709 83.505 25.937 ;
     RECT  93.816 25.825 94.662 25.937 ;
     RECT  115.815 25.667 115.905 25.937 ;
     RECT  126.54 25.667 126.705 25.937 ;
     RECT  137.415 25.667 137.505 25.937 ;
     RECT  148.215 25.853 148.305 25.937 ;
     RECT  153.615 25.667 153.705 25.937 ;
     RECT  159.015 25.667 159.105 25.937 ;
     RECT  164.415 25.667 164.505 25.937 ;
     RECT  169.815 25.667 169.905 25.937 ;
     RECT  175.215 25.667 175.305 25.937 ;
     RECT  180.615 25.667 180.705 25.937 ;
     RECT  185.472 25.825 186.105 25.937 ;
     RECT  191.415 25.667 191.505 25.937 ;
     RECT  196.815 25.667 196.905 25.937 ;
     RECT  202.215 25.667 202.305 25.937 ;
     RECT  207.072 25.825 207.705 25.937 ;
     RECT  13.215 2.413 13.497 25.951 ;
     RECT  24.015 2.413 24.297 25.951 ;
     RECT  28.584 25.861 30.294 25.951 ;
     RECT  31.068 25.789 31.518 25.951 ;
     RECT  34.815 25.667 35.082 25.951 ;
     RECT  45.615 25.667 45.882 25.951 ;
     RECT  56.415 2.413 56.697 25.951 ;
     RECT  67.215 25.667 67.482 25.951 ;
     RECT  78.015 25.709 78.678 25.951 ;
     RECT  85.896 25.717 86.166 25.951 ;
     RECT  132.015 25.861 132.534 25.951 ;
     RECT  207.072 25.937 207.27 25.951 ;
     RECT  99.615 25.667 99.882 25.963 ;
     RECT  110.415 25.709 110.61 25.963 ;
     RECT  121.215 25.667 121.41 25.963 ;
     RECT  28.584 25.951 31.518 25.979 ;
     RECT  128.916 25.825 129.294 25.979 ;
     RECT  131.904 25.951 132.534 25.979 ;
     RECT  54.792 25.951 54.81 25.987 ;
     RECT  56.304 25.951 56.697 25.987 ;
     RECT  205.776 25.483 205.794 25.987 ;
     RECT  206.604 25.951 207.27 25.987 ;
     RECT  13.104 25.951 13.497 25.997 ;
     RECT  23.904 25.951 24.297 25.997 ;
     RECT  34.704 25.951 35.082 25.997 ;
     RECT  45.504 25.951 45.882 25.997 ;
     RECT  56.304 25.987 56.754 25.997 ;
     RECT  67.104 25.951 67.482 25.997 ;
     RECT  77.904 25.951 78.678 25.997 ;
     RECT  88.704 25.757 89.082 25.997 ;
     RECT  93.816 25.937 93.834 25.997 ;
     RECT  94.608 25.937 94.662 25.997 ;
     RECT  131.904 25.979 132.21 25.997 ;
     RECT  62.604 25.937 62.73 26.015 ;
     RECT  78.156 25.997 78.678 26.015 ;
     RECT  82.08 25.825 82.458 26.015 ;
     RECT  94.644 25.997 94.662 26.015 ;
     RECT  97.02 25.889 98.622 26.015 ;
     RECT  99.504 25.963 99.882 26.015 ;
     RECT  104.616 25.619 105.426 26.015 ;
     RECT  110.304 25.963 110.61 26.015 ;
     RECT  121.104 25.963 121.41 26.015 ;
     RECT  133.992 25.861 135.306 26.015 ;
     RECT  24.015 25.997 24.297 26.023 ;
     RECT  100.728 25.861 101.466 26.045 ;
     RECT  43.056 25.717 43.074 26.051 ;
     RECT  54.72 25.987 54.81 26.051 ;
     RECT  56.664 25.997 56.754 26.051 ;
     RECT  62.712 26.015 62.73 26.051 ;
     RECT  67.464 25.997 67.482 26.051 ;
     RECT  74.664 25.853 74.682 26.051 ;
     RECT  78.156 26.015 78.282 26.051 ;
     RECT  85.896 25.951 86.67 26.051 ;
     RECT  89.064 25.997 89.082 26.051 ;
     RECT  126.54 25.937 126.558 26.051 ;
     RECT  129.168 25.979 129.294 26.051 ;
     RECT  130.536 25.861 130.626 26.051 ;
     RECT  138.528 25.861 138.582 26.051 ;
     RECT  145.368 25.853 146.502 26.051 ;
     RECT  60.552 25.817 60.57 26.087 ;
     RECT  97.02 26.015 97.83 26.087 ;
     RECT  104.616 26.015 104.634 26.093 ;
     RECT  105.408 26.015 105.426 26.093 ;
     RECT  145.836 26.051 146.502 26.123 ;
     RECT  150.3 25.861 150.426 26.123 ;
     RECT  156.204 25.889 156.222 26.123 ;
     RECT  185.472 25.937 185.742 26.123 ;
     RECT  32.472 26.095 32.49 26.131 ;
     RECT  35.064 25.997 35.082 26.159 ;
     RECT  54.72 26.051 54.738 26.159 ;
     RECT  56.736 26.051 56.754 26.159 ;
     RECT  98.604 26.015 98.622 26.159 ;
     RECT  99.864 26.015 99.882 26.159 ;
     RECT  130.536 26.051 130.554 26.159 ;
     RECT  134.928 26.015 135.306 26.159 ;
     RECT  204.624 26.023 204.642 26.159 ;
     RECT  5.112 25.591 8.874 26.203 ;
     RECT  45.864 25.997 45.882 26.204 ;
     RECT  138.528 26.051 138.546 26.204 ;
     RECT  145.836 26.123 146.466 26.204 ;
     RECT  154.476 25.853 154.494 26.204 ;
     RECT  157.032 25.889 157.158 26.204 ;
     RECT  208.656 26.131 208.674 26.221 ;
     RECT  4.86 26.203 8.874 26.249 ;
     RECT  58.68 25.789 59.166 26.249 ;
     RECT  142.74 25.825 143.406 26.249 ;
     RECT  205.776 25.987 207.27 26.249 ;
     RECT  0.108 26.203 0.126 26.285 ;
     RECT  64.656 25.717 64.674 26.429 ;
     RECT  129.168 26.051 129.186 26.477 ;
     RECT  5.256 26.249 8.874 26.519 ;
     RECT  149.22 25.853 149.31 26.519 ;
     RECT  139.716 25.861 139.986 26.555 ;
     RECT  149.22 26.519 149.238 26.573 ;
     RECT  134.928 26.159 135.198 26.591 ;
     RECT  133.992 26.015 134.01 26.627 ;
     RECT  109.476 25.861 109.494 26.663 ;
     RECT  117.432 25.861 117.45 26.699 ;
     RECT  202.428 26.599 202.446 26.789 ;
     RECT  41.04 25.667 41.058 26.969 ;
     RECT  142.74 26.249 143.334 27.053 ;
     RECT  18.615 18.769 19.314 27.059 ;
     RECT  42.768 26.176 42.786 27.059 ;
     RECT  79.956 25.817 79.974 27.095 ;
     RECT  81.072 25.825 81.09 27.095 ;
     RECT  90.252 25.717 90.522 27.131 ;
     RECT  145.836 26.204 146.106 27.167 ;
     RECT  97.02 26.087 97.038 27.203 ;
     RECT  85.896 26.051 86.166 27.239 ;
     RECT  150.3 26.123 150.318 27.239 ;
     RECT  78.156 26.051 78.174 27.284 ;
     RECT  5.256 26.519 6.282 27.373 ;
     RECT  7.056 26.519 8.874 27.373 ;
     RECT  10.656 27.211 10.674 27.373 ;
     RECT  14.652 27.337 14.67 27.373 ;
     RECT  5.256 27.373 8.874 27.401 ;
     RECT  6.12 27.401 8.874 27.481 ;
     RECT  9.648 27.301 9.666 27.481 ;
     RECT  13.215 25.997 13.497 27.481 ;
     RECT  14.364 27.373 14.67 27.481 ;
     RECT  28.692 25.979 31.482 27.635 ;
     RECT  6.12 27.481 9.666 27.751 ;
     RECT  10.656 27.373 11.394 27.751 ;
     RECT  13.215 27.481 14.67 27.751 ;
     RECT  15.66 26.671 15.678 27.751 ;
     RECT  6.12 27.751 12.078 27.905 ;
     RECT  13.215 27.751 15.678 27.905 ;
     RECT  6.12 27.905 9.594 27.941 ;
     RECT  28.944 27.635 31.482 28.08 ;
     RECT  32.472 26.131 32.526 28.08 ;
     RECT  59.148 26.249 59.166 28.08 ;
     RECT  82.08 26.015 82.098 28.08 ;
     RECT  86.148 27.239 86.166 28.08 ;
     RECT  97.812 26.087 97.83 28.08 ;
     RECT  103.14 25.861 103.158 28.08 ;
     RECT  142.74 27.053 142.758 28.08 ;
     RECT  157.032 26.204 157.05 28.08 ;
     RECT  173.448 25.745 173.466 28.08 ;
     RECT  178.956 25.745 178.974 28.08 ;
     RECT  185.724 26.123 185.742 28.08 ;
     RECT  202.356 27.796 202.374 28.08 ;
     RECT  206.244 26.249 207.27 28.08 ;
     RECT  5.256 27.401 5.274 28.175 ;
     RECT  28.944 28.08 207.27 28.175 ;
     RECT  18.615 27.059 18.897 28.219 ;
     RECT  19.944 27.913 19.962 28.219 ;
     RECT  10.8 27.905 11.502 28.319 ;
     RECT  25.524 26.941 25.542 28.381 ;
     RECT  14.724 27.905 15.678 28.481 ;
     RECT  18.615 28.219 19.962 28.715 ;
     RECT  25.524 28.381 25.722 28.795 ;
     RECT  26.856 28.021 26.874 28.795 ;
     RECT  24.015 26.023 24.786 28.831 ;
     RECT  25.524 28.795 25.794 28.831 ;
     RECT  13.215 27.905 13.497 28.921 ;
     RECT  26.784 28.795 26.874 28.921 ;
     RECT  26.784 28.921 27.126 28.973 ;
     RECT  0.108 28.939 0.126 28.985 ;
     RECT  26.784 28.973 26.802 29.069 ;
     RECT  6.12 27.941 9.378 29.255 ;
     RECT  12.78 28.921 13.497 29.255 ;
     RECT  24.015 28.831 25.794 29.255 ;
     RECT  25.524 29.255 25.794 29.327 ;
     RECT  11.304 28.319 11.502 29.371 ;
     RECT  27.972 27.679 27.99 29.461 ;
     RECT  29.088 28.175 207.27 29.461 ;
     RECT  25.524 29.327 25.686 29.489 ;
     RECT  17.856 29.191 17.874 29.497 ;
     RECT  18.615 28.715 19.638 29.497 ;
     RECT  17.856 29.497 19.638 29.525 ;
     RECT  25.524 29.489 25.65 29.525 ;
     RECT  22.824 28.939 22.842 29.597 ;
     RECT  27.972 29.461 207.27 29.645 ;
     RECT  18.036 29.525 19.638 29.669 ;
     RECT  208.548 26.221 208.674 29.875 ;
     RECT  18.615 29.669 19.638 29.899 ;
     RECT  13.215 29.255 13.497 29.911 ;
     RECT  24.015 29.255 24.786 29.995 ;
     RECT  13.215 29.911 13.59 30.001 ;
     RECT  13.215 30.001 13.986 30.451 ;
     RECT  14.796 28.481 15.678 30.451 ;
     RECT  27.972 29.645 28.53 30.475 ;
     RECT  208.044 29.875 208.674 30.509 ;
     RECT  27.936 30.475 28.53 30.667 ;
     RECT  208.512 30.509 208.674 30.667 ;
     RECT  27.324 30.667 28.53 30.685 ;
     RECT  29.268 29.645 207.27 30.685 ;
     RECT  234.615 24.089 234.897 30.685 ;
     RECT  236.52 30.667 236.538 30.713 ;
     RECT  218.415 2.413 218.697 30.811 ;
     RECT  229.215 13.019 229.497 30.811 ;
     RECT  233.316 28.759 233.334 30.811 ;
     RECT  234.288 30.685 234.897 30.811 ;
     RECT  233.316 30.811 234.897 30.839 ;
     RECT  218.304 30.811 218.697 30.848 ;
     RECT  229.104 30.811 229.497 30.848 ;
     RECT  233.316 30.839 233.586 30.848 ;
     RECT  13.215 30.451 15.678 31.081 ;
     RECT  18.615 29.899 19.854 31.109 ;
     RECT  208.512 30.667 208.782 31.145 ;
     RECT  22.752 30.379 22.77 31.147 ;
     RECT  27.324 30.685 207.27 31.253 ;
     RECT  10.872 29.371 11.502 31.261 ;
     RECT  208.548 31.145 208.782 31.261 ;
     RECT  208.548 31.261 208.89 31.325 ;
     RECT  10.872 31.261 11.61 31.351 ;
     RECT  10.836 31.351 11.61 31.495 ;
     RECT  12.744 31.081 15.678 31.495 ;
     RECT  18.615 31.109 19.242 31.649 ;
     RECT  0.108 31.657 0.126 31.709 ;
     RECT  10.836 31.495 15.678 31.765 ;
     RECT  26.532 31.051 26.55 31.765 ;
     RECT  18.615 31.649 19.062 31.793 ;
     RECT  22.536 31.147 22.77 31.801 ;
     RECT  26.388 31.765 26.55 31.801 ;
     RECT  27.324 31.253 27.99 31.801 ;
     RECT  25.632 29.525 25.65 31.867 ;
     RECT  26.388 31.801 27.99 31.867 ;
     RECT  10.728 31.765 15.678 31.919 ;
     RECT  10.836 31.919 15.678 32.237 ;
     RECT  6.84 29.255 9.378 32.341 ;
     RECT  25.632 31.867 27.99 32.341 ;
     RECT  28.728 31.253 207.27 32.341 ;
     RECT  6.444 32.341 9.378 32.459 ;
     RECT  6.768 32.459 9.378 32.467 ;
     RECT  24.015 29.995 24.894 32.467 ;
     RECT  25.632 32.341 207.27 32.467 ;
     RECT  6.768 32.467 9.702 32.477 ;
     RECT  11.376 32.237 15.678 32.495 ;
     RECT  21.456 32.203 21.474 32.809 ;
     RECT  21.204 32.809 21.474 32.845 ;
     RECT  18.615 31.793 18.897 32.881 ;
     RECT  21.204 32.845 21.51 32.881 ;
     RECT  12.06 32.495 15.678 32.999 ;
     RECT  21.204 32.881 21.582 32.999 ;
     RECT  24.015 32.467 207.27 32.999 ;
     RECT  20.16 32.011 20.178 33.007 ;
     RECT  21.204 32.999 21.474 33.007 ;
     RECT  18.615 32.881 19.134 33.043 ;
     RECT  208.548 31.325 208.674 33.043 ;
     RECT  20.16 33.007 21.474 33.053 ;
     RECT  6.912 32.477 9.702 33.241 ;
     RECT  4.284 32.035 4.302 33.385 ;
     RECT  22.536 31.801 23.274 33.421 ;
     RECT  3.996 33.385 4.302 33.511 ;
     RECT  3.996 33.511 4.59 33.541 ;
     RECT  18.18 33.043 19.134 33.547 ;
     RECT  20.16 33.053 20.286 33.547 ;
     RECT  3.744 33.541 4.59 33.581 ;
     RECT  6.912 33.241 9.81 33.583 ;
     RECT  22.212 33.421 23.274 33.619 ;
     RECT  24.015 32.999 26.01 33.619 ;
     RECT  6.336 33.583 9.81 33.629 ;
     RECT  3.744 33.581 4.446 33.691 ;
     RECT  208.476 33.043 208.674 33.739 ;
     RECT  22.212 33.619 26.01 33.925 ;
     RECT  26.748 32.999 207.27 33.925 ;
     RECT  18.18 33.547 20.286 33.961 ;
     RECT  208.476 33.739 208.746 34.027 ;
     RECT  21.204 33.053 21.474 34.051 ;
     RECT  22.212 33.925 207.27 34.051 ;
     RECT  6.336 33.629 7.074 34.079 ;
     RECT  208.476 34.027 208.89 34.079 ;
     RECT  18.072 33.961 20.286 34.087 ;
     RECT  12.168 32.999 15.678 34.115 ;
     RECT  13.032 34.115 15.678 34.159 ;
     RECT  18.072 34.087 20.358 34.171 ;
     RECT  21.204 34.051 207.27 34.171 ;
     RECT  5.688 34.159 5.706 34.349 ;
     RECT  3.42 33.691 4.446 34.355 ;
     RECT  4.356 34.355 4.446 34.357 ;
     RECT  12.168 34.115 12.186 34.385 ;
     RECT  4.356 34.357 4.626 34.393 ;
     RECT  13.032 34.159 15.714 34.429 ;
     RECT  2.415 23.819 2.697 34.501 ;
     RECT  18.072 34.171 207.27 34.501 ;
     RECT  2.415 34.501 3.294 34.619 ;
     RECT  7.815 33.629 9.81 34.619 ;
     RECT  0.108 34.459 0.126 34.655 ;
     RECT  17.964 34.501 207.27 35.041 ;
     RECT  233.316 30.848 233.334 35.041 ;
     RECT  17.892 35.041 207.27 35.069 ;
     RECT  17.892 35.069 207.234 35.195 ;
     RECT  17.892 35.195 28.314 35.267 ;
     RECT  16.956 26.401 16.974 35.275 ;
     RECT  10.728 33.511 10.746 35.473 ;
     RECT  12.06 34.861 12.078 35.545 ;
     RECT  13.032 34.429 16.038 35.545 ;
     RECT  16.776 35.275 16.974 35.545 ;
     RECT  17.892 35.267 28.062 35.545 ;
     RECT  9.288 34.619 9.81 35.581 ;
     RECT  10.728 35.473 10.854 35.581 ;
     RECT  13.032 35.545 28.062 35.581 ;
     RECT  10.548 35.581 10.89 35.735 ;
     RECT  10.692 35.735 10.89 35.803 ;
     RECT  11.664 35.545 12.222 35.803 ;
     RECT  7.815 34.619 8.334 35.851 ;
     RECT  9.252 35.581 9.81 35.851 ;
     RECT  29.124 35.195 207.234 35.941 ;
     RECT  10.692 35.803 12.222 35.977 ;
     RECT  12.96 35.581 28.062 35.977 ;
     RECT  7.815 35.851 9.81 36.005 ;
     RECT  10.692 35.977 28.062 36.029 ;
     RECT  5.76 35.899 5.778 36.239 ;
     RECT  12.852 36.029 28.062 36.239 ;
     RECT  9.288 36.005 9.81 36.275 ;
     RECT  6.516 34.079 7.074 36.391 ;
     RECT  7.815 36.005 8.478 36.391 ;
     RECT  6.516 36.391 8.478 36.461 ;
     RECT  13.104 36.239 28.062 36.475 ;
     RECT  28.944 35.941 207.234 36.475 ;
     RECT  6.516 36.461 7.074 36.509 ;
     RECT  13.104 36.475 207.234 36.517 ;
     RECT  9.432 36.275 9.81 36.523 ;
     RECT  10.692 36.029 12.078 36.523 ;
     RECT  208.476 34.079 208.674 36.661 ;
     RECT  13.104 36.517 207.522 36.689 ;
     RECT  9.432 36.523 12.078 36.923 ;
     RECT  6.3 36.625 6.318 37.165 ;
     RECT  208.476 36.661 208.746 37.195 ;
     RECT  4.356 34.393 4.734 37.201 ;
     RECT  5.688 37.165 6.318 37.201 ;
     RECT  4.356 37.201 6.318 37.319 ;
     RECT  13.14 36.689 207.522 37.319 ;
     RECT  208.476 37.195 208.782 37.319 ;
     RECT  0.108 37.195 0.126 37.355 ;
     RECT  7.056 36.509 7.074 37.435 ;
     RECT  7.815 36.461 8.478 37.435 ;
     RECT  234.615 30.839 234.897 37.435 ;
     RECT  4.356 37.319 5.814 37.469 ;
     RECT  13.14 37.319 207.234 37.471 ;
     RECT  9.792 36.923 12.078 37.483 ;
     RECT  236.52 37.471 236.538 37.517 ;
     RECT  9.792 37.483 12.186 37.531 ;
     RECT  12.924 37.471 207.234 37.531 ;
     RECT  7.056 37.435 8.478 37.561 ;
     RECT  233.316 35.041 233.55 37.579 ;
     RECT  234.288 37.435 234.897 37.579 ;
     RECT  5.148 37.469 5.814 37.589 ;
     RECT  233.316 37.579 234.897 37.589 ;
     RECT  9.792 37.531 207.234 37.625 ;
     RECT  233.316 37.589 233.586 37.625 ;
     RECT  208.476 37.319 208.746 37.697 ;
     RECT  6.732 37.561 8.478 37.819 ;
     RECT  6.732 37.819 8.586 38.011 ;
     RECT  9.792 37.625 9.99 38.011 ;
     RECT  10.764 37.625 207.234 38.101 ;
     RECT  10.764 38.101 207.486 38.141 ;
     RECT  10.764 38.141 207.234 38.165 ;
     RECT  10.764 38.165 207.198 38.189 ;
     RECT  6.732 38.011 9.99 38.371 ;
     RECT  10.764 38.189 28.386 38.371 ;
     RECT  6.732 38.371 28.386 38.705 ;
     RECT  208.476 37.697 208.674 38.705 ;
     RECT  6.732 38.705 28.062 38.749 ;
     RECT  6.696 38.749 28.062 38.813 ;
     RECT  6.696 38.813 9.126 38.939 ;
     RECT  6.696 38.939 9.054 39.019 ;
     RECT  29.124 38.189 207.198 39.019 ;
     RECT  6.228 39.019 9.054 39.055 ;
     RECT  6.12 39.055 9.054 39.091 ;
     RECT  5.292 39.091 9.054 39.149 ;
     RECT  29.124 39.019 207.27 39.181 ;
     RECT  5.436 39.149 9.054 39.209 ;
     RECT  208.656 38.705 208.674 39.355 ;
     RECT  28.944 39.181 207.27 39.487 ;
     RECT  28.872 39.487 207.27 39.499 ;
     RECT  6.12 39.209 9.054 39.515 ;
     RECT  208.656 39.355 208.746 39.523 ;
     RECT  208.656 39.523 208.89 39.589 ;
     RECT  9.864 38.813 28.062 39.631 ;
     RECT  208.62 39.589 208.89 39.749 ;
     RECT  28.872 39.499 207.45 39.821 ;
     RECT  6.444 39.515 9.054 39.829 ;
     RECT  9.828 39.631 28.062 39.829 ;
     RECT  6.444 39.829 28.062 39.865 ;
     RECT  28.872 39.821 206.37 39.865 ;
     RECT  207.18 39.821 207.45 39.865 ;
     RECT  208.62 39.749 208.746 40.019 ;
     RECT  0.108 39.979 0.126 40.055 ;
     RECT  208.656 40.019 208.746 40.163 ;
     RECT  4.356 37.469 4.374 40.199 ;
     RECT  207.18 39.865 207.486 40.267 ;
     RECT  207.18 40.267 207.522 40.325 ;
     RECT  208.656 40.163 208.71 40.325 ;
     RECT  207.18 40.325 207.45 41.099 ;
     RECT  213.015 2.413 213.297 41.107 ;
     RECT  213.012 41.107 213.297 41.165 ;
     RECT  207.18 41.099 207.198 42.061 ;
     RECT  208.656 40.325 208.674 42.061 ;
     RECT  6.444 39.865 206.37 42.151 ;
     RECT  207.18 42.061 207.486 42.151 ;
     RECT  208.656 42.061 208.746 42.179 ;
     RECT  6.444 42.151 207.486 42.457 ;
     RECT  6.192 42.457 207.486 42.509 ;
     RECT  6.336 42.509 207.486 42.719 ;
     RECT  0.108 42.715 0.126 42.755 ;
     RECT  6.516 42.719 207.486 42.755 ;
     RECT  8.928 42.755 207.486 42.791 ;
     RECT  9.036 42.791 207.486 42.989 ;
     RECT  207.18 42.989 207.486 42.997 ;
     RECT  208.656 42.179 208.71 43.147 ;
     RECT  208.512 43.147 208.71 43.231 ;
     RECT  207.18 42.997 207.522 43.277 ;
     RECT  208.512 43.231 208.782 43.331 ;
     RECT  207.18 43.277 207.486 43.373 ;
     RECT  208.512 43.331 208.71 43.565 ;
     RECT  6.516 42.755 8.154 43.609 ;
     RECT  9.036 42.989 206.37 43.609 ;
     RECT  6.516 43.609 206.37 43.835 ;
     RECT  234.615 37.589 234.897 44.185 ;
     RECT  236.52 44.221 236.538 44.333 ;
     RECT  9.036 43.835 206.37 44.339 ;
     RECT  233.316 37.625 233.55 44.347 ;
     RECT  10.548 44.339 206.37 44.411 ;
     RECT  233.316 44.347 233.586 44.491 ;
     RECT  234.615 44.185 235.098 44.491 ;
     RECT  27.396 44.411 206.37 44.609 ;
     RECT  233.316 44.491 235.098 44.609 ;
     RECT  233.316 44.609 234.897 44.645 ;
     RECT  10.548 44.411 26.658 44.789 ;
     RECT  10.764 44.789 26.658 45.149 ;
     RECT  27.54 44.609 206.37 45.157 ;
     RECT  207.18 43.373 207.198 45.157 ;
     RECT  10.836 45.149 26.658 45.221 ;
     RECT  13.14 45.221 26.658 45.293 ;
     RECT  208.656 43.565 208.71 45.301 ;
     RECT  208.584 45.301 208.71 45.451 ;
     RECT  2.415 34.619 2.697 45.499 ;
     RECT  13.215 45.293 26.658 45.527 ;
     RECT  208.548 45.451 208.71 45.535 ;
     RECT  9.036 44.339 9.558 45.571 ;
     RECT  14.616 45.527 26.658 45.571 ;
     RECT  27.54 45.157 207.198 45.571 ;
     RECT  10.836 45.221 12.222 45.599 ;
     RECT  13.215 45.527 13.626 45.599 ;
     RECT  208.548 45.535 208.818 45.643 ;
     RECT  9.036 45.571 9.918 45.697 ;
     RECT  14.616 45.571 207.198 45.697 ;
     RECT  208.044 45.643 208.818 45.697 ;
     RECT  2.34 45.499 2.697 45.725 ;
     RECT  14.616 45.697 208.818 45.773 ;
     RECT  208.044 45.773 208.818 45.832 ;
     RECT  208.044 45.832 208.854 45.869 ;
     RECT  8.892 45.697 9.918 45.959 ;
     RECT  14.616 45.773 206.946 45.965 ;
     RECT  8.892 45.959 9.738 45.995 ;
     RECT  14.616 45.965 206.37 45.995 ;
     RECT  9.036 45.995 9.738 46.139 ;
     RECT  15.156 45.995 206.37 46.409 ;
     RECT  6.516 43.835 8.097 46.679 ;
     RECT  11.124 45.599 12.222 47.011 ;
     RECT  13.215 45.599 13.497 47.011 ;
     RECT  9.036 46.139 9.054 47.039 ;
     RECT  15.408 46.409 206.37 47.111 ;
     RECT  16.128 47.111 206.37 47.183 ;
     RECT  16.416 47.183 206.37 47.213 ;
     RECT  21.096 47.213 206.37 47.405 ;
     RECT  218.415 30.848 218.697 47.551 ;
     RECT  218.304 47.551 218.697 47.597 ;
     RECT  21.168 47.405 206.37 47.651 ;
     RECT  226.296 47.563 226.314 47.693 ;
     RECT  230.868 47.659 230.886 47.696 ;
     RECT  233.316 44.645 233.55 47.731 ;
     RECT  208.044 45.869 208.818 47.759 ;
     RECT  6.516 46.679 7.074 47.893 ;
     RECT  5.4 45.967 5.418 48.119 ;
     RECT  16.416 47.213 20.142 48.119 ;
     RECT  208.548 47.759 208.818 48.127 ;
     RECT  16.416 48.119 17.154 48.155 ;
     RECT  208.548 48.127 208.926 48.191 ;
     RECT  18.252 48.119 20.142 48.199 ;
     RECT  4.284 48.199 4.302 48.235 ;
     RECT  2.415 45.725 2.697 48.271 ;
     RECT  0.108 48.235 0.126 48.272 ;
     RECT  11.124 47.011 13.497 48.299 ;
     RECT  2.415 48.271 3.366 48.317 ;
     RECT  4.176 48.235 4.302 48.389 ;
     RECT  14.832 48.271 14.85 48.389 ;
     RECT  207.468 48.235 207.486 48.397 ;
     RECT  18.252 48.199 20.466 48.541 ;
     RECT  21.312 47.651 206.37 48.541 ;
     RECT  11.124 48.299 12.222 48.569 ;
     RECT  13.215 48.299 13.497 48.631 ;
     RECT  208.62 48.191 208.926 48.631 ;
     RECT  3.924 48.541 3.942 48.659 ;
     RECT  6.264 47.893 7.074 48.659 ;
     RECT  13.215 48.631 13.662 48.701 ;
     RECT  18.252 48.541 206.37 48.703 ;
     RECT  16.416 48.155 16.47 48.731 ;
     RECT  208.62 48.631 208.962 48.739 ;
     RECT  207.432 48.397 207.486 48.775 ;
     RECT  18.252 48.703 206.514 48.839 ;
     RECT  15.192 48.805 15.21 48.845 ;
     RECT  18.504 48.839 206.514 48.929 ;
     RECT  28.548 48.929 206.514 48.937 ;
     RECT  207.396 48.775 207.486 48.937 ;
     RECT  28.548 48.937 207.486 49.229 ;
     RECT  18.504 48.929 27.81 49.235 ;
     RECT  207.504 49.477 207.522 49.517 ;
     RECT  208.62 48.739 209.034 49.579 ;
     RECT  18.615 49.235 27.81 49.855 ;
     RECT  28.548 49.229 206.514 49.855 ;
     RECT  208.584 49.579 209.034 49.855 ;
     RECT  6.264 48.659 6.534 49.891 ;
     RECT  18.615 49.855 206.514 49.901 ;
     RECT  11.484 48.569 12.222 49.919 ;
     RECT  6.264 49.891 7.074 50.009 ;
     RECT  18.615 49.901 27.81 50.009 ;
     RECT  28.548 49.901 206.514 50.093 ;
     RECT  21.564 50.009 22.014 50.153 ;
     RECT  22.824 50.009 27.45 50.153 ;
     RECT  28.548 50.093 206.37 50.333 ;
     RECT  22.824 50.153 27.342 50.381 ;
     RECT  208.584 49.855 209.214 50.521 ;
     RECT  23.724 50.381 27.342 50.585 ;
     RECT  25.92 50.585 27.342 50.729 ;
     RECT  23.724 50.585 25.074 50.855 ;
     RECT  23.796 50.855 25.074 50.891 ;
     RECT  6.264 50.009 6.534 50.971 ;
     RECT  18.615 50.009 20.61 50.971 ;
     RECT  21.996 50.153 22.014 50.971 ;
     RECT  21.456 50.971 22.014 50.999 ;
     RECT  21.456 50.999 21.834 51.089 ;
     RECT  5.796 50.971 6.966 51.097 ;
     RECT  0.108 51.019 0.126 51.125 ;
     RECT  236.52 51.16 236.538 51.197 ;
     RECT  29.088 50.333 206.37 51.205 ;
     RECT  233.316 47.731 233.802 51.205 ;
     RECT  234.615 44.645 234.897 51.205 ;
     RECT  22.824 50.381 22.842 51.233 ;
     RECT  4.824 51.169 4.842 51.293 ;
     RECT  28.512 51.205 206.37 51.307 ;
     RECT  28.404 51.307 206.37 51.331 ;
     RECT  21.816 51.089 21.834 51.359 ;
     RECT  233.316 51.205 234.897 51.359 ;
     RECT  5.58 51.097 6.966 51.395 ;
     RECT  27.972 51.331 206.37 51.601 ;
     RECT  22.752 51.367 22.77 51.629 ;
     RECT  23.868 50.891 25.074 51.781 ;
     RECT  25.92 50.729 27.162 51.821 ;
     RECT  27.936 51.601 206.37 51.821 ;
     RECT  27.072 51.821 27.162 51.883 ;
     RECT  27.936 51.821 206.28 51.883 ;
     RECT  27.072 51.883 206.28 51.899 ;
     RECT  6.12 51.395 6.966 51.935 ;
     RECT  23.868 51.781 25.11 51.935 ;
     RECT  27.36 51.899 206.28 51.935 ;
     RECT  6.516 51.935 6.966 52.051 ;
     RECT  7.815 46.679 8.097 52.051 ;
     RECT  24.015 51.935 25.11 52.051 ;
     RECT  25.92 51.821 26.298 52.051 ;
     RECT  27.504 51.935 206.28 52.109 ;
     RECT  18.615 50.971 20.682 52.301 ;
     RECT  18.615 52.301 20.61 52.313 ;
     RECT  207.504 51.979 207.522 52.321 ;
     RECT  18.615 52.313 19.602 52.349 ;
     RECT  6.516 52.051 8.097 52.411 ;
     RECT  8.82 50.125 8.838 52.411 ;
     RECT  28.296 52.109 206.28 52.439 ;
     RECT  207.468 52.321 207.522 52.439 ;
     RECT  6.516 52.411 8.838 52.475 ;
     RECT  207.468 52.439 207.486 52.589 ;
     RECT  28.44 52.439 206.28 52.651 ;
     RECT  233.316 51.359 233.334 52.709 ;
     RECT  28.44 52.651 206.37 52.781 ;
     RECT  27.504 52.109 27.522 52.861 ;
     RECT  24.015 52.051 26.298 52.951 ;
     RECT  27.072 52.861 27.522 52.951 ;
     RECT  24.015 52.951 27.522 52.973 ;
     RECT  26.136 52.973 27.522 52.979 ;
     RECT  20.592 52.313 20.61 53.221 ;
     RECT  27.504 52.979 27.522 53.221 ;
     RECT  28.44 52.781 28.494 53.221 ;
     RECT  7.815 52.475 8.838 53.249 ;
     RECT  26.172 52.979 26.766 53.393 ;
     RECT  26.28 53.393 26.766 53.453 ;
     RECT  6.516 52.475 6.966 53.563 ;
     RECT  27.504 53.221 28.494 53.645 ;
     RECT  26.748 53.453 26.766 53.741 ;
     RECT  11.844 49.919 12.222 53.761 ;
     RECT  13.215 48.701 13.497 53.761 ;
     RECT  6.408 53.563 6.966 53.797 ;
     RECT  7.815 53.249 8.097 53.797 ;
     RECT  0.108 53.755 0.126 53.825 ;
     RECT  6.408 53.797 8.097 53.825 ;
     RECT  28.44 53.645 28.494 54.031 ;
     RECT  29.268 52.781 206.37 54.031 ;
     RECT  17.712 53.941 17.73 54.059 ;
     RECT  27.324 53.941 27.414 54.059 ;
     RECT  11.844 53.761 13.497 54.095 ;
     RECT  20.124 53.221 20.61 54.095 ;
     RECT  14.832 54.031 14.85 54.131 ;
     RECT  6.516 53.825 8.097 54.365 ;
     RECT  28.44 54.031 206.37 54.571 ;
     RECT  8.82 53.249 8.838 54.715 ;
     RECT  8.82 54.715 8.91 54.743 ;
     RECT  20.304 54.095 20.61 54.955 ;
     RECT  28.44 54.571 206.946 55.373 ;
     RECT  19.908 54.955 20.61 55.435 ;
     RECT  207.504 55.417 207.522 55.469 ;
     RECT  208.296 50.521 209.214 55.613 ;
     RECT  208.296 55.613 208.854 55.679 ;
     RECT  28.44 55.373 206.37 55.949 ;
     RECT  6.552 54.365 8.097 56.065 ;
     RECT  24.015 52.973 24.966 56.065 ;
     RECT  6.552 56.065 8.154 56.101 ;
     RECT  8.892 54.743 8.91 56.101 ;
     RECT  18.615 52.349 18.897 56.101 ;
     RECT  19.908 55.435 20.934 56.101 ;
     RECT  10.8 55.993 10.818 56.129 ;
     RECT  3.78 56.065 3.798 56.219 ;
     RECT  18.615 56.101 20.934 56.219 ;
     RECT  29.268 55.949 206.37 56.219 ;
     RECT  24.015 56.065 25.686 56.255 ;
     RECT  6.552 56.101 8.91 56.327 ;
     RECT  18.615 56.219 19.566 56.327 ;
     RECT  2.415 48.317 2.697 56.335 ;
     RECT  17.46 56.335 17.478 56.489 ;
     RECT  1.728 56.335 2.697 56.525 ;
     RECT  8.82 56.327 8.91 56.561 ;
     RECT  11.844 54.095 12.222 56.669 ;
     RECT  4.14 56.641 4.158 56.759 ;
     RECT  29.592 56.219 206.37 56.759 ;
     RECT  6.552 56.327 8.097 57.029 ;
     RECT  18.615 56.327 18.897 57.145 ;
     RECT  27.324 54.059 27.342 57.379 ;
     RECT  28.44 55.949 28.494 57.379 ;
     RECT  27.324 57.379 28.494 57.451 ;
     RECT  29.268 57.019 29.286 57.451 ;
     RECT  27.324 57.451 29.286 57.677 ;
     RECT  234.615 51.359 234.897 57.685 ;
     RECT  30.24 56.759 206.37 57.811 ;
     RECT  208.296 55.679 208.35 57.955 ;
     RECT  27.324 57.677 27.918 57.991 ;
     RECT  237.492 57.541 237.51 58.013 ;
     RECT  30.204 57.811 206.37 58.061 ;
     RECT  26.784 57.991 27.918 58.109 ;
     RECT  233.64 52.861 233.658 58.109 ;
     RECT  234.615 57.685 235.062 58.109 ;
     RECT  24.015 56.255 24.966 58.117 ;
     RECT  29.124 57.677 29.286 58.117 ;
     RECT  30.24 58.061 206.37 58.117 ;
     RECT  207.468 57.991 207.486 58.117 ;
     RECT  29.124 58.117 29.358 58.157 ;
     RECT  30.24 58.117 207.486 58.157 ;
     RECT  29.34 58.157 29.358 58.253 ;
     RECT  208.296 57.955 208.71 58.315 ;
     RECT  6.552 57.029 6.822 58.379 ;
     RECT  5.256 56.911 5.274 58.495 ;
     RECT  208.296 58.315 208.782 58.495 ;
     RECT  208.296 58.495 208.926 58.541 ;
     RECT  18.615 57.145 18.954 58.649 ;
     RECT  208.296 58.541 208.746 58.685 ;
     RECT  7.815 57.029 8.097 58.693 ;
     RECT  8.82 56.561 8.838 58.693 ;
     RECT  207.468 58.157 207.486 58.733 ;
     RECT  208.296 58.685 208.35 58.829 ;
     RECT  29.415 58.843 29.505 58.877 ;
     RECT  5.256 58.495 5.814 59.189 ;
     RECT  5.256 59.189 5.274 59.233 ;
     RECT  2.415 56.525 2.697 59.275 ;
     RECT  5.112 59.233 5.274 59.459 ;
     RECT  20.448 56.219 20.934 59.459 ;
     RECT  7.815 58.693 8.838 59.467 ;
     RECT  30.24 58.157 206.37 59.467 ;
     RECT  0.108 59.275 0.126 59.495 ;
     RECT  2.415 59.275 3.222 59.531 ;
     RECT  3.96 59.233 3.978 59.539 ;
     RECT  3.96 59.539 4.194 59.603 ;
     RECT  27.324 58.109 27.918 59.729 ;
     RECT  30.204 59.467 206.37 59.837 ;
     RECT  20.592 59.459 20.934 60.269 ;
     RECT  7.815 59.467 9.162 60.277 ;
     RECT  7.815 60.277 9.846 60.539 ;
     RECT  7.815 60.539 8.097 60.655 ;
     RECT  30.24 59.837 206.37 60.655 ;
     RECT  24.015 58.117 25.254 60.809 ;
     RECT  18.615 58.649 18.897 60.961 ;
     RECT  30.204 60.655 206.37 60.961 ;
     RECT  30.204 60.961 206.946 61.099 ;
     RECT  30.168 61.099 206.946 61.133 ;
     RECT  208.332 58.829 208.35 61.189 ;
     RECT  20.592 60.269 20.682 61.349 ;
     RECT  207.468 61.195 207.522 61.613 ;
     RECT  7.704 60.655 8.097 61.619 ;
     RECT  6.552 58.379 6.57 61.735 ;
     RECT  30.168 61.133 206.28 61.867 ;
     RECT  208.332 61.189 208.746 61.901 ;
     RECT  207.504 61.613 207.522 61.925 ;
     RECT  208.728 61.901 208.746 61.925 ;
     RECT  2.415 59.531 2.697 62.011 ;
     RECT  29.34 59.371 29.358 62.059 ;
     RECT  29.016 62.059 29.358 62.159 ;
     RECT  2.304 62.011 2.697 62.195 ;
     RECT  5.256 59.459 5.274 62.239 ;
     RECT  4.176 59.603 4.194 62.267 ;
     RECT  5.256 62.239 5.418 62.275 ;
     RECT  5.256 62.275 5.634 62.311 ;
     RECT  4.86 62.311 5.634 62.381 ;
     RECT  5.256 62.381 5.634 62.429 ;
     RECT  26.244 59.701 26.262 62.429 ;
     RECT  6.552 61.735 6.822 62.473 ;
     RECT  30.168 61.867 206.37 62.477 ;
     RECT  5.256 62.429 5.418 62.501 ;
     RECT  15.372 62.155 15.39 62.545 ;
     RECT  16.416 48.731 16.434 62.671 ;
     RECT  15.336 62.545 15.39 62.699 ;
     RECT  16.416 62.671 16.974 62.717 ;
     RECT  30.276 62.477 206.37 62.861 ;
     RECT  29.016 62.159 29.034 63.163 ;
     RECT  29.016 63.163 29.505 63.197 ;
     RECT  30.348 62.861 206.37 63.751 ;
     RECT  15.336 62.699 15.354 63.779 ;
     RECT  13.215 54.095 13.497 63.823 ;
     RECT  30.348 63.751 206.946 64.057 ;
     RECT  30.204 64.057 206.946 64.201 ;
     RECT  11.844 56.669 11.862 64.291 ;
     RECT  12.6 63.823 13.497 64.291 ;
     RECT  29.016 63.197 29.142 64.291 ;
     RECT  30.204 64.201 206.982 64.291 ;
     RECT  18.615 60.961 19.062 64.319 ;
     RECT  28.944 64.291 29.142 64.327 ;
     RECT  30.204 64.291 207.486 64.363 ;
     RECT  208.764 64.201 208.782 64.363 ;
     RECT  30.168 64.363 207.486 64.4 ;
     RECT  28.944 64.327 29.25 64.493 ;
     RECT  30.204 64.4 207.486 64.493 ;
     RECT  207.468 64.493 207.486 64.588 ;
     RECT  234.615 58.109 234.897 64.705 ;
     RECT  30.204 64.493 206.28 64.781 ;
     RECT  235.98 64.741 235.998 64.829 ;
     RECT  28.944 64.493 29.034 64.831 ;
     RECT  208.764 64.363 208.854 64.831 ;
     RECT  28.332 64.831 29.034 64.859 ;
     RECT  232.272 47.731 232.29 64.859 ;
     RECT  0.108 64.795 0.126 64.895 ;
     RECT  208.764 64.831 208.89 64.939 ;
     RECT  6.552 62.473 6.966 64.975 ;
     RECT  7.815 61.619 8.097 64.975 ;
     RECT  234.324 64.705 234.897 65.011 ;
     RECT  6.408 64.975 8.097 65.021 ;
     RECT  6.552 65.021 8.097 65.129 ;
     RECT  8.82 60.539 9.846 65.129 ;
     RECT  234 65.011 234.897 65.165 ;
     RECT  208.728 64.939 208.89 65.227 ;
     RECT  208.728 65.227 208.962 65.407 ;
     RECT  28.332 64.859 28.35 65.515 ;
     RECT  28.224 65.515 28.35 65.549 ;
     RECT  207.468 64.588 207.522 65.645 ;
     RECT  208.62 65.407 208.962 65.899 ;
     RECT  207.504 65.645 207.522 66.055 ;
     RECT  208.62 65.899 208.998 66.055 ;
     RECT  11.844 64.291 13.497 66.209 ;
     RECT  11.844 66.209 11.862 66.325 ;
     RECT  30.348 64.781 206.28 66.379 ;
     RECT  207.504 66.055 208.998 66.509 ;
     RECT  207.504 66.509 208.89 66.701 ;
     RECT  208.692 66.701 208.89 66.797 ;
     RECT  26.496 66.859 26.514 66.955 ;
     RECT  26.496 66.955 26.55 67.003 ;
     RECT  8.82 65.129 9.522 67.019 ;
     RECT  5.256 62.501 5.274 67.135 ;
     RECT  7.815 65.129 8.097 67.171 ;
     RECT  8.82 67.019 8.91 67.171 ;
     RECT  208.728 66.797 208.89 67.243 ;
     RECT  28.224 65.549 28.242 67.297 ;
     RECT  208.728 67.243 208.962 67.325 ;
     RECT  30.312 66.379 206.28 67.339 ;
     RECT  28.224 67.297 28.962 67.369 ;
     RECT  30.204 67.339 206.28 67.369 ;
     RECT  28.224 67.369 206.28 67.397 ;
     RECT  29.415 67.397 206.28 67.517 ;
     RECT  11.7 66.325 11.862 67.559 ;
     RECT  0.108 67.531 0.126 67.595 ;
     RECT  208.728 67.325 208.89 67.627 ;
     RECT  207.504 66.701 207.522 67.675 ;
     RECT  208.62 67.627 208.89 67.675 ;
     RECT  26.172 67.003 26.55 67.711 ;
     RECT  27.324 59.729 27.342 67.711 ;
     RECT  207.504 67.675 208.89 67.757 ;
     RECT  7.815 67.171 8.91 67.901 ;
     RECT  24.015 60.809 24.966 67.909 ;
     RECT  26.172 67.711 27.342 67.909 ;
     RECT  29.88 67.517 206.28 68.009 ;
     RECT  208.548 67.757 208.89 68.099 ;
     RECT  207.504 67.757 207.522 68.141 ;
     RECT  24.015 67.909 27.342 68.215 ;
     RECT  28.224 67.397 28.242 68.215 ;
     RECT  24.015 68.215 28.782 68.369 ;
     RECT  30.312 68.009 206.28 68.377 ;
     RECT  208.548 68.099 208.746 68.405 ;
     RECT  30.312 68.377 206.946 68.429 ;
     RECT  30.312 68.429 206.28 68.477 ;
     RECT  30.384 68.477 206.28 68.639 ;
     RECT  208.548 68.405 208.638 68.639 ;
     RECT  7.815 67.901 8.874 69.179 ;
     RECT  208.548 68.639 208.566 69.179 ;
     RECT  30.456 68.639 206.28 69.359 ;
     RECT  6.552 65.129 6.966 70.133 ;
     RECT  5.112 67.135 5.274 70.259 ;
     RECT  24.015 68.369 28.494 70.267 ;
     RECT  29.415 69.103 29.505 70.267 ;
     RECT  30.456 69.359 30.798 70.331 ;
     RECT  0.108 70.303 0.126 70.349 ;
     RECT  4.14 70.105 4.158 70.375 ;
     RECT  4.14 70.375 4.194 70.376 ;
     RECT  2.415 62.195 2.697 70.405 ;
     RECT  2.415 70.405 3.258 70.445 ;
     RECT  4.176 70.376 4.194 70.529 ;
     RECT  30.78 70.331 30.798 70.709 ;
     RECT  234.615 65.165 234.897 71.455 ;
     RECT  234.615 71.455 235.098 71.608 ;
     RECT  234 71.608 235.098 71.645 ;
     RECT  236.52 71.491 236.538 71.645 ;
     RECT  7.815 69.179 8.838 71.725 ;
     RECT  234.432 71.645 235.098 71.879 ;
     RECT  234.432 71.879 234.897 71.915 ;
     RECT  24.015 70.267 29.505 72.301 ;
     RECT  23.94 72.301 29.505 72.391 ;
     RECT  23.22 72.391 29.505 72.419 ;
     RECT  23.22 72.419 27.342 72.427 ;
     RECT  28.116 72.419 29.505 72.563 ;
     RECT  5.256 70.259 5.274 72.931 ;
     RECT  7.668 71.725 8.838 72.959 ;
     RECT  6.552 70.133 6.858 73.039 ;
     RECT  6.336 73.039 6.858 73.075 ;
     RECT  4.536 72.931 5.274 73.099 ;
     RECT  4.536 73.099 5.418 73.139 ;
     RECT  28.368 72.563 29.505 73.139 ;
     RECT  6.264 73.075 6.858 73.201 ;
     RECT  7.668 72.959 8.097 73.201 ;
     RECT  4.536 73.139 5.274 73.229 ;
     RECT  6.264 73.201 8.097 73.229 ;
     RECT  22.932 72.427 27.342 73.237 ;
     RECT  0.108 73.051 0.126 73.265 ;
     RECT  28.368 73.139 28.386 73.265 ;
     RECT  22.824 73.237 27.342 73.409 ;
     RECT  22.824 73.409 26.334 74.353 ;
     RECT  22.392 74.353 26.334 74.425 ;
     RECT  8.82 72.959 8.838 74.659 ;
     RECT  8.82 74.659 8.91 74.687 ;
     RECT  8.892 74.687 8.91 74.929 ;
     RECT  6.552 73.229 8.097 75.937 ;
     RECT  0.108 75.835 0.126 75.965 ;
     RECT  6.408 75.937 8.097 76.013 ;
     RECT  6.552 76.013 8.097 76.235 ;
     RECT  227.304 77.275 227.322 77.315 ;
     RECT  234.615 71.915 234.897 78.475 ;
     RECT  6.552 76.235 6.966 78.539 ;
     RECT  236.34 78.427 236.358 78.539 ;
     RECT  234.036 78.475 234.897 78.619 ;
     RECT  233.568 78.619 234.897 78.629 ;
     RECT  8.892 74.929 9.414 78.637 ;
     RECT  0.108 78.571 0.126 78.665 ;
     RECT  233.568 78.629 233.586 78.665 ;
     RECT  7.815 76.235 8.097 78.673 ;
     RECT  8.82 78.637 9.414 78.673 ;
     RECT  6.552 78.539 6.858 78.899 ;
     RECT  7.815 78.673 9.414 78.899 ;
     RECT  8.82 78.899 9.414 78.935 ;
     RECT  6.552 78.899 6.57 79.511 ;
     RECT  4.5 75.505 4.518 79.591 ;
     RECT  5.256 73.229 5.274 79.591 ;
     RECT  4.5 79.591 5.274 81.329 ;
     RECT  0.108 81.307 0.126 81.365 ;
     RECT  2.415 70.445 2.697 81.409 ;
     RECT  5.076 81.329 5.274 81.481 ;
     RECT  2.415 81.409 3.222 81.485 ;
     RECT  3.96 81.337 4.194 81.509 ;
     RECT  5.076 81.481 5.814 81.509 ;
     RECT  3.96 81.509 3.978 81.635 ;
     RECT  8.892 78.935 9.414 82.561 ;
     RECT  7.815 78.899 8.097 82.921 ;
     RECT  8.82 82.561 9.414 82.921 ;
     RECT  10.224 82.651 10.242 82.949 ;
     RECT  7.815 82.921 9.414 82.973 ;
     RECT  5.256 81.509 5.814 83.497 ;
     RECT  22.32 74.425 26.334 84.209 ;
     RECT  5.256 83.497 6.174 84.271 ;
     RECT  5.256 84.271 6.318 84.331 ;
     RECT  0.108 84.091 0.126 84.335 ;
     RECT  4.824 84.331 6.318 84.371 ;
     RECT  5.256 84.371 6.318 84.649 ;
     RECT  5.256 84.649 6.498 84.839 ;
     RECT  234.615 78.629 234.897 85.225 ;
     RECT  236.52 85.243 236.538 85.289 ;
     RECT  234.615 85.225 235.062 85.351 ;
     RECT  227.628 77.431 227.646 85.379 ;
     RECT  234.108 85.351 235.062 85.379 ;
     RECT  234.108 85.379 234.897 85.451 ;
     RECT  7.815 82.973 8.097 86.701 ;
     RECT  5.256 84.839 6.174 86.729 ;
     RECT  8.82 82.973 9.414 86.729 ;
     RECT  8.892 86.729 9.414 86.999 ;
     RECT  0.108 86.827 0.126 87.035 ;
     RECT  6.156 86.729 6.174 87.109 ;
     RECT  7.344 86.701 8.097 87.115 ;
     RECT  6.156 87.109 6.426 87.149 ;
     RECT  7.236 87.115 8.097 87.269 ;
     RECT  0.108 89.611 0.126 89.735 ;
     RECT  7.344 87.269 8.097 89.779 ;
     RECT  8.892 86.999 8.91 89.779 ;
     RECT  7.344 89.779 8.91 89.941 ;
     RECT  16.416 62.717 16.434 89.969 ;
     RECT  7.092 89.941 8.91 90.041 ;
     RECT  7.092 90.041 8.838 90.779 ;
     RECT  234.615 85.451 234.897 91.975 ;
     RECT  236.52 92.011 236.538 92.093 ;
     RECT  234.288 91.975 234.897 92.129 ;
     RECT  2.415 81.485 2.697 92.347 ;
     RECT  22.32 84.209 25.758 92.399 ;
     RECT  0.108 92.347 0.126 92.435 ;
     RECT  4.176 92.479 4.194 92.515 ;
     RECT  2.415 92.347 3.258 92.621 ;
     RECT  6.156 87.149 6.174 92.641 ;
     RECT  7.092 90.779 8.097 92.641 ;
     RECT  4.068 92.515 4.194 92.669 ;
     RECT  6.156 92.641 8.097 92.669 ;
     RECT  3.852 94.405 3.87 94.441 ;
     RECT  3.852 94.441 4.194 94.531 ;
     RECT  3.852 94.531 4.338 94.651 ;
     RECT  3.744 94.651 4.338 94.801 ;
     RECT  5.256 86.729 5.274 94.801 ;
     RECT  3.744 94.801 5.274 95.083 ;
     RECT  6.156 92.669 6.858 95.099 ;
     RECT  3.528 95.083 5.274 95.135 ;
     RECT  0.108 95.131 0.126 95.171 ;
     RECT  4.824 95.135 5.274 95.171 ;
     RECT  5.256 95.171 5.274 95.179 ;
     RECT  3.852 95.135 4.014 95.369 ;
     RECT  5.256 95.179 5.814 95.369 ;
     RECT  3.852 95.369 3.87 95.405 ;
     RECT  2.415 92.621 2.697 97.867 ;
     RECT  6.84 95.099 6.858 97.951 ;
     RECT  7.815 92.669 8.097 97.951 ;
     RECT  6.84 97.951 8.097 98.059 ;
     RECT  2.34 97.867 2.697 98.105 ;
     RECT  6.408 98.059 8.097 98.105 ;
     RECT  6.84 98.105 6.966 98.141 ;
     RECT  31.536 69.359 206.28 98.55 ;
     RECT  234.615 92.129 234.897 98.725 ;
     RECT  236.556 98.581 236.574 98.909 ;
     RECT  233.568 92.281 233.586 99.031 ;
     RECT  234.615 98.725 235.098 99.031 ;
     RECT  233.568 99.031 235.098 99.149 ;
     RECT  233.568 99.149 234.897 99.185 ;
     RECT  8.82 90.779 8.838 99.491 ;
     RECT  233.568 99.185 233.586 99.491 ;
     RECT  22.32 92.399 24.966 100.031 ;
     RECT  5.256 95.369 5.274 100.201 ;
     RECT  5.256 100.201 5.814 100.219 ;
     RECT  5.256 100.219 5.922 100.301 ;
     RECT  27.324 73.409 27.342 100.579 ;
     RECT  5.256 100.301 5.526 100.643 ;
     RECT  7.815 98.105 8.097 100.651 ;
     RECT  22.32 100.031 24.297 100.679 ;
     RECT  29.415 73.139 29.505 100.693 ;
     RECT  105.804 100.615 105.822 100.693 ;
     RECT  7.815 100.651 9.306 100.769 ;
     RECT  27.252 100.579 27.342 100.769 ;
     RECT  91.764 100.003 91.782 100.769 ;
     RECT  105.207 100.693 105.822 100.769 ;
     RECT  106.56 98.55 106.578 100.769 ;
     RECT  112.068 99.463 112.086 100.769 ;
     RECT  112.824 99.463 112.842 100.769 ;
     RECT  0.108 100.651 0.126 100.805 ;
     RECT  7.815 100.769 8.838 100.841 ;
     RECT  6.948 98.141 6.966 100.849 ;
     RECT  6.84 100.849 6.966 100.877 ;
     RECT  35.007 100.693 35.097 100.963 ;
     RECT  40.407 100.693 40.497 100.963 ;
     RECT  45.807 100.693 45.897 100.963 ;
     RECT  51.207 100.693 51.297 100.963 ;
     RECT  56.607 100.693 56.697 100.963 ;
     RECT  62.007 100.693 62.097 100.963 ;
     RECT  67.407 100.693 67.497 100.963 ;
     RECT  72.807 100.693 72.897 100.963 ;
     RECT  78.207 100.693 78.297 100.963 ;
     RECT  83.607 100.693 83.697 100.963 ;
     RECT  89.007 100.693 89.097 100.963 ;
     RECT  94.407 100.693 94.497 100.963 ;
     RECT  99.807 100.693 99.897 100.963 ;
     RECT  105.207 100.769 105.297 100.963 ;
     RECT  110.607 100.693 110.697 100.963 ;
     RECT  116.007 100.693 116.097 100.963 ;
     RECT  121.407 100.693 121.497 100.963 ;
     RECT  126.807 100.693 126.897 100.963 ;
     RECT  132.207 100.693 132.297 100.963 ;
     RECT  137.607 100.693 137.697 100.963 ;
     RECT  143.007 100.693 143.097 100.963 ;
     RECT  148.407 100.693 148.497 100.963 ;
     RECT  153.807 100.693 153.897 100.963 ;
     RECT  159.207 100.693 159.297 100.963 ;
     RECT  164.607 100.693 164.697 100.963 ;
     RECT  170.007 100.693 170.097 100.963 ;
     RECT  175.407 100.693 175.497 100.963 ;
     RECT  180.807 100.693 180.897 100.963 ;
     RECT  186.207 100.693 186.297 100.963 ;
     RECT  191.607 100.693 191.697 100.963 ;
     RECT  197.007 100.693 197.097 100.963 ;
     RECT  202.407 100.693 202.497 100.963 ;
     RECT  207.807 100.693 207.897 100.963 ;
     RECT  20.592 61.349 20.61 101.039 ;
     RECT  8.82 100.841 8.838 101.075 ;
     RECT  79.992 101.191 80.01 101.453 ;
     RECT  17.136 90.013 17.154 101.849 ;
     RECT  11.844 67.559 11.862 102.389 ;
     RECT  4.5 103.351 4.518 103.469 ;
     RECT  0.108 103.387 0.126 103.505 ;
     RECT  2.415 98.105 2.697 103.549 ;
     RECT  2.415 103.549 3.222 103.613 ;
     RECT  3.96 103.477 4.194 103.775 ;
     RECT  4.392 104.299 4.41 104.549 ;
     RECT  32.58 102.541 32.598 104.549 ;
     RECT  132.015 100.963 132.297 104.701 ;
     RECT  4.752 104.701 4.77 104.765 ;
     RECT  236.52 105.691 236.538 105.737 ;
     RECT  234.615 99.185 234.897 105.745 ;
     RECT  234.615 105.745 235.098 105.871 ;
     RECT  130.536 102.001 130.554 105.899 ;
     RECT  234.216 105.871 235.098 105.899 ;
     RECT  234.216 105.899 234.897 105.971 ;
     RECT  5.508 100.643 5.526 106.051 ;
     RECT  6.84 100.877 6.858 106.051 ;
     RECT  6.84 106.051 6.966 106.079 ;
     RECT  5.508 106.051 5.814 106.123 ;
     RECT  4.86 106.123 5.814 106.169 ;
     RECT  22.896 100.679 24.297 106.169 ;
     RECT  0.108 106.123 0.126 106.205 ;
     RECT  5.508 106.169 5.814 106.241 ;
     RECT  6.948 106.079 6.966 108.859 ;
     RECT  6.408 108.859 6.966 108.877 ;
     RECT  7.815 100.841 8.097 108.877 ;
     RECT  6.408 108.877 8.097 108.905 ;
     RECT  0.108 108.904 0.126 108.941 ;
     RECT  6.948 108.905 8.097 109.175 ;
     RECT  2.415 103.613 2.697 111.643 ;
     RECT  25.74 92.399 25.758 111.839 ;
     RECT  2.415 111.643 2.754 111.875 ;
     RECT  7.815 109.175 8.097 111.919 ;
     RECT  8.82 111.685 8.838 111.919 ;
     RECT  7.815 111.919 8.838 111.983 ;
     RECT  7.815 111.983 8.586 112.109 ;
     RECT  234.615 105.971 234.897 112.351 ;
     RECT  234.576 112.351 234.897 112.451 ;
     RECT  236.52 112.495 236.538 112.541 ;
     RECT  92.088 100.921 92.106 112.649 ;
     RECT  233.856 112.495 233.874 112.649 ;
     RECT  22.932 106.169 24.297 114.539 ;
     RECT  0.108 114.427 0.126 114.575 ;
     RECT  4.176 114.619 4.194 114.655 ;
     RECT  2.415 111.875 2.697 114.691 ;
     RECT  2.415 114.691 3.258 114.749 ;
     RECT  3.996 114.655 4.194 114.809 ;
     RECT  5.508 106.241 5.526 116.875 ;
     RECT  4.824 116.875 5.526 117.121 ;
     RECT  22.932 114.539 23.13 117.239 ;
     RECT  0.108 117.163 0.126 117.275 ;
     RECT  4.824 117.121 5.814 117.311 ;
     RECT  5.508 117.311 5.814 117.347 ;
     RECT  5.508 117.347 5.598 117.509 ;
     RECT  234.615 112.451 234.897 119.101 ;
     RECT  234.615 119.101 235.098 119.201 ;
     RECT  234.615 119.201 234.897 119.281 ;
     RECT  234.432 119.281 234.897 119.371 ;
     RECT  131.508 104.701 132.297 119.399 ;
     RECT  237.492 119.101 237.51 119.405 ;
     RECT  234.108 119.371 234.897 119.471 ;
     RECT  23.004 117.239 23.13 119.939 ;
     RECT  0.108 119.947 0.126 119.984 ;
     RECT  6.948 109.175 6.966 120.055 ;
     RECT  7.815 112.109 8.097 120.055 ;
     RECT  6.408 120.055 8.097 120.209 ;
     RECT  6.408 120.209 6.966 120.269 ;
     RECT  23.004 119.939 23.058 122.639 ;
     RECT  0.54 122.647 0.558 122.717 ;
     RECT  6.948 120.269 6.966 122.719 ;
     RECT  7.815 120.209 8.097 122.719 ;
     RECT  6.948 122.719 8.586 122.747 ;
     RECT  7.38 122.747 8.586 122.755 ;
     RECT  7.38 122.755 8.838 122.909 ;
     RECT  5.508 117.509 5.526 123.565 ;
     RECT  5.508 123.565 5.598 123.601 ;
     RECT  5.508 123.601 5.67 124.105 ;
     RECT  5.364 124.105 5.67 124.141 ;
     RECT  5.364 124.141 5.814 124.205 ;
     RECT  5.364 124.205 5.67 124.259 ;
     RECT  5.436 124.259 5.67 124.304 ;
     RECT  5.472 124.304 5.67 124.367 ;
     RECT  5.472 124.367 5.598 124.529 ;
     RECT  5.472 124.529 5.526 124.565 ;
     RECT  4.176 122.719 4.194 125.383 ;
     RECT  3.96 125.383 4.194 125.491 ;
     RECT  23.04 122.639 23.058 125.519 ;
     RECT  0.108 125.467 0.126 125.645 ;
     RECT  3.96 125.491 4.518 125.645 ;
     RECT  2.415 114.749 2.697 125.689 ;
     RECT  2.415 125.689 3.222 125.741 ;
     RECT  4.176 125.645 4.518 125.789 ;
     RECT  234.615 119.471 234.897 125.851 ;
     RECT  234.615 125.851 235.098 125.951 ;
     RECT  234.615 125.951 234.897 125.995 ;
     RECT  234.288 125.995 234.897 126.149 ;
     RECT  237.492 125.923 237.51 126.221 ;
     RECT  80.1 125.995 80.118 126.419 ;
     RECT  80.928 126.391 80.946 126.461 ;
     RECT  233.568 126.301 233.586 126.461 ;
     RECT  4.5 125.789 4.518 126.571 ;
     RECT  4.176 126.571 4.518 126.841 ;
     RECT  5.508 124.565 5.526 126.841 ;
     RECT  4.176 126.841 5.598 126.995 ;
     RECT  4.176 126.995 5.166 127.031 ;
     RECT  4.5 127.031 5.166 127.067 ;
     RECT  29.415 100.693 29.697 127.099 ;
     RECT  5.148 127.067 5.166 127.103 ;
     RECT  2.415 125.741 2.697 127.187 ;
     RECT  7.815 122.909 8.097 127.187 ;
     RECT  13.215 66.209 13.497 127.187 ;
     RECT  18.615 64.319 18.897 127.187 ;
     RECT  24.015 114.539 24.297 127.187 ;
     RECT  28.944 127.099 29.697 127.187 ;
     RECT  34.815 100.963 35.097 127.187 ;
     RECT  40.215 100.963 40.497 127.187 ;
     RECT  45.615 100.963 45.897 127.187 ;
     RECT  51.015 100.963 51.297 127.187 ;
     RECT  56.415 100.963 56.697 127.187 ;
     RECT  61.815 100.963 62.097 127.187 ;
     RECT  67.215 100.963 67.497 127.187 ;
     RECT  72.615 100.963 72.897 127.187 ;
     RECT  78.015 100.963 78.297 127.187 ;
     RECT  83.415 100.963 83.697 127.187 ;
     RECT  88.815 100.963 89.097 127.187 ;
     RECT  94.215 100.963 94.497 127.187 ;
     RECT  99.615 100.963 99.897 127.187 ;
     RECT  105.015 100.963 105.297 127.187 ;
     RECT  110.415 100.963 110.697 127.187 ;
     RECT  115.815 100.963 116.097 127.187 ;
     RECT  121.215 100.963 121.497 127.187 ;
     RECT  126.615 100.963 126.897 127.187 ;
     RECT  132.015 119.399 132.297 127.187 ;
     RECT  137.415 100.963 137.697 127.187 ;
     RECT  142.815 100.963 143.097 127.187 ;
     RECT  148.215 100.963 148.497 127.187 ;
     RECT  153.615 100.963 153.897 127.187 ;
     RECT  159.015 100.963 159.297 127.187 ;
     RECT  164.415 100.963 164.697 127.187 ;
     RECT  169.815 100.963 170.097 127.187 ;
     RECT  175.215 100.963 175.497 127.187 ;
     RECT  180.615 100.963 180.897 127.187 ;
     RECT  186.015 100.963 186.297 127.187 ;
     RECT  191.415 100.963 191.697 127.187 ;
     RECT  196.815 100.963 197.097 127.187 ;
     RECT  202.215 100.963 202.497 127.187 ;
     RECT  207.615 100.963 207.897 127.187 ;
     RECT  213.015 41.165 213.297 127.187 ;
     RECT  218.415 47.597 218.697 127.187 ;
     RECT  223.815 2.413 224.097 127.187 ;
     RECT  229.215 30.848 229.497 127.187 ;
     RECT  234.615 126.149 234.897 127.187 ;
     RECT  28.944 127.187 29.505 127.201 ;
     RECT  28.656 127.201 29.505 127.229 ;
     RECT  28.656 127.229 28.674 127.277 ;
     RECT  2.415 127.187 2.505 127.457 ;
     RECT  7.815 127.187 7.905 127.457 ;
     RECT  13.215 127.187 13.305 127.457 ;
     RECT  18.615 127.187 18.705 127.457 ;
     RECT  24.015 127.187 24.105 127.457 ;
     RECT  29.415 127.229 29.505 127.457 ;
     RECT  34.815 127.187 34.905 127.457 ;
     RECT  40.215 127.187 40.305 127.457 ;
     RECT  45.615 127.187 45.705 127.457 ;
     RECT  51.015 127.187 51.105 127.457 ;
     RECT  56.415 127.187 56.505 127.457 ;
     RECT  61.815 127.187 61.905 127.457 ;
     RECT  67.215 127.187 67.305 127.457 ;
     RECT  72.615 127.187 72.705 127.457 ;
     RECT  78.015 127.187 78.105 127.457 ;
     RECT  83.415 127.187 83.505 127.457 ;
     RECT  88.815 127.187 88.905 127.457 ;
     RECT  94.215 127.187 94.305 127.457 ;
     RECT  99.615 127.187 99.705 127.457 ;
     RECT  105.015 127.187 105.105 127.457 ;
     RECT  110.415 127.187 110.505 127.457 ;
     RECT  115.815 127.187 115.905 127.457 ;
     RECT  121.215 127.187 121.305 127.457 ;
     RECT  126.615 127.187 126.705 127.457 ;
     RECT  132.015 127.187 132.105 127.457 ;
     RECT  137.415 127.187 137.505 127.457 ;
     RECT  142.815 127.187 142.905 127.457 ;
     RECT  148.215 127.187 148.305 127.457 ;
     RECT  153.615 127.187 153.705 127.457 ;
     RECT  159.015 127.187 159.105 127.457 ;
     RECT  164.415 127.187 164.505 127.457 ;
     RECT  169.815 127.187 169.905 127.457 ;
     RECT  175.215 127.187 175.305 127.457 ;
     RECT  180.615 127.187 180.705 127.457 ;
     RECT  186.015 127.187 186.105 127.457 ;
     RECT  191.415 127.187 191.505 127.457 ;
     RECT  196.815 127.187 196.905 127.457 ;
     RECT  202.215 127.187 202.305 127.457 ;
     RECT  207.615 127.187 207.705 127.457 ;
     RECT  213.015 127.187 213.105 127.457 ;
     RECT  218.415 127.187 218.505 127.457 ;
     RECT  223.815 127.187 223.905 127.457 ;
     RECT  229.215 127.187 229.305 127.457 ;
     RECT  234.615 127.187 234.705 127.457 ;
     RECT  0.108 127.075 0.126 128.237 ;
    LAYER M4 ;
     RECT  2.408 1.344 2.512 127.452 ;
     RECT  2.512 2.418 2.704 127.182 ;
     RECT  2.704 111.648 2.765 111.672 ;
     RECT  2.704 81.456 3.251 81.48 ;
     RECT  2.704 92.352 3.269 92.616 ;
     RECT  2.704 59.28 3.277 59.304 ;
     RECT  2.704 70.416 3.292 70.44 ;
     RECT  3.269 92.592 3.299 92.616 ;
     RECT  2.704 103.584 3.299 103.608 ;
     RECT  2.704 114.72 3.299 114.744 ;
     RECT  2.512 1.344 3.305 1.368 ;
     RECT  2.704 48.288 3.388 48.312 ;
     RECT  2.704 94.8 3.733 95.112 ;
     RECT  3.733 33.552 3.769 33.672 ;
     RECT  3.733 94.656 3.841 95.112 ;
     RECT  3.841 94.416 3.877 95.112 ;
     RECT  3.877 94.416 3.925 95.16 ;
     RECT  3.925 94.416 3.971 95.208 ;
     RECT  3.971 94.656 4.025 95.208 ;
     RECT  3.98 2.496 4.067 2.52 ;
     RECT  2.704 125.712 4.165 125.736 ;
     RECT  4.025 94.656 4.169 95.16 ;
     RECT  4.165 125.712 4.211 126.6 ;
     RECT  4.211 126.576 4.249 126.6 ;
     RECT  4.169 94.704 4.349 95.16 ;
     RECT  3.769 33.552 4.451 34.344 ;
     RECT  4.021 12.528 4.547 12.552 ;
     RECT  3.913 23.952 4.547 23.976 ;
     RECT  4.451 33.552 4.601 34.2 ;
     RECT  4.381 104.304 4.7 104.328 ;
     RECT  4.165 124.176 4.741 124.2 ;
     RECT  4.349 95.136 4.787 95.16 ;
     RECT  4.7 104.304 4.787 104.76 ;
     RECT  2.704 37.44 4.853 37.464 ;
     RECT  2.704 51.264 4.853 51.288 ;
     RECT  2.704 84.336 4.853 84.36 ;
     RECT  2.704 116.88 4.853 116.904 ;
     RECT  4.849 26.208 5.353 26.232 ;
     RECT  4.741 124.176 5.465 124.296 ;
     RECT  5.353 25.44 5.747 26.232 ;
     RECT  5.281 39.12 5.747 39.144 ;
     RECT  4.787 104.304 5.843 104.328 ;
     RECT  5.317 84.384 5.893 84.408 ;
     RECT  5.747 25.44 6.185 26.136 ;
     RECT  5.701 42.48 6.227 42.504 ;
     RECT  5.893 84.384 6.277 84.984 ;
     RECT  6.277 84.288 6.323 84.984 ;
     RECT  6.323 84.288 6.364 84.888 ;
     RECT  4.813 4.512 6.371 4.536 ;
     RECT  6.181 53.568 6.437 53.592 ;
     RECT  4.813 15.216 6.467 15.24 ;
     RECT  6.037 17.952 6.467 17.976 ;
     RECT  4.849 62.352 6.467 62.376 ;
     RECT  6.38 64.992 6.467 65.016 ;
     RECT  5.389 73.104 6.467 73.128 ;
     RECT  6.38 75.984 6.467 76.008 ;
     RECT  6.364 84.768 6.467 84.888 ;
     RECT  6.38 87.12 6.467 87.144 ;
     RECT  6.38 98.064 6.467 98.088 ;
     RECT  4.849 106.128 6.467 106.152 ;
     RECT  6.397 108.864 6.481 108.888 ;
     RECT  6.325 6.816 6.501 6.84 ;
     RECT  6.397 120.24 6.563 120.264 ;
     RECT  5.465 124.176 6.563 124.2 ;
     RECT  6.397 28.992 6.757 29.016 ;
     RECT  6.716 32.448 6.803 32.472 ;
     RECT  5.749 35.904 6.803 35.928 ;
     RECT  7.153 37.632 7.189 37.656 ;
     RECT  4.601 34.176 7.297 34.2 ;
     RECT  7.189 37.536 7.297 37.656 ;
     RECT  7.297 37.536 7.333 37.704 ;
     RECT  7.117 39.072 7.369 39.096 ;
     RECT  6.185 26.112 7.573 26.136 ;
     RECT  6.829 32.304 7.621 32.328 ;
     RECT  7.369 39.072 7.657 39.24 ;
     RECT  7.541 45.024 7.669 45.048 ;
     RECT  5.797 90.528 7.693 90.552 ;
     RECT  7.693 90.528 7.765 90.648 ;
     RECT  7.573 25.824 7.808 26.136 ;
     RECT  6.757 28.848 7.808 29.016 ;
     RECT  7.621 31.968 7.808 32.328 ;
     RECT  7.297 33.6 7.808 34.2 ;
     RECT  7.292 36.432 7.808 36.456 ;
     RECT  7.333 37.536 7.808 37.752 ;
     RECT  7.657 39.072 7.808 39.288 ;
     RECT  6.937 40.32 7.808 40.344 ;
     RECT  7.657 41.952 7.808 41.976 ;
     RECT  7.669 45.024 7.808 45.72 ;
     RECT  7.669 55.968 7.808 55.992 ;
     RECT  6.467 84.864 7.808 84.888 ;
     RECT  7.765 90.048 7.808 90.648 ;
     RECT  5.756 100.224 7.808 100.248 ;
     RECT  6.517 122.784 7.808 122.808 ;
     RECT  7.808 2.148 7.912 127.452 ;
     RECT  7.912 2.418 8.104 127.182 ;
     RECT  8.104 89.808 8.237 90.648 ;
     RECT  8.104 21.072 8.243 21.096 ;
     RECT  8.104 28.992 8.243 29.016 ;
     RECT  8.104 67.68 8.243 67.704 ;
     RECT  8.104 78.624 8.243 78.648 ;
     RECT  8.104 111.744 8.243 111.768 ;
     RECT  8.104 35.904 8.245 35.928 ;
     RECT  8.237 89.808 8.417 90.6 ;
     RECT  8.104 100.224 8.435 100.824 ;
     RECT  8.417 90 8.461 90.6 ;
     RECT  8.104 33.6 8.553 33.864 ;
     RECT  8.104 37.824 8.597 39.912 ;
     RECT  8.461 90 8.633 90.024 ;
     RECT  8.104 10.224 8.963 10.248 ;
     RECT  8.104 27.792 9.004 27.816 ;
     RECT  8.104 31.872 9.021 32.472 ;
     RECT  8.597 38.64 9.155 39.912 ;
     RECT  8.553 33.84 9.491 33.864 ;
     RECT  9.155 38.64 9.491 39.624 ;
     RECT  8.104 40.944 9.673 42.12 ;
     RECT  9.673 40.896 9.709 42.12 ;
     RECT  9.404 36.864 9.889 36.888 ;
     RECT  9.889 36.864 10.105 37.08 ;
     RECT  9.709 40.896 10.145 42.552 ;
     RECT  10.105 36.528 10.213 37.08 ;
     RECT  8.104 82.944 10.213 82.968 ;
     RECT  8.435 100.224 10.259 100.248 ;
     RECT  10.213 82.656 10.297 82.968 ;
     RECT  10.213 36.432 10.321 37.08 ;
     RECT  9.491 39.6 10.393 39.624 ;
     RECT  10.145 42.384 10.433 42.552 ;
     RECT  10.321 36.432 10.748 37.56 ;
     RECT  10.748 36.384 10.789 37.56 ;
     RECT  10.393 39.6 10.796 39.816 ;
     RECT  9.021 32.448 10.825 32.472 ;
     RECT  10.825 32.208 10.837 32.472 ;
     RECT  10.789 36.384 10.837 37.656 ;
     RECT  10.145 40.896 10.865 41.4 ;
     RECT  10.796 38.688 10.883 39.816 ;
     RECT  10.837 35.808 10.901 37.656 ;
     RECT  10.501 43.344 10.933 43.368 ;
     RECT  10.901 37.536 10.937 37.656 ;
     RECT  10.865 41.184 10.937 41.4 ;
     RECT  10.901 35.808 10.973 36.552 ;
     RECT  10.933 43.344 11.077 43.944 ;
     RECT  11.077 43.344 11.113 44.472 ;
     RECT  10.973 36.528 11.117 36.552 ;
     RECT  10.883 39.792 11.117 39.816 ;
     RECT  8.104 25.968 11.125 26.04 ;
     RECT  11.113 43.344 11.197 45.048 ;
     RECT  11.125 25.728 11.221 26.04 ;
     RECT  11.197 43.344 11.267 44.472 ;
     RECT  10.837 31.776 11.441 32.472 ;
     RECT  11.267 43.344 11.581 43.944 ;
     RECT  11.581 43.104 12.053 43.944 ;
     RECT  10.937 37.536 12.157 37.56 ;
     RECT  11.329 41.472 12.229 41.496 ;
     RECT  10.883 38.736 12.337 38.76 ;
     RECT  12.053 43.92 12.373 43.944 ;
     RECT  12.337 38.544 12.517 38.76 ;
     RECT  12.013 36.336 12.553 36.36 ;
     RECT  12.517 38.544 12.661 39.24 ;
     RECT  12.157 37.488 12.949 37.56 ;
     RECT  12.661 38.544 12.949 39.624 ;
     RECT  12.373 43.92 12.985 44.472 ;
     RECT  11.441 32.448 13.093 32.472 ;
     RECT  11.221 25.728 13.208 26.088 ;
     RECT  11.293 28.944 13.208 28.968 ;
     RECT  13.093 32.304 13.208 32.472 ;
     RECT  12.553 36 13.208 36.36 ;
     RECT  12.949 37.488 13.208 39.624 ;
     RECT  12.229 40.608 13.208 41.496 ;
     RECT  12.985 43.92 13.208 44.952 ;
     RECT  10.213 64.32 13.208 64.344 ;
     RECT  10.297 82.944 13.208 82.968 ;
     RECT  8.104 84.864 13.208 84.888 ;
     RECT  13.208 2.148 13.312 127.452 ;
     RECT  13.312 2.418 13.504 127.182 ;
     RECT  13.504 32.304 13.619 32.328 ;
     RECT  13.504 36.336 13.645 36.456 ;
     RECT  13.504 44.352 14.069 44.472 ;
     RECT  13.504 40.608 14.105 43.032 ;
     RECT  14.069 44.352 14.141 44.424 ;
     RECT  14.105 41.472 14.393 43.032 ;
     RECT  13.504 27.792 14.531 27.816 ;
     RECT  13.504 37.584 14.677 39.624 ;
     RECT  13.504 48.672 15.164 48.696 ;
     RECT  14.141 44.352 15.212 44.376 ;
     RECT  14.605 45.6 15.212 45.624 ;
     RECT  13.645 36.336 15.251 36.36 ;
     RECT  15.164 48.672 15.251 48.84 ;
     RECT  14.677 37.584 15.253 39.816 ;
     RECT  15.212 44.352 15.299 45.624 ;
     RECT  15.205 62.16 15.401 62.184 ;
     RECT  15.253 37.584 15.473 39.912 ;
     RECT  14.485 35.328 15.545 35.352 ;
     RECT  15.473 37.584 15.617 39.816 ;
     RECT  15.299 45.6 16.157 45.624 ;
     RECT  14.393 41.472 16.261 42.744 ;
     RECT  15.299 44.352 16.333 44.376 ;
     RECT  16.333 44.352 16.513 44.76 ;
     RECT  16.261 41.424 16.553 42.744 ;
     RECT  16.585 35.568 16.765 35.592 ;
     RECT  13.504 82.944 16.979 82.968 ;
     RECT  16.901 62.688 16.985 62.712 ;
     RECT  15.251 48.672 17.053 48.696 ;
     RECT  16.553 41.424 17.057 42.312 ;
     RECT  16.909 45.84 17.089 46.104 ;
     RECT  15.617 37.584 17.165 39.624 ;
     RECT  16.513 44.064 17.269 44.76 ;
     RECT  17.269 44.064 17.845 44.808 ;
     RECT  17.089 45.84 17.845 46.632 ;
     RECT  17.165 37.92 17.989 39.624 ;
     RECT  17.845 43.92 18.229 44.808 ;
     RECT  17.057 41.472 18.421 42.312 ;
     RECT  18.229 43.776 18.421 44.808 ;
     RECT  16.765 35.28 18.469 35.592 ;
     RECT  18.421 41.472 18.469 44.808 ;
     RECT  17.845 45.84 18.469 46.776 ;
     RECT  18.469 35.28 18.565 36.36 ;
     RECT  13.504 25.728 18.608 26.088 ;
     RECT  13.504 28.944 18.608 28.968 ;
     RECT  18.565 34.752 18.608 36.36 ;
     RECT  17.989 37.92 18.608 40.344 ;
     RECT  18.469 41.472 18.608 46.776 ;
     RECT  17.053 47.76 18.608 48.696 ;
     RECT  18.608 2.148 18.712 127.452 ;
     RECT  18.712 2.418 18.904 127.182 ;
     RECT  18.904 36.336 19.001 44.76 ;
     RECT  18.904 47.856 19.829 48.696 ;
     RECT  19.001 39.504 20.041 44.76 ;
     RECT  20.041 39.504 20.185 45.72 ;
     RECT  19.829 48.384 20.185 48.696 ;
     RECT  20.185 48.384 20.225 49.608 ;
     RECT  19.897 54.96 20.293 54.984 ;
     RECT  20.225 48.672 20.341 49.608 ;
     RECT  20.341 48.672 20.483 49.704 ;
     RECT  19.001 36.336 20.545 38.52 ;
     RECT  20.185 39.504 20.545 46.2 ;
     RECT  18.904 33.552 20.581 35.304 ;
     RECT  20.293 54.672 20.653 54.984 ;
     RECT  20.581 33.024 20.675 35.304 ;
     RECT  20.545 36.336 20.941 46.2 ;
     RECT  20.341 47.184 20.941 47.208 ;
     RECT  20.941 36.336 21.085 47.208 ;
     RECT  20.509 50.736 21.107 50.76 ;
     RECT  20.675 33.552 21.301 35.304 ;
     RECT  21.085 36.336 21.301 47.4 ;
     RECT  20.149 32.016 21.445 32.04 ;
     RECT  20.483 48.672 21.449 49.224 ;
     RECT  20.653 52.272 21.805 52.296 ;
     RECT  21.788 49.968 21.875 49.992 ;
     RECT  21.805 51.312 21.889 52.296 ;
     RECT  21.445 32.016 22.525 32.232 ;
     RECT  21.301 33.552 22.529 47.4 ;
     RECT  18.904 28.944 22.741 29.928 ;
     RECT  22.525 31.152 22.741 32.232 ;
     RECT  22.741 28.944 22.853 32.232 ;
     RECT  22.741 50.256 23.353 50.28 ;
     RECT  23.353 50.256 23.641 50.376 ;
     RECT  23.641 50.112 23.653 50.376 ;
     RECT  22.529 33.552 23.756 47.064 ;
     RECT  21.449 48.672 23.756 48.936 ;
     RECT  23.653 50.112 23.965 50.76 ;
     RECT  23.029 23.28 24.008 23.304 ;
     RECT  18.904 25.728 24.008 26.088 ;
     RECT  22.853 29.04 24.008 32.232 ;
     RECT  23.756 33.552 24.008 48.936 ;
     RECT  23.965 50.112 24.008 50.952 ;
     RECT  21.889 52.272 24.008 52.296 ;
     RECT  20.653 54.672 24.008 55.56 ;
     RECT  23.749 73.248 24.008 73.272 ;
     RECT  20.341 127.104 24.008 127.128 ;
     RECT  24.008 2.148 24.112 127.452 ;
     RECT  24.112 2.418 24.304 127.182 ;
     RECT  24.304 73.248 24.581 73.272 ;
     RECT  24.304 29.04 25.049 52.296 ;
     RECT  25.049 52.272 25.657 52.296 ;
     RECT  25.049 29.04 25.669 50.664 ;
     RECT  25.669 28.416 25.756 50.664 ;
     RECT  25.756 29.04 26.053 50.664 ;
     RECT  25.657 52.272 26.269 52.968 ;
     RECT  26.269 52.272 26.3 53.448 ;
     RECT  26.053 29.04 26.309 50.76 ;
     RECT  26.309 29.04 26.381 48.84 ;
     RECT  26.381 29.04 26.417 39.096 ;
     RECT  26.161 67.008 26.485 67.032 ;
     RECT  26.309 50.16 26.633 50.76 ;
     RECT  26.3 51.792 26.737 53.448 ;
     RECT  24.304 54.672 26.737 55.56 ;
     RECT  26.417 29.04 26.773 32.232 ;
     RECT  26.633 50.16 27.349 50.568 ;
     RECT  26.417 33.552 27.404 39.096 ;
     RECT  26.381 40.128 27.404 48.84 ;
     RECT  27.349 50.064 27.404 50.568 ;
     RECT  27.404 40.128 27.491 50.568 ;
     RECT  26.773 28.8 27.5 32.232 ;
     RECT  27.404 33.552 27.5 39.144 ;
     RECT  27.5 28.8 27.587 39.144 ;
     RECT  27.587 33.456 27.637 39.144 ;
     RECT  27.491 40.128 27.637 48.84 ;
     RECT  27.637 33.456 28.073 48.84 ;
     RECT  27.061 68.352 28.177 68.376 ;
     RECT  28.177 68.304 28.249 68.376 ;
     RECT  24.304 23.28 28.261 23.304 ;
     RECT  28.073 36.336 28.361 48.84 ;
     RECT  27.491 49.872 28.393 50.568 ;
     RECT  26.737 51.6 28.393 55.56 ;
     RECT  28.429 57.168 28.465 57.192 ;
     RECT  28.249 68.256 28.465 68.376 ;
     RECT  24.304 127.104 28.645 127.128 ;
     RECT  24.304 25.728 28.741 26.088 ;
     RECT  28.361 39.6 29.077 48.84 ;
     RECT  28.393 49.872 29.077 55.56 ;
     RECT  28.465 57.168 29.113 57.672 ;
     RECT  29.113 64.08 29.221 64.104 ;
     RECT  29.113 57.168 29.257 58.152 ;
     RECT  29.257 57.024 29.329 58.152 ;
     RECT  28.261 23.28 29.408 23.352 ;
     RECT  28.741 25.488 29.408 26.088 ;
     RECT  27.587 28.8 29.408 32.232 ;
     RECT  28.073 33.456 29.408 35.304 ;
     RECT  29.329 57.024 29.408 58.248 ;
     RECT  29.329 59.376 29.408 59.4 ;
     RECT  29.221 64.08 29.408 64.488 ;
     RECT  26.485 66.864 29.408 67.032 ;
     RECT  28.465 68.256 29.408 68.424 ;
     RECT  28.897 70.272 29.408 70.296 ;
     RECT  28.645 127.104 29.408 127.272 ;
     RECT  29.408 2.148 29.512 35.304 ;
     RECT  29.408 57.024 29.512 59.4 ;
     RECT  29.408 66.864 29.512 127.452 ;
     RECT  29.512 2.418 29.704 26.088 ;
     RECT  29.512 100.698 29.704 127.272 ;
     RECT  28.361 36.336 29.761 38.52 ;
     RECT  29.077 39.6 29.761 55.56 ;
     RECT  29.005 62.064 30.157 62.088 ;
     RECT  29.408 63.168 30.157 64.488 ;
     RECT  29.512 59.376 30.193 59.4 ;
     RECT  30.157 61.104 30.193 64.488 ;
     RECT  28.213 65.52 30.193 65.544 ;
     RECT  30.193 59.376 30.229 59.832 ;
     RECT  30.193 61.008 30.229 65.544 ;
     RECT  29.761 36.336 30.265 55.56 ;
     RECT  29.512 57.024 30.301 58.248 ;
     RECT  30.229 59.376 30.301 65.544 ;
     RECT  29.512 66.864 30.301 68.424 ;
     RECT  30.265 36.336 30.445 55.896 ;
     RECT  30.301 56.976 30.445 58.248 ;
     RECT  30.445 36.336 30.517 58.248 ;
     RECT  30.301 59.376 30.517 68.424 ;
     RECT  30.517 36.336 30.769 68.424 ;
     RECT  29.512 28.8 31.309 32.232 ;
     RECT  29.512 33.264 31.309 35.304 ;
     RECT  30.769 36.336 31.309 68.616 ;
     RECT  29.704 25.488 31.477 26.088 ;
     RECT  31.309 28.8 31.608 68.616 ;
     RECT  29.512 70.272 31.608 70.296 ;
     RECT  29.704 23.28 34.808 23.352 ;
     RECT  31.477 25.44 34.808 26.088 ;
     RECT  29.704 127.248 34.808 127.272 ;
     RECT  34.808 2.148 34.912 26.088 ;
     RECT  34.808 100.968 34.912 127.452 ;
     RECT  34.912 100.968 35 127.272 ;
     RECT  34.912 2.418 35.104 26.088 ;
     RECT  35 100.698 35.104 127.272 ;
     RECT  35.104 23.28 40.208 23.352 ;
     RECT  35.104 25.44 40.208 26.088 ;
     RECT  35.104 127.248 40.208 127.272 ;
     RECT  40.208 2.148 40.312 26.088 ;
     RECT  40.208 100.968 40.312 127.452 ;
     RECT  40.312 100.968 40.4 127.272 ;
     RECT  40.312 2.418 40.504 26.088 ;
     RECT  40.4 100.698 40.504 127.272 ;
     RECT  40.504 23.28 45.608 23.352 ;
     RECT  40.504 25.44 45.608 26.088 ;
     RECT  40.504 127.248 45.608 127.272 ;
     RECT  45.608 2.148 45.712 26.088 ;
     RECT  45.608 100.968 45.712 127.452 ;
     RECT  45.712 100.968 45.8 127.272 ;
     RECT  45.712 2.418 45.904 26.088 ;
     RECT  45.8 100.698 45.904 127.272 ;
     RECT  45.904 23.28 49.745 23.352 ;
     RECT  49.745 23.28 51.008 23.304 ;
     RECT  45.904 25.44 51.008 26.088 ;
     RECT  45.904 127.248 51.008 127.272 ;
     RECT  51.008 2.148 51.112 26.088 ;
     RECT  51.008 100.968 51.112 127.452 ;
     RECT  51.112 100.968 51.2 127.272 ;
     RECT  51.112 2.418 51.304 26.088 ;
     RECT  51.2 100.698 51.304 127.272 ;
     RECT  51.304 23.28 56.408 23.304 ;
     RECT  51.304 25.44 56.408 26.088 ;
     RECT  51.304 127.248 56.408 127.272 ;
     RECT  56.408 2.148 56.512 26.088 ;
     RECT  56.408 100.968 56.512 127.452 ;
     RECT  56.512 100.968 56.6 127.272 ;
     RECT  56.512 2.418 56.704 26.088 ;
     RECT  56.6 100.698 56.704 127.272 ;
     RECT  56.704 23.28 61.808 23.304 ;
     RECT  56.704 25.44 61.808 26.088 ;
     RECT  56.704 127.248 61.808 127.272 ;
     RECT  61.808 2.148 61.912 26.088 ;
     RECT  61.808 100.968 61.912 127.452 ;
     RECT  61.912 100.968 62 127.272 ;
     RECT  61.912 2.418 62.104 26.088 ;
     RECT  62 100.698 62.104 127.272 ;
     RECT  62.104 25.44 65.509 26.088 ;
     RECT  62.104 23.28 67.208 23.304 ;
     RECT  65.509 24.912 67.208 26.088 ;
     RECT  62.104 127.248 67.208 127.272 ;
     RECT  67.208 2.148 67.312 26.088 ;
     RECT  67.208 100.968 67.312 127.452 ;
     RECT  67.312 100.968 67.4 127.272 ;
     RECT  67.312 2.418 67.504 26.088 ;
     RECT  67.4 100.698 67.504 127.272 ;
     RECT  67.504 23.28 72.608 23.304 ;
     RECT  67.504 24.912 72.608 26.088 ;
     RECT  67.504 127.248 72.608 127.272 ;
     RECT  72.608 2.148 72.712 26.088 ;
     RECT  72.608 100.968 72.712 127.452 ;
     RECT  72.712 100.968 72.8 127.272 ;
     RECT  72.712 2.418 72.904 26.088 ;
     RECT  72.8 100.698 72.904 127.272 ;
     RECT  72.904 23.28 78.008 23.304 ;
     RECT  72.904 24.912 78.008 26.088 ;
     RECT  72.904 127.248 78.008 127.272 ;
     RECT  78.008 2.148 78.112 26.088 ;
     RECT  78.008 100.968 78.112 127.452 ;
     RECT  78.112 100.968 78.2 127.272 ;
     RECT  78.112 2.418 78.304 26.088 ;
     RECT  78.2 100.698 78.304 127.272 ;
     RECT  79.981 101.424 80.065 101.448 ;
     RECT  80.005 126 80.129 126.024 ;
     RECT  78.304 127.248 80.917 127.272 ;
     RECT  78.304 23.28 83.408 23.304 ;
     RECT  78.304 24.912 83.408 26.088 ;
     RECT  80.917 126.432 83.408 127.272 ;
     RECT  83.408 2.148 83.512 26.088 ;
     RECT  83.408 100.968 83.512 127.452 ;
     RECT  83.512 100.968 83.6 127.272 ;
     RECT  83.512 2.418 83.704 26.088 ;
     RECT  83.6 100.698 83.704 127.272 ;
     RECT  31.608 28.08 86.137 98.55 ;
     RECT  83.704 23.28 88.808 23.304 ;
     RECT  83.704 24.912 88.808 26.088 ;
     RECT  83.704 126.432 88.808 127.272 ;
     RECT  88.808 2.148 88.912 26.088 ;
     RECT  88.808 100.968 88.912 127.452 ;
     RECT  88.912 100.968 89 127.272 ;
     RECT  88.912 2.418 89.104 26.088 ;
     RECT  89 100.698 89.104 127.272 ;
     RECT  89.104 23.28 94.208 23.304 ;
     RECT  89.104 24.912 94.208 26.088 ;
     RECT  89.104 126.432 94.208 127.272 ;
     RECT  94.208 2.148 94.312 26.088 ;
     RECT  94.208 100.968 94.312 127.452 ;
     RECT  94.312 100.968 94.4 127.272 ;
     RECT  94.312 2.418 94.504 26.088 ;
     RECT  94.4 100.698 94.504 127.272 ;
     RECT  94.504 24.912 97.373 26.088 ;
     RECT  97.373 25.44 98.449 26.088 ;
     RECT  94.504 23.28 99.608 23.304 ;
     RECT  98.449 24.912 99.608 26.088 ;
     RECT  94.504 126.432 99.608 127.272 ;
     RECT  99.608 2.148 99.712 26.088 ;
     RECT  99.608 100.968 99.712 127.452 ;
     RECT  99.712 100.968 99.8 127.272 ;
     RECT  99.712 2.418 99.904 26.088 ;
     RECT  99.8 100.698 99.904 127.272 ;
     RECT  99.904 23.28 105.008 23.304 ;
     RECT  99.904 24.912 105.008 26.088 ;
     RECT  99.904 126.432 105.008 127.272 ;
     RECT  105.008 2.148 105.112 26.088 ;
     RECT  105.008 100.968 105.112 127.452 ;
     RECT  105.112 100.968 105.2 127.272 ;
     RECT  105.112 2.418 105.304 26.088 ;
     RECT  105.2 100.698 105.304 127.272 ;
     RECT  105.304 23.28 110.408 23.304 ;
     RECT  105.304 24.912 110.408 26.088 ;
     RECT  105.304 126.432 110.408 127.272 ;
     RECT  110.408 2.148 110.512 26.088 ;
     RECT  110.408 100.968 110.512 127.452 ;
     RECT  110.512 100.968 110.6 127.272 ;
     RECT  110.512 2.418 110.704 26.088 ;
     RECT  110.6 100.698 110.704 127.272 ;
     RECT  110.704 23.28 115.808 23.304 ;
     RECT  110.704 24.912 115.808 26.088 ;
     RECT  110.704 126.432 115.808 127.272 ;
     RECT  115.808 2.148 115.912 26.088 ;
     RECT  115.808 100.968 115.912 127.452 ;
     RECT  115.912 100.968 116 127.272 ;
     RECT  115.912 2.418 116.104 26.088 ;
     RECT  116 100.698 116.104 127.272 ;
     RECT  116.104 126.432 118.835 127.272 ;
     RECT  116.104 23.28 121.208 23.304 ;
     RECT  116.104 24.912 121.208 26.088 ;
     RECT  118.835 126.432 121.208 126.456 ;
     RECT  121.208 2.148 121.312 26.088 ;
     RECT  121.208 100.968 121.312 127.452 ;
     RECT  121.312 100.968 121.4 127.182 ;
     RECT  121.312 2.418 121.504 26.088 ;
     RECT  121.4 100.698 121.504 127.182 ;
     RECT  121.504 23.28 126.608 23.304 ;
     RECT  121.504 24.912 126.608 26.088 ;
     RECT  121.504 126.432 126.608 126.456 ;
     RECT  126.608 2.148 126.712 26.088 ;
     RECT  126.608 100.968 126.712 127.452 ;
     RECT  126.712 100.968 126.8 127.182 ;
     RECT  126.712 2.418 126.904 26.088 ;
     RECT  126.8 100.698 126.904 127.182 ;
     RECT  126.904 24.912 129.157 26.088 ;
     RECT  126.904 23.28 132.008 23.304 ;
     RECT  129.157 24.912 132.008 26.472 ;
     RECT  126.904 126.432 132.008 126.456 ;
     RECT  132.008 2.148 132.112 26.472 ;
     RECT  132.008 100.968 132.112 127.452 ;
     RECT  132.112 100.968 132.2 127.182 ;
     RECT  132.112 2.418 132.304 26.472 ;
     RECT  132.2 100.698 132.304 127.182 ;
     RECT  132.304 23.28 137.408 23.304 ;
     RECT  132.304 24.912 137.408 26.472 ;
     RECT  132.304 126.432 137.408 126.456 ;
     RECT  137.408 2.148 137.512 26.472 ;
     RECT  137.408 100.968 137.512 127.452 ;
     RECT  137.512 100.968 137.6 127.182 ;
     RECT  137.512 2.418 137.704 26.472 ;
     RECT  137.6 100.698 137.704 127.182 ;
     RECT  137.704 23.28 142.808 23.304 ;
     RECT  137.704 24.912 142.808 26.472 ;
     RECT  137.704 126.432 142.808 126.456 ;
     RECT  142.808 2.148 142.912 26.472 ;
     RECT  142.808 100.968 142.912 127.452 ;
     RECT  142.912 100.968 143 127.182 ;
     RECT  142.912 2.418 143.104 26.472 ;
     RECT  143 100.698 143.104 127.182 ;
     RECT  143.104 24.912 143.305 26.472 ;
     RECT  86.137 27.6 143.305 98.55 ;
     RECT  143.104 23.28 148.208 23.304 ;
     RECT  143.305 24.912 148.208 98.55 ;
     RECT  143.104 126.432 148.208 126.456 ;
     RECT  148.208 2.148 148.312 98.55 ;
     RECT  148.208 100.968 148.312 127.452 ;
     RECT  148.312 100.968 148.4 127.182 ;
     RECT  148.312 2.418 148.504 98.55 ;
     RECT  148.4 100.698 148.504 127.182 ;
     RECT  148.504 23.28 150.725 23.304 ;
     RECT  152.233 22.8 152.317 22.824 ;
     RECT  152.245 4.416 153.608 4.44 ;
     RECT  148.504 24.912 153.608 98.55 ;
     RECT  148.504 126.432 153.608 126.456 ;
     RECT  153.608 2.148 153.712 98.55 ;
     RECT  153.608 100.968 153.712 127.452 ;
     RECT  153.712 100.968 153.8 127.182 ;
     RECT  153.712 2.418 153.904 98.55 ;
     RECT  153.8 100.698 153.904 127.182 ;
     RECT  153.904 4.416 159.008 4.44 ;
     RECT  153.904 24.912 159.008 98.55 ;
     RECT  153.904 126.432 159.008 126.456 ;
     RECT  159.008 2.148 159.112 98.55 ;
     RECT  159.008 100.968 159.112 127.452 ;
     RECT  159.112 100.968 159.2 127.182 ;
     RECT  159.112 2.418 159.304 98.55 ;
     RECT  159.2 100.698 159.304 127.182 ;
     RECT  159.304 4.416 164.408 4.44 ;
     RECT  159.304 24.912 164.408 98.55 ;
     RECT  159.304 126.432 164.408 126.456 ;
     RECT  164.408 2.148 164.512 98.55 ;
     RECT  164.408 100.968 164.512 127.452 ;
     RECT  164.512 100.968 164.6 127.182 ;
     RECT  164.512 2.418 164.704 98.55 ;
     RECT  164.6 100.698 164.704 127.182 ;
     RECT  164.704 4.416 169.808 4.44 ;
     RECT  164.704 24.912 169.808 98.55 ;
     RECT  164.704 126.432 169.808 126.456 ;
     RECT  169.808 2.148 169.912 98.55 ;
     RECT  169.808 100.968 169.912 127.452 ;
     RECT  169.912 100.968 170 127.182 ;
     RECT  169.912 2.418 170.104 98.55 ;
     RECT  170 100.698 170.104 127.182 ;
     RECT  170.104 4.416 175.208 4.44 ;
     RECT  170.104 24.912 175.208 98.55 ;
     RECT  170.104 126.432 175.208 126.456 ;
     RECT  175.208 2.148 175.312 98.55 ;
     RECT  175.208 100.968 175.312 127.452 ;
     RECT  175.312 100.968 175.4 127.182 ;
     RECT  175.312 2.418 175.504 98.55 ;
     RECT  175.4 100.698 175.504 127.182 ;
     RECT  175.504 4.416 180.608 4.44 ;
     RECT  175.504 24.912 180.608 98.55 ;
     RECT  175.504 126.432 180.608 126.456 ;
     RECT  180.608 2.148 180.712 98.55 ;
     RECT  180.608 100.968 180.712 127.452 ;
     RECT  180.712 100.968 180.8 127.182 ;
     RECT  180.712 2.418 180.904 98.55 ;
     RECT  180.8 100.698 180.904 127.182 ;
     RECT  180.904 4.416 186.008 4.44 ;
     RECT  180.904 24.912 186.008 98.55 ;
     RECT  180.904 126.432 186.008 126.456 ;
     RECT  186.008 2.148 186.112 98.55 ;
     RECT  186.008 100.968 186.112 127.452 ;
     RECT  186.112 100.968 186.2 127.182 ;
     RECT  186.112 2.418 186.304 98.55 ;
     RECT  186.2 100.698 186.304 127.182 ;
     RECT  186.304 4.416 191.408 4.44 ;
     RECT  186.304 24.912 191.408 98.55 ;
     RECT  186.304 126.432 191.408 126.456 ;
     RECT  191.408 2.148 191.512 98.55 ;
     RECT  191.408 100.968 191.512 127.452 ;
     RECT  191.512 100.968 191.6 127.182 ;
     RECT  191.512 2.418 191.704 98.55 ;
     RECT  191.6 100.698 191.704 127.182 ;
     RECT  191.704 4.416 196.808 4.44 ;
     RECT  191.704 24.912 196.808 98.55 ;
     RECT  191.704 126.432 196.808 126.456 ;
     RECT  196.808 2.148 196.912 98.55 ;
     RECT  196.808 100.968 196.912 127.452 ;
     RECT  196.912 100.968 197 127.182 ;
     RECT  196.912 2.418 197.104 98.55 ;
     RECT  197 100.698 197.104 127.182 ;
     RECT  197.104 4.416 202.208 4.44 ;
     RECT  197.104 24.912 202.208 98.55 ;
     RECT  197.104 126.432 202.208 126.456 ;
     RECT  202.208 2.148 202.312 98.55 ;
     RECT  202.208 100.968 202.312 127.452 ;
     RECT  202.312 100.968 202.4 127.182 ;
     RECT  202.312 2.418 202.504 98.55 ;
     RECT  202.4 100.698 202.504 127.182 ;
     RECT  202.504 24.912 206.208 98.55 ;
     RECT  206.208 24.912 206.381 68.52 ;
     RECT  206.381 24.912 206.483 41.16 ;
     RECT  206.381 48.144 206.525 50.088 ;
     RECT  206.483 27.6 206.531 41.16 ;
     RECT  206.531 27.6 206.579 27.768 ;
     RECT  206.531 28.848 206.741 41.16 ;
     RECT  206.741 29.088 206.771 41.16 ;
     RECT  206.579 27.696 206.819 27.768 ;
     RECT  206.771 29.184 206.915 41.16 ;
     RECT  206.819 27.696 206.921 27.72 ;
     RECT  206.381 61.104 206.957 61.896 ;
     RECT  206.381 64.176 206.957 68.52 ;
     RECT  206.915 29.232 206.963 41.16 ;
     RECT  206.963 33.456 206.993 35.112 ;
     RECT  206.963 29.232 207.011 29.256 ;
     RECT  206.963 30.384 207.011 32.328 ;
     RECT  206.993 33.456 207.011 35.016 ;
     RECT  207.011 30.384 207.029 31.56 ;
     RECT  207.011 33.456 207.029 34.632 ;
     RECT  207.029 30.384 207.059 31.368 ;
     RECT  207.029 33.456 207.059 34.44 ;
     RECT  206.963 36.528 207.281 41.16 ;
     RECT  206.525 48.144 207.349 49.512 ;
     RECT  206.483 24.912 207.395 26.088 ;
     RECT  207.281 36.528 207.497 38.136 ;
     RECT  206.381 42.576 207.497 43.368 ;
     RECT  207.349 47.568 207.497 49.512 ;
     RECT  207.497 36.528 207.533 37.608 ;
     RECT  207.497 42.576 207.533 43.272 ;
     RECT  207.497 49.296 207.533 49.512 ;
     RECT  202.504 4.416 207.608 4.44 ;
     RECT  207.395 24.912 207.608 25.932 ;
     RECT  202.504 126.432 207.608 126.456 ;
     RECT  207.608 2.148 207.712 25.932 ;
     RECT  207.608 100.968 207.712 127.452 ;
     RECT  207.712 100.968 207.8 127.182 ;
     RECT  207.712 2.418 207.904 25.662 ;
     RECT  207.8 100.698 207.904 127.182 ;
     RECT  206.381 58.032 208.325 58.824 ;
     RECT  206.957 61.2 208.361 61.896 ;
     RECT  206.381 45.648 208.508 46.44 ;
     RECT  207.059 30.384 208.541 31.32 ;
     RECT  207.059 33.456 208.541 34.152 ;
     RECT  207.533 42.576 208.541 43.176 ;
     RECT  208.508 45.456 208.541 46.44 ;
     RECT  207.533 49.296 208.573 49.416 ;
     RECT  207.904 25.488 208.595 25.512 ;
     RECT  208.541 45.456 208.595 46.344 ;
     RECT  208.573 49.296 208.609 49.608 ;
     RECT  208.541 33.456 208.613 34.056 ;
     RECT  208.613 33.648 208.649 34.056 ;
     RECT  207.533 36.624 208.649 37.608 ;
     RECT  208.609 49.296 208.649 49.848 ;
     RECT  206.381 54.96 208.649 55.656 ;
     RECT  206.957 64.272 208.649 68.52 ;
     RECT  207.281 39.36 208.721 41.16 ;
     RECT  208.541 42.576 208.721 42.6 ;
     RECT  208.595 45.84 208.721 46.344 ;
     RECT  208.325 58.032 208.721 58.632 ;
     RECT  208.649 33.744 208.757 34.056 ;
     RECT  208.649 36.72 208.757 37.608 ;
     RECT  208.721 39.36 208.757 40.104 ;
     RECT  208.721 45.84 208.757 46.248 ;
     RECT  208.649 49.584 208.757 49.848 ;
     RECT  206.381 51.888 208.757 52.68 ;
     RECT  208.721 58.32 208.757 58.632 ;
     RECT  208.361 61.2 208.757 61.704 ;
     RECT  208.649 64.272 208.757 68.328 ;
     RECT  208.541 30.672 208.793 31.32 ;
     RECT  208.757 37.2 208.793 37.608 ;
     RECT  208.757 49.824 208.793 49.848 ;
     RECT  208.757 58.32 208.793 58.536 ;
     RECT  208.757 64.272 208.793 67.848 ;
     RECT  208.757 45.84 208.865 45.864 ;
     RECT  208.757 52.272 208.865 52.68 ;
     RECT  208.649 55.152 208.865 55.656 ;
     RECT  208.793 64.368 208.865 67.848 ;
     RECT  208.793 30.816 208.901 31.32 ;
     RECT  208.757 34.032 208.901 34.056 ;
     RECT  208.865 64.848 208.901 67.848 ;
     RECT  207.497 47.568 208.937 48.168 ;
     RECT  208.793 58.512 208.937 58.536 ;
     RECT  208.865 55.152 208.973 55.608 ;
     RECT  208.901 65.232 208.973 67.272 ;
     RECT  208.973 65.904 209.009 66.504 ;
     RECT  208.865 52.656 209.045 52.68 ;
     RECT  208.973 55.584 209.225 55.608 ;
     RECT  207.904 4.416 213.008 4.44 ;
     RECT  208.901 30.816 213.008 30.84 ;
     RECT  208.793 37.584 213.008 37.608 ;
     RECT  208.721 41.136 213.008 41.16 ;
     RECT  206.381 44.352 213.008 44.376 ;
     RECT  208.937 47.568 213.008 47.592 ;
     RECT  207.253 71.616 213.008 71.64 ;
     RECT  207.205 77.28 213.008 77.304 ;
     RECT  206.208 78.624 213.008 78.648 ;
     RECT  207.904 126.432 213.008 126.456 ;
     RECT  213.008 2.148 213.112 127.452 ;
     RECT  213.112 2.418 213.304 127.182 ;
     RECT  213.304 4.416 218.408 4.44 ;
     RECT  213.304 30.816 218.408 30.84 ;
     RECT  213.304 37.584 218.408 37.608 ;
     RECT  213.304 44.352 218.408 44.376 ;
     RECT  213.304 47.568 218.408 47.592 ;
     RECT  213.304 71.616 218.408 71.64 ;
     RECT  213.304 77.28 218.408 77.304 ;
     RECT  213.304 78.624 218.408 78.648 ;
     RECT  213.304 126.432 218.408 126.456 ;
     RECT  218.408 2.148 218.512 127.452 ;
     RECT  218.512 2.418 218.704 127.182 ;
     RECT  218.704 4.416 223.808 4.44 ;
     RECT  218.704 30.816 223.808 30.84 ;
     RECT  218.704 37.584 223.808 37.608 ;
     RECT  218.704 44.352 223.808 44.376 ;
     RECT  218.704 47.568 223.808 47.592 ;
     RECT  218.704 71.616 223.808 71.64 ;
     RECT  218.704 77.28 223.808 77.304 ;
     RECT  218.704 78.624 223.808 78.648 ;
     RECT  218.704 126.432 223.808 126.456 ;
     RECT  223.808 2.148 223.912 127.452 ;
     RECT  223.912 2.418 224.104 127.182 ;
     RECT  224.104 47.568 226.285 47.592 ;
     RECT  226.285 47.568 226.325 47.688 ;
     RECT  224.104 77.28 227.333 77.304 ;
     RECT  224.104 4.416 229.208 4.44 ;
     RECT  224.104 30.816 229.208 30.84 ;
     RECT  224.104 37.584 229.208 37.608 ;
     RECT  224.104 44.352 229.208 44.376 ;
     RECT  226.325 47.664 229.208 47.688 ;
     RECT  224.104 71.616 229.208 71.64 ;
     RECT  224.104 78.624 229.208 78.648 ;
     RECT  224.104 126.432 229.208 126.456 ;
     RECT  229.208 2.148 229.312 127.452 ;
     RECT  229.312 2.418 229.504 127.182 ;
     RECT  229.504 47.664 230.897 47.688 ;
     RECT  229.504 4.416 232.364 4.44 ;
     RECT  232.364 3.696 232.405 4.44 ;
     RECT  232.405 3.696 232.451 4.584 ;
     RECT  232.451 4.56 232.589 4.584 ;
     RECT  229.504 30.816 233.597 30.84 ;
     RECT  229.504 37.584 233.597 37.608 ;
     RECT  229.504 44.352 233.597 44.376 ;
     RECT  229.504 78.624 233.597 78.648 ;
     RECT  229.504 126.432 233.597 126.456 ;
     RECT  229.504 71.616 234.608 71.64 ;
     RECT  234.608 2.148 234.712 127.452 ;
     RECT  234.712 2.418 234.904 127.182 ;
    LAYER M5 ;
     RECT  2.4 2.137 2.52 2.151 ;
     RECT  7.8 2.137 7.92 2.151 ;
     RECT  13.2 2.137 13.32 2.151 ;
     RECT  18.6 2.137 18.72 2.151 ;
     RECT  24 2.137 24.12 2.151 ;
     RECT  29.4 2.137 29.52 2.151 ;
     RECT  34.8 2.137 34.92 2.151 ;
     RECT  40.2 2.137 40.32 2.151 ;
     RECT  45.6 2.137 45.72 2.151 ;
     RECT  51 2.137 51.12 2.151 ;
     RECT  56.4 2.137 56.52 2.151 ;
     RECT  61.8 2.137 61.92 2.151 ;
     RECT  67.2 2.137 67.32 2.151 ;
     RECT  72.6 2.137 72.72 2.151 ;
     RECT  78 2.137 78.12 2.151 ;
     RECT  83.4 2.137 83.52 2.151 ;
     RECT  88.8 2.137 88.92 2.151 ;
     RECT  94.2 2.137 94.32 2.151 ;
     RECT  99.6 2.137 99.72 2.151 ;
     RECT  105 2.137 105.12 2.151 ;
     RECT  110.4 2.137 110.52 2.151 ;
     RECT  115.8 2.137 115.92 2.151 ;
     RECT  121.2 2.137 121.32 2.151 ;
     RECT  126.6 2.137 126.72 2.151 ;
     RECT  132 2.137 132.12 2.151 ;
     RECT  137.4 2.137 137.52 2.151 ;
     RECT  142.8 2.137 142.92 2.151 ;
     RECT  148.2 2.137 148.32 2.151 ;
     RECT  153.6 2.137 153.72 2.151 ;
     RECT  159 2.137 159.12 2.151 ;
     RECT  164.4 2.137 164.52 2.151 ;
     RECT  169.8 2.137 169.92 2.151 ;
     RECT  175.2 2.137 175.32 2.151 ;
     RECT  180.6 2.137 180.72 2.151 ;
     RECT  186 2.137 186.12 2.151 ;
     RECT  191.4 2.137 191.52 2.151 ;
     RECT  196.8 2.137 196.92 2.151 ;
     RECT  202.2 2.137 202.32 2.151 ;
     RECT  207.6 2.137 207.72 2.151 ;
     RECT  213 2.137 213.12 2.151 ;
     RECT  218.4 2.137 218.52 2.151 ;
     RECT  223.8 2.137 223.92 2.151 ;
     RECT  229.2 2.137 229.32 2.151 ;
     RECT  234.6 2.137 234.72 2.151 ;
     RECT  232.416 3.685 232.44 4.595 ;
     RECT  6.336 4.501 6.36 6.805 ;
     RECT  6.336 6.805 6.456 6.851 ;
     RECT  7.8 2.151 8.112 10.213 ;
     RECT  4.032 2.485 4.056 12.517 ;
     RECT  4.032 12.517 4.536 12.563 ;
     RECT  6.432 6.851 6.456 17.941 ;
     RECT  6.048 17.941 6.456 17.987 ;
     RECT  152.256 4.405 152.28 22.835 ;
     RECT  24 2.151 24.312 23.269 ;
     RECT  4.512 12.563 4.536 23.941 ;
     RECT  4.416 23.941 4.536 23.987 ;
     RECT  207.6 2.151 207.912 24.901 ;
     RECT  28.272 23.317 28.296 25.477 ;
     RECT  29.4 2.151 29.712 25.477 ;
     RECT  206.688 24.901 207.912 25.477 ;
     RECT  206.688 25.477 208.584 25.525 ;
     RECT  6.048 17.987 6.072 25.669 ;
     RECT  5.712 25.669 6.072 25.715 ;
     RECT  65.52 24.901 65.544 25.715 ;
     RECT  31.488 25.429 31.512 25.765 ;
     RECT  7.8 10.213 8.952 25.813 ;
     RECT  206.304 25.525 208.584 25.813 ;
     RECT  11.136 25.717 11.16 26.053 ;
     RECT  205.968 25.813 208.584 27.779 ;
     RECT  7.584 25.813 8.952 28.837 ;
     RECT  25.68 28.405 25.704 29.123 ;
     RECT  28.272 25.477 29.712 31.285 ;
     RECT  11.136 26.053 11.256 31.765 ;
     RECT  26.016 29.365 26.04 31.861 ;
     RECT  6.768 28.837 8.952 31.907 ;
     RECT  13.2 2.151 13.512 32.293 ;
     RECT  14.496 27.781 14.52 32.293 ;
     RECT  23.04 23.269 24.312 32.437 ;
     RECT  13.104 32.293 14.52 32.483 ;
     RECT  206.304 27.779 208.584 32.579 ;
     RECT  26.016 31.861 26.184 32.773 ;
     RECT  27.792 31.285 29.712 32.917 ;
     RECT  23.04 32.437 24.696 33.013 ;
     RECT  26.016 32.773 26.28 33.013 ;
     RECT  6.768 31.907 8.52 33.635 ;
     RECT  20.64 33.013 20.664 34.117 ;
     RECT  23.04 33.013 26.28 34.117 ;
     RECT  27.552 32.917 29.712 34.117 ;
     RECT  206.352 32.579 208.584 34.259 ;
     RECT  4.416 23.987 4.44 34.309 ;
     RECT  3.984 34.309 4.44 34.355 ;
     RECT  20.64 34.117 21.336 35.029 ;
     RECT  206.4 34.259 208.584 35.317 ;
     RECT  18.6 2.151 18.912 35.557 ;
     RECT  6.768 33.635 8.472 35.939 ;
     RECT  20.016 35.029 21.336 35.941 ;
     RECT  20.016 35.941 21.672 35.987 ;
     RECT  13.2 32.483 14.52 35.989 ;
     RECT  13.104 35.989 14.52 36.325 ;
     RECT  10.848 31.765 11.256 36.373 ;
     RECT  9.456 33.829 9.48 36.421 ;
     RECT  10.8 36.373 11.256 36.421 ;
     RECT  206.352 35.317 208.584 36.467 ;
     RECT  9.456 36.421 11.256 37.091 ;
     RECT  20.016 35.987 20.664 37.091 ;
     RECT  22.752 34.117 29.712 37.091 ;
     RECT  2.4 2.151 2.712 37.429 ;
     RECT  3.984 34.355 4.008 37.429 ;
     RECT  206.4 36.467 208.584 37.429 ;
     RECT  2.4 37.429 4.008 37.475 ;
     RECT  21.648 35.987 21.672 37.477 ;
     RECT  22.752 37.091 22.776 37.477 ;
     RECT  13.104 36.325 15.24 37.525 ;
     RECT  10.8 37.091 11.256 37.667 ;
     RECT  7.344 35.939 8.472 37.763 ;
     RECT  21.648 37.477 22.776 38.101 ;
     RECT  23.808 37.091 29.712 38.101 ;
     RECT  7.584 37.763 8.472 38.629 ;
     RECT  9.456 37.091 9.48 38.629 ;
     RECT  7.584 38.629 9.48 38.675 ;
     RECT  11.136 37.667 11.256 38.677 ;
     RECT  20.016 37.091 20.04 39.061 ;
     RECT  21.648 38.101 29.712 39.061 ;
     RECT  7.584 38.675 9.144 39.107 ;
     RECT  12.528 37.525 15.24 39.251 ;
     RECT  206.304 37.429 208.584 39.395 ;
     RECT  13.104 39.251 15.24 39.493 ;
     RECT  20.016 39.061 29.712 39.539 ;
     RECT  10.848 38.677 11.256 39.635 ;
     RECT  13.104 39.493 15.288 39.635 ;
     RECT  9.12 39.107 9.144 39.923 ;
     RECT  20.016 39.539 20.808 40.259 ;
     RECT  206.736 39.395 208.584 40.885 ;
     RECT  20.208 40.259 20.808 40.981 ;
     RECT  21.84 39.539 29.712 40.981 ;
     RECT  17.856 35.557 18.912 41.749 ;
     RECT  20.208 40.981 29.712 42.325 ;
     RECT  5.712 25.715 5.736 42.469 ;
     RECT  5.712 42.469 6.216 42.515 ;
     RECT  19.968 42.325 29.712 42.803 ;
     RECT  20.208 42.803 29.712 42.899 ;
     RECT  21.84 42.899 29.712 43.955 ;
     RECT  20.208 42.899 20.808 44.197 ;
     RECT  21.84 43.955 22.776 44.197 ;
     RECT  206.592 40.885 208.584 44.387 ;
     RECT  13.104 39.635 13.512 44.437 ;
     RECT  11.136 39.635 11.256 44.483 ;
     RECT  20.208 44.197 22.776 44.917 ;
     RECT  23.76 43.955 29.712 44.917 ;
     RECT  7.584 39.107 8.112 45.059 ;
     RECT  11.136 44.483 11.16 45.059 ;
     RECT  15.216 39.635 15.288 45.635 ;
     RECT  20.208 44.917 29.712 45.635 ;
     RECT  23.808 45.635 29.712 45.925 ;
     RECT  31.008 25.765 31.512 45.925 ;
     RECT  20.208 45.635 22.776 46.211 ;
     RECT  23.808 45.925 31.512 46.499 ;
     RECT  20.448 46.211 22.776 47.173 ;
     RECT  16.944 41.749 18.912 47.795 ;
     RECT  207.168 44.387 208.584 47.939 ;
     RECT  23.808 46.499 29.712 48.515 ;
     RECT  207.168 47.939 207.912 48.613 ;
     RECT  206.352 48.613 207.912 48.755 ;
     RECT  20.352 47.173 22.776 50.101 ;
     RECT  24 48.515 29.712 50.101 ;
     RECT  20.352 50.101 29.712 50.195 ;
     RECT  20.352 50.195 25.032 50.291 ;
     RECT  20.352 50.291 21.864 50.771 ;
     RECT  23.664 50.291 25.032 50.771 ;
     RECT  26.064 50.195 26.616 50.771 ;
     RECT  2.4 37.475 3.336 51.299 ;
     RECT  31.008 46.499 31.512 51.299 ;
     RECT  21.84 50.771 21.864 51.347 ;
     RECT  24 50.771 25.032 51.347 ;
     RECT  27.6 50.195 29.712 51.347 ;
     RECT  26.592 50.771 26.616 51.781 ;
     RECT  26.352 51.781 26.616 51.827 ;
     RECT  24 51.347 24.696 51.923 ;
     RECT  27.6 51.347 27.624 51.923 ;
     RECT  26.352 51.827 26.376 53.075 ;
     RECT  6.192 42.515 6.216 53.603 ;
     RECT  31.44 51.299 31.512 55.621 ;
     RECT  31.344 55.621 31.512 55.907 ;
     RECT  7.68 45.059 8.112 56.003 ;
     RECT  29.28 51.347 29.712 57.059 ;
     RECT  31.392 55.907 31.512 57.349 ;
     RECT  31.296 57.349 31.512 57.539 ;
     RECT  2.4 51.299 3.24 59.315 ;
     RECT  31.296 57.539 31.464 59.797 ;
     RECT  15.216 45.635 15.24 62.195 ;
     RECT  31.296 59.797 31.512 64.981 ;
     RECT  31.248 64.981 31.512 66.565 ;
     RECT  31.152 66.565 31.512 66.755 ;
     RECT  7.8 56.003 8.112 67.669 ;
     RECT  31.152 66.755 31.464 68.387 ;
     RECT  31.2 68.387 31.464 68.627 ;
     RECT  31.2 68.627 31.224 70.307 ;
     RECT  2.4 59.315 2.712 70.405 ;
     RECT  207.168 48.755 207.912 78.659 ;
     RECT  16.944 47.795 16.968 82.979 ;
     RECT  6.432 62.341 6.456 84.277 ;
     RECT  12.384 44.437 13.512 84.899 ;
     RECT  6.288 84.277 6.456 84.995 ;
     RECT  6.432 84.995 6.456 90.517 ;
     RECT  7.8 67.669 8.232 90.565 ;
     RECT  2.4 70.405 3.24 92.581 ;
     RECT  2.4 92.581 3.288 94.405 ;
     RECT  2.4 94.405 3.96 95.125 ;
     RECT  2.4 95.125 4.776 95.219 ;
     RECT  10.224 64.309 10.248 100.259 ;
     RECT  7.8 90.565 8.424 100.835 ;
     RECT  5.808 90.517 6.456 104.339 ;
     RECT  6.432 104.339 6.456 108.899 ;
     RECT  7.8 100.835 8.232 111.779 ;
     RECT  2.4 95.219 3.288 116.915 ;
     RECT  4.752 95.219 4.776 124.165 ;
     RECT  6.528 120.229 6.552 124.211 ;
     RECT  4.176 124.165 4.776 124.307 ;
     RECT  80.016 101.413 80.04 126.035 ;
     RECT  4.176 124.307 4.2 126.611 ;
     RECT  20.352 50.771 20.376 127.139 ;
     RECT  2.4 116.915 2.712 127.449 ;
     RECT  7.8 111.779 8.112 127.449 ;
     RECT  13.2 84.899 13.512 127.449 ;
     RECT  18.6 47.795 18.912 127.449 ;
     RECT  24 51.923 24.312 127.449 ;
     RECT  29.4 57.059 29.712 127.449 ;
     RECT  34.8 2.151 35.112 127.449 ;
     RECT  40.2 2.151 40.512 127.449 ;
     RECT  45.6 2.151 45.912 127.449 ;
     RECT  51 2.151 51.312 127.449 ;
     RECT  56.4 2.151 56.712 127.449 ;
     RECT  61.8 2.151 62.112 127.449 ;
     RECT  67.2 2.151 67.512 127.449 ;
     RECT  72.6 2.151 72.912 127.449 ;
     RECT  78 2.151 78.312 127.449 ;
     RECT  83.4 2.151 83.712 127.449 ;
     RECT  88.8 2.151 89.112 127.449 ;
     RECT  94.2 2.151 94.512 127.449 ;
     RECT  99.6 2.151 99.912 127.449 ;
     RECT  105 2.151 105.312 127.449 ;
     RECT  110.4 2.151 110.712 127.449 ;
     RECT  115.8 2.151 116.112 127.449 ;
     RECT  121.2 2.151 121.512 127.449 ;
     RECT  126.6 2.151 126.912 127.449 ;
     RECT  132 2.151 132.312 127.449 ;
     RECT  137.4 2.151 137.712 127.449 ;
     RECT  142.8 2.151 143.112 127.449 ;
     RECT  148.2 2.151 148.512 127.449 ;
     RECT  153.6 2.151 153.912 127.449 ;
     RECT  159 2.151 159.312 127.449 ;
     RECT  164.4 2.151 164.712 127.449 ;
     RECT  169.8 2.151 170.112 127.449 ;
     RECT  175.2 2.151 175.512 127.449 ;
     RECT  180.6 2.151 180.912 127.449 ;
     RECT  186 2.151 186.312 127.449 ;
     RECT  191.4 2.151 191.712 127.449 ;
     RECT  196.8 2.151 197.112 127.449 ;
     RECT  202.2 2.151 202.512 127.449 ;
     RECT  207.6 78.659 207.912 127.449 ;
     RECT  213 2.151 213.312 127.449 ;
     RECT  218.4 2.151 218.712 127.449 ;
     RECT  223.8 2.151 224.112 127.449 ;
     RECT  229.2 2.151 229.512 127.449 ;
     RECT  234.6 2.151 234.912 127.449 ;
     RECT  2.4 127.449 2.52 127.463 ;
     RECT  7.8 127.449 7.92 127.463 ;
     RECT  13.2 127.449 13.32 127.463 ;
     RECT  18.6 127.449 18.72 127.463 ;
     RECT  24 127.449 24.12 127.463 ;
     RECT  29.4 127.449 29.52 127.463 ;
     RECT  34.8 127.449 34.92 127.463 ;
     RECT  40.2 127.449 40.32 127.463 ;
     RECT  45.6 127.449 45.72 127.463 ;
     RECT  51 127.449 51.12 127.463 ;
     RECT  56.4 127.449 56.52 127.463 ;
     RECT  61.8 127.449 61.92 127.463 ;
     RECT  67.2 127.449 67.32 127.463 ;
     RECT  72.6 127.449 72.72 127.463 ;
     RECT  78 127.449 78.12 127.463 ;
     RECT  83.4 127.449 83.52 127.463 ;
     RECT  88.8 127.449 88.92 127.463 ;
     RECT  94.2 127.449 94.32 127.463 ;
     RECT  99.6 127.449 99.72 127.463 ;
     RECT  105 127.449 105.12 127.463 ;
     RECT  110.4 127.449 110.52 127.463 ;
     RECT  115.8 127.449 115.92 127.463 ;
     RECT  121.2 127.449 121.32 127.463 ;
     RECT  126.6 127.449 126.72 127.463 ;
     RECT  132 127.449 132.12 127.463 ;
     RECT  137.4 127.449 137.52 127.463 ;
     RECT  142.8 127.449 142.92 127.463 ;
     RECT  148.2 127.449 148.32 127.463 ;
     RECT  153.6 127.449 153.72 127.463 ;
     RECT  159 127.449 159.12 127.463 ;
     RECT  164.4 127.449 164.52 127.463 ;
     RECT  169.8 127.449 169.92 127.463 ;
     RECT  175.2 127.449 175.32 127.463 ;
     RECT  180.6 127.449 180.72 127.463 ;
     RECT  186 127.449 186.12 127.463 ;
     RECT  191.4 127.449 191.52 127.463 ;
     RECT  196.8 127.449 196.92 127.463 ;
     RECT  202.2 127.449 202.32 127.463 ;
     RECT  207.6 127.449 207.72 127.463 ;
     RECT  213 127.449 213.12 127.463 ;
     RECT  218.4 127.449 218.52 127.463 ;
     RECT  223.8 127.449 223.92 127.463 ;
     RECT  229.2 127.449 229.32 127.463 ;
     RECT  234.6 127.449 234.72 127.463 ;
     RECT  2.712 2.485 4.032 12.563 ;
     RECT  152.28 4.405 153.6 22.835 ;
     RECT  6.36 4.501 7.8 6.805 ;
     RECT  6.456 6.805 7.8 17.987 ;
     RECT  4.536 17.941 6.048 23.987 ;
     RECT  28.296 23.317 29.4 25.477 ;
     RECT  4.44 25.669 5.712 34.355 ;
     RECT  29.712 25.765 31.008 45.925 ;
     RECT  13.512 27.781 14.496 32.293 ;
     RECT  24.312 28.405 25.68 29.123 ;
     RECT  5.736 28.837 6.768 35.939 ;
     RECT  24.696 32.437 26.016 33.013 ;
     RECT  26.28 32.773 27.792 32.917 ;
     RECT  26.28 32.917 27.552 34.117 ;
     RECT  8.472 33.635 8.52 33.829 ;
     RECT  8.472 33.829 9.456 38.629 ;
     RECT  9.48 33.829 10.848 36.373 ;
     RECT  21.336 34.117 22.752 35.941 ;
     RECT  206.352 34.259 206.4 35.317 ;
     RECT  2.712 34.309 3.984 37.429 ;
     RECT  18.912 35.029 20.016 40.259 ;
     RECT  21.672 35.941 22.752 37.477 ;
     RECT  20.664 35.987 21.648 37.091 ;
     RECT  9.48 36.373 10.8 36.421 ;
     RECT  206.352 36.467 206.4 37.429 ;
     RECT  9.48 37.091 10.8 37.667 ;
     RECT  22.776 37.091 23.808 38.101 ;
     RECT  11.256 37.525 12.528 39.251 ;
     RECT  9.48 37.667 11.136 38.675 ;
     RECT  10.848 38.675 11.136 38.677 ;
     RECT  8.112 39.107 9.12 39.923 ;
     RECT  206.592 39.395 206.736 40.885 ;
     RECT  20.808 39.539 21.84 40.981 ;
     RECT  18.912 40.259 20.208 42.325 ;
     RECT  18.912 42.325 19.968 42.803 ;
     RECT  6.216 42.469 7.584 45.059 ;
     RECT  18.912 42.803 20.208 46.211 ;
     RECT  20.808 42.899 21.84 44.197 ;
     RECT  22.776 43.955 23.76 44.917 ;
     RECT  11.256 44.437 12.384 44.483 ;
     RECT  11.16 44.483 12.384 45.059 ;
     RECT  6.216 45.059 7.68 53.603 ;
     RECT  22.776 45.635 23.808 48.515 ;
     RECT  18.912 46.211 20.448 47.173 ;
     RECT  29.712 46.499 31.008 51.299 ;
     RECT  18.912 47.173 20.352 127.139 ;
     RECT  22.776 48.515 24 50.101 ;
     RECT  25.032 50.195 26.064 50.771 ;
     RECT  26.616 50.195 27.6 51.827 ;
     RECT  20.376 50.771 21.84 51.347 ;
     RECT  25.032 50.771 26.592 51.347 ;
     RECT  26.352 51.347 26.592 51.781 ;
     RECT  26.376 51.827 27.6 51.923 ;
     RECT  31.344 55.907 31.392 57.349 ;
     RECT  6.456 62.341 7.8 108.899 ;
     RECT  29.712 66.565 31.152 68.387 ;
     RECT  29.712 68.387 31.2 70.307 ;
     RECT  4.776 95.125 5.808 104.339 ;
     RECT  3.288 95.219 4.752 116.915 ;
     RECT  6.552 120.229 7.8 124.211 ;
     RECT  2.712 124.165 4.176 126.611 ;
  END
END qkd_host_prompt_capture_pins
END LIBRARY
